VERSION 5.8 ;
BUSBITCHARS "[]" ;
DIVIDERCHAR "/" ;
UNITS
    DATABASE MICRONS 1000 ;
END UNITS

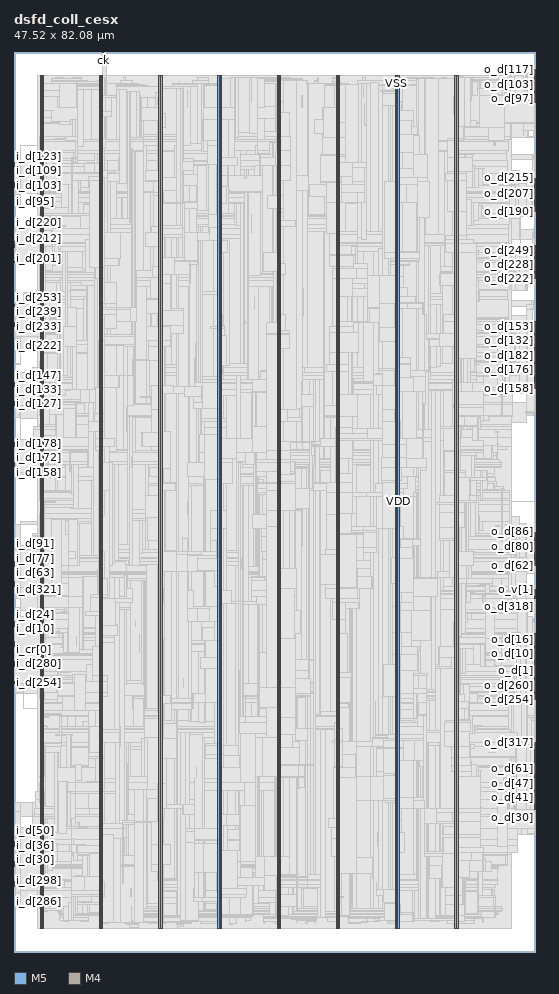
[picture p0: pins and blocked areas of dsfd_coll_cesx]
MACRO dsfd_coll_cesx
  FOREIGN dsfd_coll_cesx 0 0 ;
  CLASS BLOCK ;
  SIZE 47.52 BY 82.08 ;
  PIN ck
    DIRECTION INPUT ;
    USE SIGNAL ;
    PORT
      LAYER M5 ;
        RECT  8.112 81.996 8.136 82.08 ;
    END
  END ck
  PIN e_en
    DIRECTION INPUT ;
    USE SIGNAL ;
    PORT
      LAYER M5 ;
        RECT  8.208 81.996 8.232 82.08 ;
    END
  END e_en
  PIN i_cr[0]
    DIRECTION OUTPUT ;
    USE SIGNAL ;
    PORT
      LAYER M4 ;
        RECT  0 27.6 0.084 27.624 ;
    END
  END i_cr[0]
  PIN i_cr[1]
    DIRECTION OUTPUT ;
    USE SIGNAL ;
    PORT
      LAYER M4 ;
        RECT  0 27.696 0.084 27.72 ;
    END
  END i_cr[1]
  PIN i_d[0]
    DIRECTION INPUT ;
    USE SIGNAL ;
    PORT
      LAYER M4 ;
        RECT  0 27.792 0.084 27.816 ;
    END
  END i_d[0]
  PIN i_d[100]
    DIRECTION INPUT ;
    USE SIGNAL ;
    PORT
      LAYER M4 ;
        RECT  0 69.648 0.084 69.672 ;
    END
  END i_d[100]
  PIN i_d[101]
    DIRECTION INPUT ;
    USE SIGNAL ;
    PORT
      LAYER M4 ;
        RECT  0 69.744 0.084 69.768 ;
    END
  END i_d[101]
  PIN i_d[102]
    DIRECTION INPUT ;
    USE SIGNAL ;
    PORT
      LAYER M4 ;
        RECT  0 69.84 0.084 69.864 ;
    END
  END i_d[102]
  PIN i_d[103]
    DIRECTION INPUT ;
    USE SIGNAL ;
    PORT
      LAYER M4 ;
        RECT  0 69.936 0.084 69.96 ;
    END
  END i_d[103]
  PIN i_d[104]
    DIRECTION INPUT ;
    USE SIGNAL ;
    PORT
      LAYER M4 ;
        RECT  0 70.032 0.084 70.056 ;
    END
  END i_d[104]
  PIN i_d[105]
    DIRECTION INPUT ;
    USE SIGNAL ;
    PORT
      LAYER M4 ;
        RECT  0 70.128 0.084 70.152 ;
    END
  END i_d[105]
  PIN i_d[106]
    DIRECTION INPUT ;
    USE SIGNAL ;
    PORT
      LAYER M4 ;
        RECT  0 70.224 0.084 70.248 ;
    END
  END i_d[106]
  PIN i_d[107]
    DIRECTION INPUT ;
    USE SIGNAL ;
    PORT
      LAYER M4 ;
        RECT  0 70.32 0.084 70.344 ;
    END
  END i_d[107]
  PIN i_d[108]
    DIRECTION INPUT ;
    USE SIGNAL ;
    PORT
      LAYER M4 ;
        RECT  0 70.416 0.084 70.44 ;
    END
  END i_d[108]
  PIN i_d[109]
    DIRECTION INPUT ;
    USE SIGNAL ;
    PORT
      LAYER M4 ;
        RECT  0 70.512 0.084 70.536 ;
    END
  END i_d[109]
  PIN i_d[10]
    DIRECTION INPUT ;
    USE SIGNAL ;
    PORT
      LAYER M4 ;
        RECT  0 28.752 0.084 28.776 ;
    END
  END i_d[10]
  PIN i_d[110]
    DIRECTION INPUT ;
    USE SIGNAL ;
    PORT
      LAYER M4 ;
        RECT  0 70.608 0.084 70.632 ;
    END
  END i_d[110]
  PIN i_d[111]
    DIRECTION INPUT ;
    USE SIGNAL ;
    PORT
      LAYER M4 ;
        RECT  0 70.704 0.084 70.728 ;
    END
  END i_d[111]
  PIN i_d[112]
    DIRECTION INPUT ;
    USE SIGNAL ;
    PORT
      LAYER M4 ;
        RECT  0 70.8 0.084 70.824 ;
    END
  END i_d[112]
  PIN i_d[113]
    DIRECTION INPUT ;
    USE SIGNAL ;
    PORT
      LAYER M4 ;
        RECT  0 70.896 0.084 70.92 ;
    END
  END i_d[113]
  PIN i_d[114]
    DIRECTION INPUT ;
    USE SIGNAL ;
    PORT
      LAYER M4 ;
        RECT  0 70.992 0.084 71.016 ;
    END
  END i_d[114]
  PIN i_d[115]
    DIRECTION INPUT ;
    USE SIGNAL ;
    PORT
      LAYER M4 ;
        RECT  0 71.088 0.084 71.112 ;
    END
  END i_d[115]
  PIN i_d[116]
    DIRECTION INPUT ;
    USE SIGNAL ;
    PORT
      LAYER M4 ;
        RECT  0 71.184 0.084 71.208 ;
    END
  END i_d[116]
  PIN i_d[117]
    DIRECTION INPUT ;
    USE SIGNAL ;
    PORT
      LAYER M4 ;
        RECT  0 71.28 0.084 71.304 ;
    END
  END i_d[117]
  PIN i_d[118]
    DIRECTION INPUT ;
    USE SIGNAL ;
    PORT
      LAYER M4 ;
        RECT  0 71.376 0.084 71.4 ;
    END
  END i_d[118]
  PIN i_d[119]
    DIRECTION INPUT ;
    USE SIGNAL ;
    PORT
      LAYER M4 ;
        RECT  0 71.472 0.084 71.496 ;
    END
  END i_d[119]
  PIN i_d[11]
    DIRECTION INPUT ;
    USE SIGNAL ;
    PORT
      LAYER M4 ;
        RECT  0 28.848 0.084 28.872 ;
    END
  END i_d[11]
  PIN i_d[120]
    DIRECTION INPUT ;
    USE SIGNAL ;
    PORT
      LAYER M4 ;
        RECT  0 71.568 0.084 71.592 ;
    END
  END i_d[120]
  PIN i_d[121]
    DIRECTION INPUT ;
    USE SIGNAL ;
    PORT
      LAYER M4 ;
        RECT  0 71.664 0.084 71.688 ;
    END
  END i_d[121]
  PIN i_d[122]
    DIRECTION INPUT ;
    USE SIGNAL ;
    PORT
      LAYER M4 ;
        RECT  0 71.76 0.084 71.784 ;
    END
  END i_d[122]
  PIN i_d[123]
    DIRECTION INPUT ;
    USE SIGNAL ;
    PORT
      LAYER M4 ;
        RECT  0 71.856 0.084 71.88 ;
    END
  END i_d[123]
  PIN i_d[124]
    DIRECTION INPUT ;
    USE SIGNAL ;
    PORT
      LAYER M4 ;
        RECT  0 71.952 0.084 71.976 ;
    END
  END i_d[124]
  PIN i_d[125]
    DIRECTION INPUT ;
    USE SIGNAL ;
    PORT
      LAYER M4 ;
        RECT  0 72.048 0.084 72.072 ;
    END
  END i_d[125]
  PIN i_d[126]
    DIRECTION INPUT ;
    USE SIGNAL ;
    PORT
      LAYER M4 ;
        RECT  0 49.872 0.084 49.896 ;
    END
  END i_d[126]
  PIN i_d[127]
    DIRECTION INPUT ;
    USE SIGNAL ;
    PORT
      LAYER M4 ;
        RECT  0 49.968 0.084 49.992 ;
    END
  END i_d[127]
  PIN i_d[128]
    DIRECTION INPUT ;
    USE SIGNAL ;
    PORT
      LAYER M4 ;
        RECT  0 50.064 0.084 50.088 ;
    END
  END i_d[128]
  PIN i_d[129]
    DIRECTION INPUT ;
    USE SIGNAL ;
    PORT
      LAYER M4 ;
        RECT  0 50.16 0.084 50.184 ;
    END
  END i_d[129]
  PIN i_d[12]
    DIRECTION INPUT ;
    USE SIGNAL ;
    PORT
      LAYER M4 ;
        RECT  0 28.944 0.084 28.968 ;
    END
  END i_d[12]
  PIN i_d[130]
    DIRECTION INPUT ;
    USE SIGNAL ;
    PORT
      LAYER M4 ;
        RECT  0 50.256 0.084 50.28 ;
    END
  END i_d[130]
  PIN i_d[131]
    DIRECTION INPUT ;
    USE SIGNAL ;
    PORT
      LAYER M4 ;
        RECT  0 50.352 0.084 50.376 ;
    END
  END i_d[131]
  PIN i_d[132]
    DIRECTION INPUT ;
    USE SIGNAL ;
    PORT
      LAYER M4 ;
        RECT  0 50.448 0.084 50.472 ;
    END
  END i_d[132]
  PIN i_d[133]
    DIRECTION INPUT ;
    USE SIGNAL ;
    PORT
      LAYER M4 ;
        RECT  0 50.544 0.084 50.568 ;
    END
  END i_d[133]
  PIN i_d[134]
    DIRECTION INPUT ;
    USE SIGNAL ;
    PORT
      LAYER M4 ;
        RECT  0 50.64 0.084 50.664 ;
    END
  END i_d[134]
  PIN i_d[135]
    DIRECTION INPUT ;
    USE SIGNAL ;
    PORT
      LAYER M4 ;
        RECT  0 50.736 0.084 50.76 ;
    END
  END i_d[135]
  PIN i_d[136]
    DIRECTION INPUT ;
    USE SIGNAL ;
    PORT
      LAYER M4 ;
        RECT  0 50.832 0.084 50.856 ;
    END
  END i_d[136]
  PIN i_d[137]
    DIRECTION INPUT ;
    USE SIGNAL ;
    PORT
      LAYER M4 ;
        RECT  0 50.928 0.084 50.952 ;
    END
  END i_d[137]
  PIN i_d[138]
    DIRECTION INPUT ;
    USE SIGNAL ;
    PORT
      LAYER M4 ;
        RECT  0 51.024 0.084 51.048 ;
    END
  END i_d[138]
  PIN i_d[139]
    DIRECTION INPUT ;
    USE SIGNAL ;
    PORT
      LAYER M4 ;
        RECT  0 51.12 0.084 51.144 ;
    END
  END i_d[139]
  PIN i_d[13]
    DIRECTION INPUT ;
    USE SIGNAL ;
    PORT
      LAYER M4 ;
        RECT  0 29.04 0.084 29.064 ;
    END
  END i_d[13]
  PIN i_d[140]
    DIRECTION INPUT ;
    USE SIGNAL ;
    PORT
      LAYER M4 ;
        RECT  0 51.216 0.084 51.24 ;
    END
  END i_d[140]
  PIN i_d[141]
    DIRECTION INPUT ;
    USE SIGNAL ;
    PORT
      LAYER M4 ;
        RECT  0 51.312 0.084 51.336 ;
    END
  END i_d[141]
  PIN i_d[142]
    DIRECTION INPUT ;
    USE SIGNAL ;
    PORT
      LAYER M4 ;
        RECT  0 51.408 0.084 51.432 ;
    END
  END i_d[142]
  PIN i_d[143]
    DIRECTION INPUT ;
    USE SIGNAL ;
    PORT
      LAYER M4 ;
        RECT  0 51.504 0.084 51.528 ;
    END
  END i_d[143]
  PIN i_d[144]
    DIRECTION INPUT ;
    USE SIGNAL ;
    PORT
      LAYER M4 ;
        RECT  0 51.6 0.084 51.624 ;
    END
  END i_d[144]
  PIN i_d[145]
    DIRECTION INPUT ;
    USE SIGNAL ;
    PORT
      LAYER M4 ;
        RECT  0 51.696 0.084 51.72 ;
    END
  END i_d[145]
  PIN i_d[146]
    DIRECTION INPUT ;
    USE SIGNAL ;
    PORT
      LAYER M4 ;
        RECT  0 51.792 0.084 51.816 ;
    END
  END i_d[146]
  PIN i_d[147]
    DIRECTION INPUT ;
    USE SIGNAL ;
    PORT
      LAYER M4 ;
        RECT  0 51.888 0.084 51.912 ;
    END
  END i_d[147]
  PIN i_d[148]
    DIRECTION INPUT ;
    USE SIGNAL ;
    PORT
      LAYER M4 ;
        RECT  0 51.984 0.084 52.008 ;
    END
  END i_d[148]
  PIN i_d[149]
    DIRECTION INPUT ;
    USE SIGNAL ;
    PORT
      LAYER M4 ;
        RECT  0 52.08 0.084 52.104 ;
    END
  END i_d[149]
  PIN i_d[14]
    DIRECTION INPUT ;
    USE SIGNAL ;
    PORT
      LAYER M4 ;
        RECT  0 29.136 0.084 29.16 ;
    END
  END i_d[14]
  PIN i_d[150]
    DIRECTION INPUT ;
    USE SIGNAL ;
    PORT
      LAYER M4 ;
        RECT  0 52.176 0.084 52.2 ;
    END
  END i_d[150]
  PIN i_d[151]
    DIRECTION INPUT ;
    USE SIGNAL ;
    PORT
      LAYER M4 ;
        RECT  0 52.272 0.084 52.296 ;
    END
  END i_d[151]
  PIN i_d[152]
    DIRECTION INPUT ;
    USE SIGNAL ;
    PORT
      LAYER M4 ;
        RECT  0 52.368 0.084 52.392 ;
    END
  END i_d[152]
  PIN i_d[153]
    DIRECTION INPUT ;
    USE SIGNAL ;
    PORT
      LAYER M4 ;
        RECT  0 52.464 0.084 52.488 ;
    END
  END i_d[153]
  PIN i_d[154]
    DIRECTION INPUT ;
    USE SIGNAL ;
    PORT
      LAYER M4 ;
        RECT  0 52.56 0.084 52.584 ;
    END
  END i_d[154]
  PIN i_d[155]
    DIRECTION INPUT ;
    USE SIGNAL ;
    PORT
      LAYER M4 ;
        RECT  0 52.656 0.084 52.68 ;
    END
  END i_d[155]
  PIN i_d[156]
    DIRECTION INPUT ;
    USE SIGNAL ;
    PORT
      LAYER M4 ;
        RECT  0 52.752 0.084 52.776 ;
    END
  END i_d[156]
  PIN i_d[157]
    DIRECTION INPUT ;
    USE SIGNAL ;
    PORT
      LAYER M4 ;
        RECT  0 52.848 0.084 52.872 ;
    END
  END i_d[157]
  PIN i_d[158]
    DIRECTION INPUT ;
    USE SIGNAL ;
    PORT
      LAYER M4 ;
        RECT  0 43.728 0.084 43.752 ;
    END
  END i_d[158]
  PIN i_d[159]
    DIRECTION INPUT ;
    USE SIGNAL ;
    PORT
      LAYER M4 ;
        RECT  0 43.824 0.084 43.848 ;
    END
  END i_d[159]
  PIN i_d[15]
    DIRECTION INPUT ;
    USE SIGNAL ;
    PORT
      LAYER M4 ;
        RECT  0 29.232 0.084 29.256 ;
    END
  END i_d[15]
  PIN i_d[160]
    DIRECTION INPUT ;
    USE SIGNAL ;
    PORT
      LAYER M4 ;
        RECT  0 43.92 0.084 43.944 ;
    END
  END i_d[160]
  PIN i_d[161]
    DIRECTION INPUT ;
    USE SIGNAL ;
    PORT
      LAYER M4 ;
        RECT  0 44.016 0.084 44.04 ;
    END
  END i_d[161]
  PIN i_d[162]
    DIRECTION INPUT ;
    USE SIGNAL ;
    PORT
      LAYER M4 ;
        RECT  0 44.112 0.084 44.136 ;
    END
  END i_d[162]
  PIN i_d[163]
    DIRECTION INPUT ;
    USE SIGNAL ;
    PORT
      LAYER M4 ;
        RECT  0 44.208 0.084 44.232 ;
    END
  END i_d[163]
  PIN i_d[164]
    DIRECTION INPUT ;
    USE SIGNAL ;
    PORT
      LAYER M4 ;
        RECT  0 44.304 0.084 44.328 ;
    END
  END i_d[164]
  PIN i_d[165]
    DIRECTION INPUT ;
    USE SIGNAL ;
    PORT
      LAYER M4 ;
        RECT  0 44.4 0.084 44.424 ;
    END
  END i_d[165]
  PIN i_d[166]
    DIRECTION INPUT ;
    USE SIGNAL ;
    PORT
      LAYER M4 ;
        RECT  0 44.496 0.084 44.52 ;
    END
  END i_d[166]
  PIN i_d[167]
    DIRECTION INPUT ;
    USE SIGNAL ;
    PORT
      LAYER M4 ;
        RECT  0 44.592 0.084 44.616 ;
    END
  END i_d[167]
  PIN i_d[168]
    DIRECTION INPUT ;
    USE SIGNAL ;
    PORT
      LAYER M4 ;
        RECT  0 44.688 0.084 44.712 ;
    END
  END i_d[168]
  PIN i_d[169]
    DIRECTION INPUT ;
    USE SIGNAL ;
    PORT
      LAYER M4 ;
        RECT  0 44.784 0.084 44.808 ;
    END
  END i_d[169]
  PIN i_d[16]
    DIRECTION INPUT ;
    USE SIGNAL ;
    PORT
      LAYER M4 ;
        RECT  0 29.328 0.084 29.352 ;
    END
  END i_d[16]
  PIN i_d[170]
    DIRECTION INPUT ;
    USE SIGNAL ;
    PORT
      LAYER M4 ;
        RECT  0 44.88 0.084 44.904 ;
    END
  END i_d[170]
  PIN i_d[171]
    DIRECTION INPUT ;
    USE SIGNAL ;
    PORT
      LAYER M4 ;
        RECT  0 44.976 0.084 45 ;
    END
  END i_d[171]
  PIN i_d[172]
    DIRECTION INPUT ;
    USE SIGNAL ;
    PORT
      LAYER M4 ;
        RECT  0 45.072 0.084 45.096 ;
    END
  END i_d[172]
  PIN i_d[173]
    DIRECTION INPUT ;
    USE SIGNAL ;
    PORT
      LAYER M4 ;
        RECT  0 45.168 0.084 45.192 ;
    END
  END i_d[173]
  PIN i_d[174]
    DIRECTION INPUT ;
    USE SIGNAL ;
    PORT
      LAYER M4 ;
        RECT  0 45.264 0.084 45.288 ;
    END
  END i_d[174]
  PIN i_d[175]
    DIRECTION INPUT ;
    USE SIGNAL ;
    PORT
      LAYER M4 ;
        RECT  0 45.36 0.084 45.384 ;
    END
  END i_d[175]
  PIN i_d[176]
    DIRECTION INPUT ;
    USE SIGNAL ;
    PORT
      LAYER M4 ;
        RECT  0 45.456 0.084 45.48 ;
    END
  END i_d[176]
  PIN i_d[177]
    DIRECTION INPUT ;
    USE SIGNAL ;
    PORT
      LAYER M4 ;
        RECT  0 45.552 0.084 45.576 ;
    END
  END i_d[177]
  PIN i_d[178]
    DIRECTION INPUT ;
    USE SIGNAL ;
    PORT
      LAYER M4 ;
        RECT  0 45.648 0.084 45.672 ;
    END
  END i_d[178]
  PIN i_d[179]
    DIRECTION INPUT ;
    USE SIGNAL ;
    PORT
      LAYER M4 ;
        RECT  0 45.744 0.084 45.768 ;
    END
  END i_d[179]
  PIN i_d[17]
    DIRECTION INPUT ;
    USE SIGNAL ;
    PORT
      LAYER M4 ;
        RECT  0 29.424 0.084 29.448 ;
    END
  END i_d[17]
  PIN i_d[180]
    DIRECTION INPUT ;
    USE SIGNAL ;
    PORT
      LAYER M4 ;
        RECT  0 45.84 0.084 45.864 ;
    END
  END i_d[180]
  PIN i_d[181]
    DIRECTION INPUT ;
    USE SIGNAL ;
    PORT
      LAYER M4 ;
        RECT  0 45.936 0.084 45.96 ;
    END
  END i_d[181]
  PIN i_d[182]
    DIRECTION INPUT ;
    USE SIGNAL ;
    PORT
      LAYER M4 ;
        RECT  0 46.032 0.084 46.056 ;
    END
  END i_d[182]
  PIN i_d[183]
    DIRECTION INPUT ;
    USE SIGNAL ;
    PORT
      LAYER M4 ;
        RECT  0 46.128 0.084 46.152 ;
    END
  END i_d[183]
  PIN i_d[184]
    DIRECTION INPUT ;
    USE SIGNAL ;
    PORT
      LAYER M4 ;
        RECT  0 46.224 0.084 46.248 ;
    END
  END i_d[184]
  PIN i_d[185]
    DIRECTION INPUT ;
    USE SIGNAL ;
    PORT
      LAYER M4 ;
        RECT  0 46.32 0.084 46.344 ;
    END
  END i_d[185]
  PIN i_d[186]
    DIRECTION INPUT ;
    USE SIGNAL ;
    PORT
      LAYER M4 ;
        RECT  0 46.416 0.084 46.44 ;
    END
  END i_d[186]
  PIN i_d[187]
    DIRECTION INPUT ;
    USE SIGNAL ;
    PORT
      LAYER M4 ;
        RECT  0 46.512 0.084 46.536 ;
    END
  END i_d[187]
  PIN i_d[188]
    DIRECTION INPUT ;
    USE SIGNAL ;
    PORT
      LAYER M4 ;
        RECT  0 46.608 0.084 46.632 ;
    END
  END i_d[188]
  PIN i_d[189]
    DIRECTION INPUT ;
    USE SIGNAL ;
    PORT
      LAYER M4 ;
        RECT  0 46.704 0.084 46.728 ;
    END
  END i_d[189]
  PIN i_d[18]
    DIRECTION INPUT ;
    USE SIGNAL ;
    PORT
      LAYER M4 ;
        RECT  0 29.52 0.084 29.544 ;
    END
  END i_d[18]
  PIN i_d[190]
    DIRECTION INPUT ;
    USE SIGNAL ;
    PORT
      LAYER M4 ;
        RECT  0 62.928 0.084 62.952 ;
    END
  END i_d[190]
  PIN i_d[191]
    DIRECTION INPUT ;
    USE SIGNAL ;
    PORT
      LAYER M4 ;
        RECT  0 63.024 0.084 63.048 ;
    END
  END i_d[191]
  PIN i_d[192]
    DIRECTION INPUT ;
    USE SIGNAL ;
    PORT
      LAYER M4 ;
        RECT  0 63.12 0.084 63.144 ;
    END
  END i_d[192]
  PIN i_d[193]
    DIRECTION INPUT ;
    USE SIGNAL ;
    PORT
      LAYER M4 ;
        RECT  0 63.216 0.084 63.24 ;
    END
  END i_d[193]
  PIN i_d[194]
    DIRECTION INPUT ;
    USE SIGNAL ;
    PORT
      LAYER M4 ;
        RECT  0 63.312 0.084 63.336 ;
    END
  END i_d[194]
  PIN i_d[195]
    DIRECTION INPUT ;
    USE SIGNAL ;
    PORT
      LAYER M4 ;
        RECT  0 63.408 0.084 63.432 ;
    END
  END i_d[195]
  PIN i_d[196]
    DIRECTION INPUT ;
    USE SIGNAL ;
    PORT
      LAYER M4 ;
        RECT  0 63.504 0.084 63.528 ;
    END
  END i_d[196]
  PIN i_d[197]
    DIRECTION INPUT ;
    USE SIGNAL ;
    PORT
      LAYER M4 ;
        RECT  0 63.6 0.084 63.624 ;
    END
  END i_d[197]
  PIN i_d[198]
    DIRECTION INPUT ;
    USE SIGNAL ;
    PORT
      LAYER M4 ;
        RECT  0 63.696 0.084 63.72 ;
    END
  END i_d[198]
  PIN i_d[199]
    DIRECTION INPUT ;
    USE SIGNAL ;
    PORT
      LAYER M4 ;
        RECT  0 63.792 0.084 63.816 ;
    END
  END i_d[199]
  PIN i_d[19]
    DIRECTION INPUT ;
    USE SIGNAL ;
    PORT
      LAYER M4 ;
        RECT  0 29.616 0.084 29.64 ;
    END
  END i_d[19]
  PIN i_d[1]
    DIRECTION INPUT ;
    USE SIGNAL ;
    PORT
      LAYER M4 ;
        RECT  0 27.888 0.084 27.912 ;
    END
  END i_d[1]
  PIN i_d[200]
    DIRECTION INPUT ;
    USE SIGNAL ;
    PORT
      LAYER M4 ;
        RECT  0 63.888 0.084 63.912 ;
    END
  END i_d[200]
  PIN i_d[201]
    DIRECTION INPUT ;
    USE SIGNAL ;
    PORT
      LAYER M4 ;
        RECT  0 63.984 0.084 64.008 ;
    END
  END i_d[201]
  PIN i_d[202]
    DIRECTION INPUT ;
    USE SIGNAL ;
    PORT
      LAYER M4 ;
        RECT  0 64.08 0.084 64.104 ;
    END
  END i_d[202]
  PIN i_d[203]
    DIRECTION INPUT ;
    USE SIGNAL ;
    PORT
      LAYER M4 ;
        RECT  0 64.176 0.084 64.2 ;
    END
  END i_d[203]
  PIN i_d[204]
    DIRECTION INPUT ;
    USE SIGNAL ;
    PORT
      LAYER M4 ;
        RECT  0 64.272 0.084 64.296 ;
    END
  END i_d[204]
  PIN i_d[205]
    DIRECTION INPUT ;
    USE SIGNAL ;
    PORT
      LAYER M4 ;
        RECT  0 64.368 0.084 64.392 ;
    END
  END i_d[205]
  PIN i_d[206]
    DIRECTION INPUT ;
    USE SIGNAL ;
    PORT
      LAYER M4 ;
        RECT  0 64.464 0.084 64.488 ;
    END
  END i_d[206]
  PIN i_d[207]
    DIRECTION INPUT ;
    USE SIGNAL ;
    PORT
      LAYER M4 ;
        RECT  0 64.56 0.084 64.584 ;
    END
  END i_d[207]
  PIN i_d[208]
    DIRECTION INPUT ;
    USE SIGNAL ;
    PORT
      LAYER M4 ;
        RECT  0 64.656 0.084 64.68 ;
    END
  END i_d[208]
  PIN i_d[209]
    DIRECTION INPUT ;
    USE SIGNAL ;
    PORT
      LAYER M4 ;
        RECT  0 64.752 0.084 64.776 ;
    END
  END i_d[209]
  PIN i_d[20]
    DIRECTION INPUT ;
    USE SIGNAL ;
    PORT
      LAYER M4 ;
        RECT  0 29.712 0.084 29.736 ;
    END
  END i_d[20]
  PIN i_d[210]
    DIRECTION INPUT ;
    USE SIGNAL ;
    PORT
      LAYER M4 ;
        RECT  0 64.848 0.084 64.872 ;
    END
  END i_d[210]
  PIN i_d[211]
    DIRECTION INPUT ;
    USE SIGNAL ;
    PORT
      LAYER M4 ;
        RECT  0 64.944 0.084 64.968 ;
    END
  END i_d[211]
  PIN i_d[212]
    DIRECTION INPUT ;
    USE SIGNAL ;
    PORT
      LAYER M4 ;
        RECT  0 65.04 0.084 65.064 ;
    END
  END i_d[212]
  PIN i_d[213]
    DIRECTION INPUT ;
    USE SIGNAL ;
    PORT
      LAYER M4 ;
        RECT  0 65.136 0.084 65.16 ;
    END
  END i_d[213]
  PIN i_d[214]
    DIRECTION INPUT ;
    USE SIGNAL ;
    PORT
      LAYER M4 ;
        RECT  0 65.232 0.084 65.256 ;
    END
  END i_d[214]
  PIN i_d[215]
    DIRECTION INPUT ;
    USE SIGNAL ;
    PORT
      LAYER M4 ;
        RECT  0 65.328 0.084 65.352 ;
    END
  END i_d[215]
  PIN i_d[216]
    DIRECTION INPUT ;
    USE SIGNAL ;
    PORT
      LAYER M4 ;
        RECT  0 65.424 0.084 65.448 ;
    END
  END i_d[216]
  PIN i_d[217]
    DIRECTION INPUT ;
    USE SIGNAL ;
    PORT
      LAYER M4 ;
        RECT  0 65.52 0.084 65.544 ;
    END
  END i_d[217]
  PIN i_d[218]
    DIRECTION INPUT ;
    USE SIGNAL ;
    PORT
      LAYER M4 ;
        RECT  0 65.616 0.084 65.64 ;
    END
  END i_d[218]
  PIN i_d[219]
    DIRECTION INPUT ;
    USE SIGNAL ;
    PORT
      LAYER M4 ;
        RECT  0 65.712 0.084 65.736 ;
    END
  END i_d[219]
  PIN i_d[21]
    DIRECTION INPUT ;
    USE SIGNAL ;
    PORT
      LAYER M4 ;
        RECT  0 29.808 0.084 29.832 ;
    END
  END i_d[21]
  PIN i_d[220]
    DIRECTION INPUT ;
    USE SIGNAL ;
    PORT
      LAYER M4 ;
        RECT  0 65.808 0.084 65.832 ;
    END
  END i_d[220]
  PIN i_d[221]
    DIRECTION INPUT ;
    USE SIGNAL ;
    PORT
      LAYER M4 ;
        RECT  0 65.904 0.084 65.928 ;
    END
  END i_d[221]
  PIN i_d[222]
    DIRECTION INPUT ;
    USE SIGNAL ;
    PORT
      LAYER M4 ;
        RECT  0 56.016 0.084 56.04 ;
    END
  END i_d[222]
  PIN i_d[223]
    DIRECTION INPUT ;
    USE SIGNAL ;
    PORT
      LAYER M4 ;
        RECT  0 56.112 0.084 56.136 ;
    END
  END i_d[223]
  PIN i_d[224]
    DIRECTION INPUT ;
    USE SIGNAL ;
    PORT
      LAYER M4 ;
        RECT  0 56.208 0.084 56.232 ;
    END
  END i_d[224]
  PIN i_d[225]
    DIRECTION INPUT ;
    USE SIGNAL ;
    PORT
      LAYER M4 ;
        RECT  0 56.304 0.084 56.328 ;
    END
  END i_d[225]
  PIN i_d[226]
    DIRECTION INPUT ;
    USE SIGNAL ;
    PORT
      LAYER M4 ;
        RECT  0 56.4 0.084 56.424 ;
    END
  END i_d[226]
  PIN i_d[227]
    DIRECTION INPUT ;
    USE SIGNAL ;
    PORT
      LAYER M4 ;
        RECT  0 56.496 0.084 56.52 ;
    END
  END i_d[227]
  PIN i_d[228]
    DIRECTION INPUT ;
    USE SIGNAL ;
    PORT
      LAYER M4 ;
        RECT  0 56.592 0.084 56.616 ;
    END
  END i_d[228]
  PIN i_d[229]
    DIRECTION INPUT ;
    USE SIGNAL ;
    PORT
      LAYER M4 ;
        RECT  0 56.688 0.084 56.712 ;
    END
  END i_d[229]
  PIN i_d[22]
    DIRECTION INPUT ;
    USE SIGNAL ;
    PORT
      LAYER M4 ;
        RECT  0 29.904 0.084 29.928 ;
    END
  END i_d[22]
  PIN i_d[230]
    DIRECTION INPUT ;
    USE SIGNAL ;
    PORT
      LAYER M4 ;
        RECT  0 56.784 0.084 56.808 ;
    END
  END i_d[230]
  PIN i_d[231]
    DIRECTION INPUT ;
    USE SIGNAL ;
    PORT
      LAYER M4 ;
        RECT  0 56.88 0.084 56.904 ;
    END
  END i_d[231]
  PIN i_d[232]
    DIRECTION INPUT ;
    USE SIGNAL ;
    PORT
      LAYER M4 ;
        RECT  0 56.976 0.084 57 ;
    END
  END i_d[232]
  PIN i_d[233]
    DIRECTION INPUT ;
    USE SIGNAL ;
    PORT
      LAYER M4 ;
        RECT  0 57.072 0.084 57.096 ;
    END
  END i_d[233]
  PIN i_d[234]
    DIRECTION INPUT ;
    USE SIGNAL ;
    PORT
      LAYER M4 ;
        RECT  0 57.168 0.084 57.192 ;
    END
  END i_d[234]
  PIN i_d[235]
    DIRECTION INPUT ;
    USE SIGNAL ;
    PORT
      LAYER M4 ;
        RECT  0 57.264 0.084 57.288 ;
    END
  END i_d[235]
  PIN i_d[236]
    DIRECTION INPUT ;
    USE SIGNAL ;
    PORT
      LAYER M4 ;
        RECT  0 57.36 0.084 57.384 ;
    END
  END i_d[236]
  PIN i_d[237]
    DIRECTION INPUT ;
    USE SIGNAL ;
    PORT
      LAYER M4 ;
        RECT  0 57.456 0.084 57.48 ;
    END
  END i_d[237]
  PIN i_d[238]
    DIRECTION INPUT ;
    USE SIGNAL ;
    PORT
      LAYER M4 ;
        RECT  0 57.552 0.084 57.576 ;
    END
  END i_d[238]
  PIN i_d[239]
    DIRECTION INPUT ;
    USE SIGNAL ;
    PORT
      LAYER M4 ;
        RECT  0 57.648 0.084 57.672 ;
    END
  END i_d[239]
  PIN i_d[23]
    DIRECTION INPUT ;
    USE SIGNAL ;
    PORT
      LAYER M4 ;
        RECT  0 30 0.084 30.024 ;
    END
  END i_d[23]
  PIN i_d[240]
    DIRECTION INPUT ;
    USE SIGNAL ;
    PORT
      LAYER M4 ;
        RECT  0 57.744 0.084 57.768 ;
    END
  END i_d[240]
  PIN i_d[241]
    DIRECTION INPUT ;
    USE SIGNAL ;
    PORT
      LAYER M4 ;
        RECT  0 57.84 0.084 57.864 ;
    END
  END i_d[241]
  PIN i_d[242]
    DIRECTION INPUT ;
    USE SIGNAL ;
    PORT
      LAYER M4 ;
        RECT  0 57.936 0.084 57.96 ;
    END
  END i_d[242]
  PIN i_d[243]
    DIRECTION INPUT ;
    USE SIGNAL ;
    PORT
      LAYER M4 ;
        RECT  0 58.032 0.084 58.056 ;
    END
  END i_d[243]
  PIN i_d[244]
    DIRECTION INPUT ;
    USE SIGNAL ;
    PORT
      LAYER M4 ;
        RECT  0 58.128 0.084 58.152 ;
    END
  END i_d[244]
  PIN i_d[245]
    DIRECTION INPUT ;
    USE SIGNAL ;
    PORT
      LAYER M4 ;
        RECT  0 58.224 0.084 58.248 ;
    END
  END i_d[245]
  PIN i_d[246]
    DIRECTION INPUT ;
    USE SIGNAL ;
    PORT
      LAYER M4 ;
        RECT  0 58.32 0.084 58.344 ;
    END
  END i_d[246]
  PIN i_d[247]
    DIRECTION INPUT ;
    USE SIGNAL ;
    PORT
      LAYER M4 ;
        RECT  0 58.416 0.084 58.44 ;
    END
  END i_d[247]
  PIN i_d[248]
    DIRECTION INPUT ;
    USE SIGNAL ;
    PORT
      LAYER M4 ;
        RECT  0 58.512 0.084 58.536 ;
    END
  END i_d[248]
  PIN i_d[249]
    DIRECTION INPUT ;
    USE SIGNAL ;
    PORT
      LAYER M4 ;
        RECT  0 58.608 0.084 58.632 ;
    END
  END i_d[249]
  PIN i_d[24]
    DIRECTION INPUT ;
    USE SIGNAL ;
    PORT
      LAYER M4 ;
        RECT  0 30.096 0.084 30.12 ;
    END
  END i_d[24]
  PIN i_d[250]
    DIRECTION INPUT ;
    USE SIGNAL ;
    PORT
      LAYER M4 ;
        RECT  0 58.704 0.084 58.728 ;
    END
  END i_d[250]
  PIN i_d[251]
    DIRECTION INPUT ;
    USE SIGNAL ;
    PORT
      LAYER M4 ;
        RECT  0 58.8 0.084 58.824 ;
    END
  END i_d[251]
  PIN i_d[252]
    DIRECTION INPUT ;
    USE SIGNAL ;
    PORT
      LAYER M4 ;
        RECT  0 58.896 0.084 58.92 ;
    END
  END i_d[252]
  PIN i_d[253]
    DIRECTION INPUT ;
    USE SIGNAL ;
    PORT
      LAYER M4 ;
        RECT  0 58.992 0.084 59.016 ;
    END
  END i_d[253]
  PIN i_d[254]
    DIRECTION INPUT ;
    USE SIGNAL ;
    PORT
      LAYER M4 ;
        RECT  0 24.528 0.084 24.552 ;
    END
  END i_d[254]
  PIN i_d[255]
    DIRECTION INPUT ;
    USE SIGNAL ;
    PORT
      LAYER M4 ;
        RECT  0 24.624 0.084 24.648 ;
    END
  END i_d[255]
  PIN i_d[256]
    DIRECTION INPUT ;
    USE SIGNAL ;
    PORT
      LAYER M4 ;
        RECT  0 24.72 0.084 24.744 ;
    END
  END i_d[256]
  PIN i_d[257]
    DIRECTION INPUT ;
    USE SIGNAL ;
    PORT
      LAYER M4 ;
        RECT  0 24.816 0.084 24.84 ;
    END
  END i_d[257]
  PIN i_d[258]
    DIRECTION INPUT ;
    USE SIGNAL ;
    PORT
      LAYER M4 ;
        RECT  0 24.912 0.084 24.936 ;
    END
  END i_d[258]
  PIN i_d[259]
    DIRECTION INPUT ;
    USE SIGNAL ;
    PORT
      LAYER M4 ;
        RECT  0 25.008 0.084 25.032 ;
    END
  END i_d[259]
  PIN i_d[25]
    DIRECTION INPUT ;
    USE SIGNAL ;
    PORT
      LAYER M4 ;
        RECT  0 30.192 0.084 30.216 ;
    END
  END i_d[25]
  PIN i_d[260]
    DIRECTION INPUT ;
    USE SIGNAL ;
    PORT
      LAYER M4 ;
        RECT  0 25.104 0.084 25.128 ;
    END
  END i_d[260]
  PIN i_d[261]
    DIRECTION INPUT ;
    USE SIGNAL ;
    PORT
      LAYER M4 ;
        RECT  0 25.2 0.084 25.224 ;
    END
  END i_d[261]
  PIN i_d[262]
    DIRECTION INPUT ;
    USE SIGNAL ;
    PORT
      LAYER M4 ;
        RECT  0 25.296 0.084 25.32 ;
    END
  END i_d[262]
  PIN i_d[263]
    DIRECTION INPUT ;
    USE SIGNAL ;
    PORT
      LAYER M4 ;
        RECT  0 25.392 0.084 25.416 ;
    END
  END i_d[263]
  PIN i_d[264]
    DIRECTION INPUT ;
    USE SIGNAL ;
    PORT
      LAYER M4 ;
        RECT  0 25.488 0.084 25.512 ;
    END
  END i_d[264]
  PIN i_d[265]
    DIRECTION INPUT ;
    USE SIGNAL ;
    PORT
      LAYER M4 ;
        RECT  0 25.584 0.084 25.608 ;
    END
  END i_d[265]
  PIN i_d[266]
    DIRECTION INPUT ;
    USE SIGNAL ;
    PORT
      LAYER M4 ;
        RECT  0 25.68 0.084 25.704 ;
    END
  END i_d[266]
  PIN i_d[267]
    DIRECTION INPUT ;
    USE SIGNAL ;
    PORT
      LAYER M4 ;
        RECT  0 25.776 0.084 25.8 ;
    END
  END i_d[267]
  PIN i_d[268]
    DIRECTION INPUT ;
    USE SIGNAL ;
    PORT
      LAYER M4 ;
        RECT  0 25.872 0.084 25.896 ;
    END
  END i_d[268]
  PIN i_d[269]
    DIRECTION INPUT ;
    USE SIGNAL ;
    PORT
      LAYER M4 ;
        RECT  0 25.968 0.084 25.992 ;
    END
  END i_d[269]
  PIN i_d[26]
    DIRECTION INPUT ;
    USE SIGNAL ;
    PORT
      LAYER M4 ;
        RECT  0 30.288 0.084 30.312 ;
    END
  END i_d[26]
  PIN i_d[270]
    DIRECTION INPUT ;
    USE SIGNAL ;
    PORT
      LAYER M4 ;
        RECT  0 26.064 0.084 26.088 ;
    END
  END i_d[270]
  PIN i_d[271]
    DIRECTION INPUT ;
    USE SIGNAL ;
    PORT
      LAYER M4 ;
        RECT  0 26.16 0.084 26.184 ;
    END
  END i_d[271]
  PIN i_d[272]
    DIRECTION INPUT ;
    USE SIGNAL ;
    PORT
      LAYER M4 ;
        RECT  0 26.256 0.084 26.28 ;
    END
  END i_d[272]
  PIN i_d[273]
    DIRECTION INPUT ;
    USE SIGNAL ;
    PORT
      LAYER M4 ;
        RECT  0 26.352 0.084 26.376 ;
    END
  END i_d[273]
  PIN i_d[274]
    DIRECTION INPUT ;
    USE SIGNAL ;
    PORT
      LAYER M4 ;
        RECT  0 26.448 0.084 26.472 ;
    END
  END i_d[274]
  PIN i_d[275]
    DIRECTION INPUT ;
    USE SIGNAL ;
    PORT
      LAYER M4 ;
        RECT  0 26.544 0.084 26.568 ;
    END
  END i_d[275]
  PIN i_d[276]
    DIRECTION INPUT ;
    USE SIGNAL ;
    PORT
      LAYER M4 ;
        RECT  0 26.64 0.084 26.664 ;
    END
  END i_d[276]
  PIN i_d[277]
    DIRECTION INPUT ;
    USE SIGNAL ;
    PORT
      LAYER M4 ;
        RECT  0 26.736 0.084 26.76 ;
    END
  END i_d[277]
  PIN i_d[278]
    DIRECTION INPUT ;
    USE SIGNAL ;
    PORT
      LAYER M4 ;
        RECT  0 26.832 0.084 26.856 ;
    END
  END i_d[278]
  PIN i_d[279]
    DIRECTION INPUT ;
    USE SIGNAL ;
    PORT
      LAYER M4 ;
        RECT  0 26.928 0.084 26.952 ;
    END
  END i_d[279]
  PIN i_d[27]
    DIRECTION INPUT ;
    USE SIGNAL ;
    PORT
      LAYER M4 ;
        RECT  0 30.384 0.084 30.408 ;
    END
  END i_d[27]
  PIN i_d[280]
    DIRECTION INPUT ;
    USE SIGNAL ;
    PORT
      LAYER M4 ;
        RECT  0 27.024 0.084 27.048 ;
    END
  END i_d[280]
  PIN i_d[281]
    DIRECTION INPUT ;
    USE SIGNAL ;
    PORT
      LAYER M4 ;
        RECT  0 27.12 0.084 27.144 ;
    END
  END i_d[281]
  PIN i_d[282]
    DIRECTION INPUT ;
    USE SIGNAL ;
    PORT
      LAYER M4 ;
        RECT  0 27.216 0.084 27.24 ;
    END
  END i_d[282]
  PIN i_d[283]
    DIRECTION INPUT ;
    USE SIGNAL ;
    PORT
      LAYER M4 ;
        RECT  0 27.312 0.084 27.336 ;
    END
  END i_d[283]
  PIN i_d[284]
    DIRECTION INPUT ;
    USE SIGNAL ;
    PORT
      LAYER M4 ;
        RECT  0 27.408 0.084 27.432 ;
    END
  END i_d[284]
  PIN i_d[285]
    DIRECTION INPUT ;
    USE SIGNAL ;
    PORT
      LAYER M4 ;
        RECT  0 27.504 0.084 27.528 ;
    END
  END i_d[285]
  PIN i_d[286]
    DIRECTION INPUT ;
    USE SIGNAL ;
    PORT
      LAYER M4 ;
        RECT  0 5.328 0.084 5.352 ;
    END
  END i_d[286]
  PIN i_d[287]
    DIRECTION INPUT ;
    USE SIGNAL ;
    PORT
      LAYER M4 ;
        RECT  0 5.424 0.084 5.448 ;
    END
  END i_d[287]
  PIN i_d[288]
    DIRECTION INPUT ;
    USE SIGNAL ;
    PORT
      LAYER M4 ;
        RECT  0 5.52 0.084 5.544 ;
    END
  END i_d[288]
  PIN i_d[289]
    DIRECTION INPUT ;
    USE SIGNAL ;
    PORT
      LAYER M4 ;
        RECT  0 5.616 0.084 5.64 ;
    END
  END i_d[289]
  PIN i_d[28]
    DIRECTION INPUT ;
    USE SIGNAL ;
    PORT
      LAYER M4 ;
        RECT  0 30.48 0.084 30.504 ;
    END
  END i_d[28]
  PIN i_d[290]
    DIRECTION INPUT ;
    USE SIGNAL ;
    PORT
      LAYER M4 ;
        RECT  0 5.712 0.084 5.736 ;
    END
  END i_d[290]
  PIN i_d[291]
    DIRECTION INPUT ;
    USE SIGNAL ;
    PORT
      LAYER M4 ;
        RECT  0 5.808 0.084 5.832 ;
    END
  END i_d[291]
  PIN i_d[292]
    DIRECTION INPUT ;
    USE SIGNAL ;
    PORT
      LAYER M4 ;
        RECT  0 5.904 0.084 5.928 ;
    END
  END i_d[292]
  PIN i_d[293]
    DIRECTION INPUT ;
    USE SIGNAL ;
    PORT
      LAYER M4 ;
        RECT  0 6 0.084 6.024 ;
    END
  END i_d[293]
  PIN i_d[294]
    DIRECTION INPUT ;
    USE SIGNAL ;
    PORT
      LAYER M4 ;
        RECT  0 6.096 0.084 6.12 ;
    END
  END i_d[294]
  PIN i_d[295]
    DIRECTION INPUT ;
    USE SIGNAL ;
    PORT
      LAYER M4 ;
        RECT  0 6.192 0.084 6.216 ;
    END
  END i_d[295]
  PIN i_d[296]
    DIRECTION INPUT ;
    USE SIGNAL ;
    PORT
      LAYER M4 ;
        RECT  0 6.288 0.084 6.312 ;
    END
  END i_d[296]
  PIN i_d[297]
    DIRECTION INPUT ;
    USE SIGNAL ;
    PORT
      LAYER M4 ;
        RECT  0 6.384 0.084 6.408 ;
    END
  END i_d[297]
  PIN i_d[298]
    DIRECTION INPUT ;
    USE SIGNAL ;
    PORT
      LAYER M4 ;
        RECT  0 6.48 0.084 6.504 ;
    END
  END i_d[298]
  PIN i_d[299]
    DIRECTION INPUT ;
    USE SIGNAL ;
    PORT
      LAYER M4 ;
        RECT  0 6.576 0.084 6.6 ;
    END
  END i_d[299]
  PIN i_d[29]
    DIRECTION INPUT ;
    USE SIGNAL ;
    PORT
      LAYER M4 ;
        RECT  0 30.576 0.084 30.6 ;
    END
  END i_d[29]
  PIN i_d[2]
    DIRECTION INPUT ;
    USE SIGNAL ;
    PORT
      LAYER M4 ;
        RECT  0 27.984 0.084 28.008 ;
    END
  END i_d[2]
  PIN i_d[300]
    DIRECTION INPUT ;
    USE SIGNAL ;
    PORT
      LAYER M4 ;
        RECT  0 6.672 0.084 6.696 ;
    END
  END i_d[300]
  PIN i_d[301]
    DIRECTION INPUT ;
    USE SIGNAL ;
    PORT
      LAYER M4 ;
        RECT  0 6.768 0.084 6.792 ;
    END
  END i_d[301]
  PIN i_d[302]
    DIRECTION INPUT ;
    USE SIGNAL ;
    PORT
      LAYER M4 ;
        RECT  0 6.864 0.084 6.888 ;
    END
  END i_d[302]
  PIN i_d[303]
    DIRECTION INPUT ;
    USE SIGNAL ;
    PORT
      LAYER M4 ;
        RECT  0 6.96 0.084 6.984 ;
    END
  END i_d[303]
  PIN i_d[304]
    DIRECTION INPUT ;
    USE SIGNAL ;
    PORT
      LAYER M4 ;
        RECT  0 7.056 0.084 7.08 ;
    END
  END i_d[304]
  PIN i_d[305]
    DIRECTION INPUT ;
    USE SIGNAL ;
    PORT
      LAYER M4 ;
        RECT  0 7.152 0.084 7.176 ;
    END
  END i_d[305]
  PIN i_d[306]
    DIRECTION INPUT ;
    USE SIGNAL ;
    PORT
      LAYER M4 ;
        RECT  0 7.248 0.084 7.272 ;
    END
  END i_d[306]
  PIN i_d[307]
    DIRECTION INPUT ;
    USE SIGNAL ;
    PORT
      LAYER M4 ;
        RECT  0 7.344 0.084 7.368 ;
    END
  END i_d[307]
  PIN i_d[308]
    DIRECTION INPUT ;
    USE SIGNAL ;
    PORT
      LAYER M4 ;
        RECT  0 7.44 0.084 7.464 ;
    END
  END i_d[308]
  PIN i_d[309]
    DIRECTION INPUT ;
    USE SIGNAL ;
    PORT
      LAYER M4 ;
        RECT  0 7.536 0.084 7.56 ;
    END
  END i_d[309]
  PIN i_d[30]
    DIRECTION INPUT ;
    USE SIGNAL ;
    PORT
      LAYER M4 ;
        RECT  0 8.4 0.084 8.424 ;
    END
  END i_d[30]
  PIN i_d[310]
    DIRECTION INPUT ;
    USE SIGNAL ;
    PORT
      LAYER M4 ;
        RECT  0 7.632 0.084 7.656 ;
    END
  END i_d[310]
  PIN i_d[311]
    DIRECTION INPUT ;
    USE SIGNAL ;
    PORT
      LAYER M4 ;
        RECT  0 7.728 0.084 7.752 ;
    END
  END i_d[311]
  PIN i_d[312]
    DIRECTION INPUT ;
    USE SIGNAL ;
    PORT
      LAYER M4 ;
        RECT  0 7.824 0.084 7.848 ;
    END
  END i_d[312]
  PIN i_d[313]
    DIRECTION INPUT ;
    USE SIGNAL ;
    PORT
      LAYER M4 ;
        RECT  0 7.92 0.084 7.944 ;
    END
  END i_d[313]
  PIN i_d[314]
    DIRECTION INPUT ;
    USE SIGNAL ;
    PORT
      LAYER M4 ;
        RECT  0 8.016 0.084 8.04 ;
    END
  END i_d[314]
  PIN i_d[315]
    DIRECTION INPUT ;
    USE SIGNAL ;
    PORT
      LAYER M4 ;
        RECT  0 8.112 0.084 8.136 ;
    END
  END i_d[315]
  PIN i_d[316]
    DIRECTION INPUT ;
    USE SIGNAL ;
    PORT
      LAYER M4 ;
        RECT  0 8.208 0.084 8.232 ;
    END
  END i_d[316]
  PIN i_d[317]
    DIRECTION INPUT ;
    USE SIGNAL ;
    PORT
      LAYER M4 ;
        RECT  0 8.304 0.084 8.328 ;
    END
  END i_d[317]
  PIN i_d[318]
    DIRECTION INPUT ;
    USE SIGNAL ;
    PORT
      LAYER M4 ;
        RECT  0 32.784 0.084 32.808 ;
    END
  END i_d[318]
  PIN i_d[319]
    DIRECTION INPUT ;
    USE SIGNAL ;
    PORT
      LAYER M4 ;
        RECT  0 32.88 0.084 32.904 ;
    END
  END i_d[319]
  PIN i_d[31]
    DIRECTION INPUT ;
    USE SIGNAL ;
    PORT
      LAYER M4 ;
        RECT  0 8.496 0.084 8.52 ;
    END
  END i_d[31]
  PIN i_d[320]
    DIRECTION INPUT ;
    USE SIGNAL ;
    PORT
      LAYER M4 ;
        RECT  0 32.976 0.084 33 ;
    END
  END i_d[320]
  PIN i_d[321]
    DIRECTION INPUT ;
    USE SIGNAL ;
    PORT
      LAYER M4 ;
        RECT  0 33.072 0.084 33.096 ;
    END
  END i_d[321]
  PIN i_d[322]
    DIRECTION INPUT ;
    USE SIGNAL ;
    PORT
      LAYER M4 ;
        RECT  0 33.168 0.084 33.192 ;
    END
  END i_d[322]
  PIN i_d[323]
    DIRECTION INPUT ;
    USE SIGNAL ;
    PORT
      LAYER M4 ;
        RECT  0 33.264 0.084 33.288 ;
    END
  END i_d[323]
  PIN i_d[324]
    DIRECTION INPUT ;
    USE SIGNAL ;
    PORT
      LAYER M4 ;
        RECT  0 33.36 0.084 33.384 ;
    END
  END i_d[324]
  PIN i_d[325]
    DIRECTION INPUT ;
    USE SIGNAL ;
    PORT
      LAYER M4 ;
        RECT  0 33.456 0.084 33.48 ;
    END
  END i_d[325]
  PIN i_d[32]
    DIRECTION INPUT ;
    USE SIGNAL ;
    PORT
      LAYER M4 ;
        RECT  0 8.592 0.084 8.616 ;
    END
  END i_d[32]
  PIN i_d[33]
    DIRECTION INPUT ;
    USE SIGNAL ;
    PORT
      LAYER M4 ;
        RECT  0 8.688 0.084 8.712 ;
    END
  END i_d[33]
  PIN i_d[34]
    DIRECTION INPUT ;
    USE SIGNAL ;
    PORT
      LAYER M4 ;
        RECT  0 8.784 0.084 8.808 ;
    END
  END i_d[34]
  PIN i_d[35]
    DIRECTION INPUT ;
    USE SIGNAL ;
    PORT
      LAYER M4 ;
        RECT  0 8.88 0.084 8.904 ;
    END
  END i_d[35]
  PIN i_d[36]
    DIRECTION INPUT ;
    USE SIGNAL ;
    PORT
      LAYER M4 ;
        RECT  0 8.976 0.084 9 ;
    END
  END i_d[36]
  PIN i_d[37]
    DIRECTION INPUT ;
    USE SIGNAL ;
    PORT
      LAYER M4 ;
        RECT  0 9.072 0.084 9.096 ;
    END
  END i_d[37]
  PIN i_d[38]
    DIRECTION INPUT ;
    USE SIGNAL ;
    PORT
      LAYER M4 ;
        RECT  0 9.168 0.084 9.192 ;
    END
  END i_d[38]
  PIN i_d[39]
    DIRECTION INPUT ;
    USE SIGNAL ;
    PORT
      LAYER M4 ;
        RECT  0 9.264 0.084 9.288 ;
    END
  END i_d[39]
  PIN i_d[3]
    DIRECTION INPUT ;
    USE SIGNAL ;
    PORT
      LAYER M4 ;
        RECT  0 28.08 0.084 28.104 ;
    END
  END i_d[3]
  PIN i_d[40]
    DIRECTION INPUT ;
    USE SIGNAL ;
    PORT
      LAYER M4 ;
        RECT  0 9.36 0.084 9.384 ;
    END
  END i_d[40]
  PIN i_d[41]
    DIRECTION INPUT ;
    USE SIGNAL ;
    PORT
      LAYER M4 ;
        RECT  0 9.456 0.084 9.48 ;
    END
  END i_d[41]
  PIN i_d[42]
    DIRECTION INPUT ;
    USE SIGNAL ;
    PORT
      LAYER M4 ;
        RECT  0 9.552 0.084 9.576 ;
    END
  END i_d[42]
  PIN i_d[43]
    DIRECTION INPUT ;
    USE SIGNAL ;
    PORT
      LAYER M4 ;
        RECT  0 9.648 0.084 9.672 ;
    END
  END i_d[43]
  PIN i_d[44]
    DIRECTION INPUT ;
    USE SIGNAL ;
    PORT
      LAYER M4 ;
        RECT  0 9.744 0.084 9.768 ;
    END
  END i_d[44]
  PIN i_d[45]
    DIRECTION INPUT ;
    USE SIGNAL ;
    PORT
      LAYER M4 ;
        RECT  0 9.84 0.084 9.864 ;
    END
  END i_d[45]
  PIN i_d[46]
    DIRECTION INPUT ;
    USE SIGNAL ;
    PORT
      LAYER M4 ;
        RECT  0 9.936 0.084 9.96 ;
    END
  END i_d[46]
  PIN i_d[47]
    DIRECTION INPUT ;
    USE SIGNAL ;
    PORT
      LAYER M4 ;
        RECT  0 10.032 0.084 10.056 ;
    END
  END i_d[47]
  PIN i_d[48]
    DIRECTION INPUT ;
    USE SIGNAL ;
    PORT
      LAYER M4 ;
        RECT  0 10.128 0.084 10.152 ;
    END
  END i_d[48]
  PIN i_d[49]
    DIRECTION INPUT ;
    USE SIGNAL ;
    PORT
      LAYER M4 ;
        RECT  0 10.224 0.084 10.248 ;
    END
  END i_d[49]
  PIN i_d[4]
    DIRECTION INPUT ;
    USE SIGNAL ;
    PORT
      LAYER M4 ;
        RECT  0 28.176 0.084 28.2 ;
    END
  END i_d[4]
  PIN i_d[50]
    DIRECTION INPUT ;
    USE SIGNAL ;
    PORT
      LAYER M4 ;
        RECT  0 10.32 0.084 10.344 ;
    END
  END i_d[50]
  PIN i_d[51]
    DIRECTION INPUT ;
    USE SIGNAL ;
    PORT
      LAYER M4 ;
        RECT  0 10.416 0.084 10.44 ;
    END
  END i_d[51]
  PIN i_d[52]
    DIRECTION INPUT ;
    USE SIGNAL ;
    PORT
      LAYER M4 ;
        RECT  0 10.512 0.084 10.536 ;
    END
  END i_d[52]
  PIN i_d[53]
    DIRECTION INPUT ;
    USE SIGNAL ;
    PORT
      LAYER M4 ;
        RECT  0 10.608 0.084 10.632 ;
    END
  END i_d[53]
  PIN i_d[54]
    DIRECTION INPUT ;
    USE SIGNAL ;
    PORT
      LAYER M4 ;
        RECT  0 10.704 0.084 10.728 ;
    END
  END i_d[54]
  PIN i_d[55]
    DIRECTION INPUT ;
    USE SIGNAL ;
    PORT
      LAYER M4 ;
        RECT  0 10.8 0.084 10.824 ;
    END
  END i_d[55]
  PIN i_d[56]
    DIRECTION INPUT ;
    USE SIGNAL ;
    PORT
      LAYER M4 ;
        RECT  0 10.896 0.084 10.92 ;
    END
  END i_d[56]
  PIN i_d[57]
    DIRECTION INPUT ;
    USE SIGNAL ;
    PORT
      LAYER M4 ;
        RECT  0 10.992 0.084 11.016 ;
    END
  END i_d[57]
  PIN i_d[58]
    DIRECTION INPUT ;
    USE SIGNAL ;
    PORT
      LAYER M4 ;
        RECT  0 11.088 0.084 11.112 ;
    END
  END i_d[58]
  PIN i_d[59]
    DIRECTION INPUT ;
    USE SIGNAL ;
    PORT
      LAYER M4 ;
        RECT  0 11.184 0.084 11.208 ;
    END
  END i_d[59]
  PIN i_d[5]
    DIRECTION INPUT ;
    USE SIGNAL ;
    PORT
      LAYER M4 ;
        RECT  0 28.272 0.084 28.296 ;
    END
  END i_d[5]
  PIN i_d[60]
    DIRECTION INPUT ;
    USE SIGNAL ;
    PORT
      LAYER M4 ;
        RECT  0 11.28 0.084 11.304 ;
    END
  END i_d[60]
  PIN i_d[61]
    DIRECTION INPUT ;
    USE SIGNAL ;
    PORT
      LAYER M4 ;
        RECT  0 11.376 0.084 11.4 ;
    END
  END i_d[61]
  PIN i_d[62]
    DIRECTION INPUT ;
    USE SIGNAL ;
    PORT
      LAYER M4 ;
        RECT  0 33.744 0.084 33.768 ;
    END
  END i_d[62]
  PIN i_d[63]
    DIRECTION INPUT ;
    USE SIGNAL ;
    PORT
      LAYER M4 ;
        RECT  0 33.84 0.084 33.864 ;
    END
  END i_d[63]
  PIN i_d[64]
    DIRECTION INPUT ;
    USE SIGNAL ;
    PORT
      LAYER M4 ;
        RECT  0 33.936 0.084 33.96 ;
    END
  END i_d[64]
  PIN i_d[65]
    DIRECTION INPUT ;
    USE SIGNAL ;
    PORT
      LAYER M4 ;
        RECT  0 34.032 0.084 34.056 ;
    END
  END i_d[65]
  PIN i_d[66]
    DIRECTION INPUT ;
    USE SIGNAL ;
    PORT
      LAYER M4 ;
        RECT  0 34.128 0.084 34.152 ;
    END
  END i_d[66]
  PIN i_d[67]
    DIRECTION INPUT ;
    USE SIGNAL ;
    PORT
      LAYER M4 ;
        RECT  0 34.224 0.084 34.248 ;
    END
  END i_d[67]
  PIN i_d[68]
    DIRECTION INPUT ;
    USE SIGNAL ;
    PORT
      LAYER M4 ;
        RECT  0 34.32 0.084 34.344 ;
    END
  END i_d[68]
  PIN i_d[69]
    DIRECTION INPUT ;
    USE SIGNAL ;
    PORT
      LAYER M4 ;
        RECT  0 34.416 0.084 34.44 ;
    END
  END i_d[69]
  PIN i_d[6]
    DIRECTION INPUT ;
    USE SIGNAL ;
    PORT
      LAYER M4 ;
        RECT  0 28.368 0.084 28.392 ;
    END
  END i_d[6]
  PIN i_d[70]
    DIRECTION INPUT ;
    USE SIGNAL ;
    PORT
      LAYER M4 ;
        RECT  0 34.512 0.084 34.536 ;
    END
  END i_d[70]
  PIN i_d[71]
    DIRECTION INPUT ;
    USE SIGNAL ;
    PORT
      LAYER M4 ;
        RECT  0 34.608 0.084 34.632 ;
    END
  END i_d[71]
  PIN i_d[72]
    DIRECTION INPUT ;
    USE SIGNAL ;
    PORT
      LAYER M4 ;
        RECT  0 34.704 0.084 34.728 ;
    END
  END i_d[72]
  PIN i_d[73]
    DIRECTION INPUT ;
    USE SIGNAL ;
    PORT
      LAYER M4 ;
        RECT  0 34.8 0.084 34.824 ;
    END
  END i_d[73]
  PIN i_d[74]
    DIRECTION INPUT ;
    USE SIGNAL ;
    PORT
      LAYER M4 ;
        RECT  0 34.896 0.084 34.92 ;
    END
  END i_d[74]
  PIN i_d[75]
    DIRECTION INPUT ;
    USE SIGNAL ;
    PORT
      LAYER M4 ;
        RECT  0 34.992 0.084 35.016 ;
    END
  END i_d[75]
  PIN i_d[76]
    DIRECTION INPUT ;
    USE SIGNAL ;
    PORT
      LAYER M4 ;
        RECT  0 35.088 0.084 35.112 ;
    END
  END i_d[76]
  PIN i_d[77]
    DIRECTION INPUT ;
    USE SIGNAL ;
    PORT
      LAYER M4 ;
        RECT  0 35.184 0.084 35.208 ;
    END
  END i_d[77]
  PIN i_d[78]
    DIRECTION INPUT ;
    USE SIGNAL ;
    PORT
      LAYER M4 ;
        RECT  0 35.28 0.084 35.304 ;
    END
  END i_d[78]
  PIN i_d[79]
    DIRECTION INPUT ;
    USE SIGNAL ;
    PORT
      LAYER M4 ;
        RECT  0 35.376 0.084 35.4 ;
    END
  END i_d[79]
  PIN i_d[7]
    DIRECTION INPUT ;
    USE SIGNAL ;
    PORT
      LAYER M4 ;
        RECT  0 28.464 0.084 28.488 ;
    END
  END i_d[7]
  PIN i_d[80]
    DIRECTION INPUT ;
    USE SIGNAL ;
    PORT
      LAYER M4 ;
        RECT  0 35.472 0.084 35.496 ;
    END
  END i_d[80]
  PIN i_d[81]
    DIRECTION INPUT ;
    USE SIGNAL ;
    PORT
      LAYER M4 ;
        RECT  0 35.568 0.084 35.592 ;
    END
  END i_d[81]
  PIN i_d[82]
    DIRECTION INPUT ;
    USE SIGNAL ;
    PORT
      LAYER M4 ;
        RECT  0 35.664 0.084 35.688 ;
    END
  END i_d[82]
  PIN i_d[83]
    DIRECTION INPUT ;
    USE SIGNAL ;
    PORT
      LAYER M4 ;
        RECT  0 35.76 0.084 35.784 ;
    END
  END i_d[83]
  PIN i_d[84]
    DIRECTION INPUT ;
    USE SIGNAL ;
    PORT
      LAYER M4 ;
        RECT  0 35.856 0.084 35.88 ;
    END
  END i_d[84]
  PIN i_d[85]
    DIRECTION INPUT ;
    USE SIGNAL ;
    PORT
      LAYER M4 ;
        RECT  0 35.952 0.084 35.976 ;
    END
  END i_d[85]
  PIN i_d[86]
    DIRECTION INPUT ;
    USE SIGNAL ;
    PORT
      LAYER M4 ;
        RECT  0 36.048 0.084 36.072 ;
    END
  END i_d[86]
  PIN i_d[87]
    DIRECTION INPUT ;
    USE SIGNAL ;
    PORT
      LAYER M4 ;
        RECT  0 36.144 0.084 36.168 ;
    END
  END i_d[87]
  PIN i_d[88]
    DIRECTION INPUT ;
    USE SIGNAL ;
    PORT
      LAYER M4 ;
        RECT  0 36.24 0.084 36.264 ;
    END
  END i_d[88]
  PIN i_d[89]
    DIRECTION INPUT ;
    USE SIGNAL ;
    PORT
      LAYER M4 ;
        RECT  0 36.336 0.084 36.36 ;
    END
  END i_d[89]
  PIN i_d[8]
    DIRECTION INPUT ;
    USE SIGNAL ;
    PORT
      LAYER M4 ;
        RECT  0 28.56 0.084 28.584 ;
    END
  END i_d[8]
  PIN i_d[90]
    DIRECTION INPUT ;
    USE SIGNAL ;
    PORT
      LAYER M4 ;
        RECT  0 36.432 0.084 36.456 ;
    END
  END i_d[90]
  PIN i_d[91]
    DIRECTION INPUT ;
    USE SIGNAL ;
    PORT
      LAYER M4 ;
        RECT  0 36.528 0.084 36.552 ;
    END
  END i_d[91]
  PIN i_d[92]
    DIRECTION INPUT ;
    USE SIGNAL ;
    PORT
      LAYER M4 ;
        RECT  0 36.624 0.084 36.648 ;
    END
  END i_d[92]
  PIN i_d[93]
    DIRECTION INPUT ;
    USE SIGNAL ;
    PORT
      LAYER M4 ;
        RECT  0 36.72 0.084 36.744 ;
    END
  END i_d[93]
  PIN i_d[94]
    DIRECTION INPUT ;
    USE SIGNAL ;
    PORT
      LAYER M4 ;
        RECT  0 69.072 0.084 69.096 ;
    END
  END i_d[94]
  PIN i_d[95]
    DIRECTION INPUT ;
    USE SIGNAL ;
    PORT
      LAYER M4 ;
        RECT  0 69.168 0.084 69.192 ;
    END
  END i_d[95]
  PIN i_d[96]
    DIRECTION INPUT ;
    USE SIGNAL ;
    PORT
      LAYER M4 ;
        RECT  0 69.264 0.084 69.288 ;
    END
  END i_d[96]
  PIN i_d[97]
    DIRECTION INPUT ;
    USE SIGNAL ;
    PORT
      LAYER M4 ;
        RECT  0 69.36 0.084 69.384 ;
    END
  END i_d[97]
  PIN i_d[98]
    DIRECTION INPUT ;
    USE SIGNAL ;
    PORT
      LAYER M4 ;
        RECT  0 69.456 0.084 69.48 ;
    END
  END i_d[98]
  PIN i_d[99]
    DIRECTION INPUT ;
    USE SIGNAL ;
    PORT
      LAYER M4 ;
        RECT  0 69.552 0.084 69.576 ;
    END
  END i_d[99]
  PIN i_d[9]
    DIRECTION INPUT ;
    USE SIGNAL ;
    PORT
      LAYER M4 ;
        RECT  0 28.656 0.084 28.68 ;
    END
  END i_d[9]
  PIN i_v[0]
    DIRECTION INPUT ;
    USE SIGNAL ;
    PORT
      LAYER M4 ;
        RECT  0 33.552 0.084 33.576 ;
    END
  END i_v[0]
  PIN i_v[1]
    DIRECTION INPUT ;
    USE SIGNAL ;
    PORT
      LAYER M4 ;
        RECT  0 33.648 0.084 33.672 ;
    END
  END i_v[1]
  PIN o_cr[0]
    DIRECTION INPUT ;
    USE SIGNAL ;
    PORT
      LAYER M4 ;
        RECT  47.436 26.064 47.52 26.088 ;
    END
  END o_cr[0]
  PIN o_cr[1]
    DIRECTION INPUT ;
    USE SIGNAL ;
    PORT
      LAYER M4 ;
        RECT  47.436 26.16 47.52 26.184 ;
    END
  END o_cr[1]
  PIN o_d[0]
    DIRECTION OUTPUT ;
    USE SIGNAL ;
    PORT
      LAYER M4 ;
        RECT  47.436 26.256 47.52 26.28 ;
    END
  END o_d[0]
  PIN o_d[100]
    DIRECTION OUTPUT ;
    USE SIGNAL ;
    PORT
      LAYER M4 ;
        RECT  47.436 78.096 47.52 78.12 ;
    END
  END o_d[100]
  PIN o_d[101]
    DIRECTION OUTPUT ;
    USE SIGNAL ;
    PORT
      LAYER M4 ;
        RECT  47.436 78.192 47.52 78.216 ;
    END
  END o_d[101]
  PIN o_d[102]
    DIRECTION OUTPUT ;
    USE SIGNAL ;
    PORT
      LAYER M4 ;
        RECT  47.436 78.288 47.52 78.312 ;
    END
  END o_d[102]
  PIN o_d[103]
    DIRECTION OUTPUT ;
    USE SIGNAL ;
    PORT
      LAYER M4 ;
        RECT  47.436 78.384 47.52 78.408 ;
    END
  END o_d[103]
  PIN o_d[104]
    DIRECTION OUTPUT ;
    USE SIGNAL ;
    PORT
      LAYER M4 ;
        RECT  47.436 78.48 47.52 78.504 ;
    END
  END o_d[104]
  PIN o_d[105]
    DIRECTION OUTPUT ;
    USE SIGNAL ;
    PORT
      LAYER M4 ;
        RECT  47.436 78.576 47.52 78.6 ;
    END
  END o_d[105]
  PIN o_d[106]
    DIRECTION OUTPUT ;
    USE SIGNAL ;
    PORT
      LAYER M4 ;
        RECT  47.436 78.672 47.52 78.696 ;
    END
  END o_d[106]
  PIN o_d[107]
    DIRECTION OUTPUT ;
    USE SIGNAL ;
    PORT
      LAYER M4 ;
        RECT  47.436 78.768 47.52 78.792 ;
    END
  END o_d[107]
  PIN o_d[108]
    DIRECTION OUTPUT ;
    USE SIGNAL ;
    PORT
      LAYER M4 ;
        RECT  47.436 78.864 47.52 78.888 ;
    END
  END o_d[108]
  PIN o_d[109]
    DIRECTION OUTPUT ;
    USE SIGNAL ;
    PORT
      LAYER M4 ;
        RECT  47.436 78.96 47.52 78.984 ;
    END
  END o_d[109]
  PIN o_d[10]
    DIRECTION OUTPUT ;
    USE SIGNAL ;
    PORT
      LAYER M4 ;
        RECT  47.436 27.216 47.52 27.24 ;
    END
  END o_d[10]
  PIN o_d[110]
    DIRECTION OUTPUT ;
    USE SIGNAL ;
    PORT
      LAYER M4 ;
        RECT  47.436 79.056 47.52 79.08 ;
    END
  END o_d[110]
  PIN o_d[111]
    DIRECTION OUTPUT ;
    USE SIGNAL ;
    PORT
      LAYER M4 ;
        RECT  47.436 79.152 47.52 79.176 ;
    END
  END o_d[111]
  PIN o_d[112]
    DIRECTION OUTPUT ;
    USE SIGNAL ;
    PORT
      LAYER M4 ;
        RECT  47.436 79.248 47.52 79.272 ;
    END
  END o_d[112]
  PIN o_d[113]
    DIRECTION OUTPUT ;
    USE SIGNAL ;
    PORT
      LAYER M4 ;
        RECT  47.436 79.344 47.52 79.368 ;
    END
  END o_d[113]
  PIN o_d[114]
    DIRECTION OUTPUT ;
    USE SIGNAL ;
    PORT
      LAYER M4 ;
        RECT  47.436 79.44 47.52 79.464 ;
    END
  END o_d[114]
  PIN o_d[115]
    DIRECTION OUTPUT ;
    USE SIGNAL ;
    PORT
      LAYER M4 ;
        RECT  47.436 79.536 47.52 79.56 ;
    END
  END o_d[115]
  PIN o_d[116]
    DIRECTION OUTPUT ;
    USE SIGNAL ;
    PORT
      LAYER M4 ;
        RECT  47.436 79.632 47.52 79.656 ;
    END
  END o_d[116]
  PIN o_d[117]
    DIRECTION OUTPUT ;
    USE SIGNAL ;
    PORT
      LAYER M4 ;
        RECT  47.436 79.728 47.52 79.752 ;
    END
  END o_d[117]
  PIN o_d[118]
    DIRECTION OUTPUT ;
    USE SIGNAL ;
    PORT
      LAYER M4 ;
        RECT  47.436 79.824 47.52 79.848 ;
    END
  END o_d[118]
  PIN o_d[119]
    DIRECTION OUTPUT ;
    USE SIGNAL ;
    PORT
      LAYER M4 ;
        RECT  47.436 79.92 47.52 79.944 ;
    END
  END o_d[119]
  PIN o_d[11]
    DIRECTION OUTPUT ;
    USE SIGNAL ;
    PORT
      LAYER M4 ;
        RECT  47.436 27.312 47.52 27.336 ;
    END
  END o_d[11]
  PIN o_d[120]
    DIRECTION OUTPUT ;
    USE SIGNAL ;
    PORT
      LAYER M4 ;
        RECT  47.436 80.016 47.52 80.04 ;
    END
  END o_d[120]
  PIN o_d[121]
    DIRECTION OUTPUT ;
    USE SIGNAL ;
    PORT
      LAYER M4 ;
        RECT  47.436 80.112 47.52 80.136 ;
    END
  END o_d[121]
  PIN o_d[122]
    DIRECTION OUTPUT ;
    USE SIGNAL ;
    PORT
      LAYER M4 ;
        RECT  47.436 80.208 47.52 80.232 ;
    END
  END o_d[122]
  PIN o_d[123]
    DIRECTION OUTPUT ;
    USE SIGNAL ;
    PORT
      LAYER M4 ;
        RECT  47.436 80.304 47.52 80.328 ;
    END
  END o_d[123]
  PIN o_d[124]
    DIRECTION OUTPUT ;
    USE SIGNAL ;
    PORT
      LAYER M4 ;
        RECT  47.436 80.4 47.52 80.424 ;
    END
  END o_d[124]
  PIN o_d[125]
    DIRECTION OUTPUT ;
    USE SIGNAL ;
    PORT
      LAYER M4 ;
        RECT  47.436 80.496 47.52 80.52 ;
    END
  END o_d[125]
  PIN o_d[126]
    DIRECTION OUTPUT ;
    USE SIGNAL ;
    PORT
      LAYER M4 ;
        RECT  47.436 54.48 47.52 54.504 ;
    END
  END o_d[126]
  PIN o_d[127]
    DIRECTION OUTPUT ;
    USE SIGNAL ;
    PORT
      LAYER M4 ;
        RECT  47.436 54.576 47.52 54.6 ;
    END
  END o_d[127]
  PIN o_d[128]
    DIRECTION OUTPUT ;
    USE SIGNAL ;
    PORT
      LAYER M4 ;
        RECT  47.436 54.672 47.52 54.696 ;
    END
  END o_d[128]
  PIN o_d[129]
    DIRECTION OUTPUT ;
    USE SIGNAL ;
    PORT
      LAYER M4 ;
        RECT  47.436 54.768 47.52 54.792 ;
    END
  END o_d[129]
  PIN o_d[12]
    DIRECTION OUTPUT ;
    USE SIGNAL ;
    PORT
      LAYER M4 ;
        RECT  47.436 27.408 47.52 27.432 ;
    END
  END o_d[12]
  PIN o_d[130]
    DIRECTION OUTPUT ;
    USE SIGNAL ;
    PORT
      LAYER M4 ;
        RECT  47.436 54.864 47.52 54.888 ;
    END
  END o_d[130]
  PIN o_d[131]
    DIRECTION OUTPUT ;
    USE SIGNAL ;
    PORT
      LAYER M4 ;
        RECT  47.436 54.96 47.52 54.984 ;
    END
  END o_d[131]
  PIN o_d[132]
    DIRECTION OUTPUT ;
    USE SIGNAL ;
    PORT
      LAYER M4 ;
        RECT  47.436 55.056 47.52 55.08 ;
    END
  END o_d[132]
  PIN o_d[133]
    DIRECTION OUTPUT ;
    USE SIGNAL ;
    PORT
      LAYER M4 ;
        RECT  47.436 55.152 47.52 55.176 ;
    END
  END o_d[133]
  PIN o_d[134]
    DIRECTION OUTPUT ;
    USE SIGNAL ;
    PORT
      LAYER M4 ;
        RECT  47.436 55.248 47.52 55.272 ;
    END
  END o_d[134]
  PIN o_d[135]
    DIRECTION OUTPUT ;
    USE SIGNAL ;
    PORT
      LAYER M4 ;
        RECT  47.436 55.344 47.52 55.368 ;
    END
  END o_d[135]
  PIN o_d[136]
    DIRECTION OUTPUT ;
    USE SIGNAL ;
    PORT
      LAYER M4 ;
        RECT  47.436 55.44 47.52 55.464 ;
    END
  END o_d[136]
  PIN o_d[137]
    DIRECTION OUTPUT ;
    USE SIGNAL ;
    PORT
      LAYER M4 ;
        RECT  47.436 55.536 47.52 55.56 ;
    END
  END o_d[137]
  PIN o_d[138]
    DIRECTION OUTPUT ;
    USE SIGNAL ;
    PORT
      LAYER M4 ;
        RECT  47.436 55.632 47.52 55.656 ;
    END
  END o_d[138]
  PIN o_d[139]
    DIRECTION OUTPUT ;
    USE SIGNAL ;
    PORT
      LAYER M4 ;
        RECT  47.436 55.728 47.52 55.752 ;
    END
  END o_d[139]
  PIN o_d[13]
    DIRECTION OUTPUT ;
    USE SIGNAL ;
    PORT
      LAYER M4 ;
        RECT  47.436 27.504 47.52 27.528 ;
    END
  END o_d[13]
  PIN o_d[140]
    DIRECTION OUTPUT ;
    USE SIGNAL ;
    PORT
      LAYER M4 ;
        RECT  47.436 55.824 47.52 55.848 ;
    END
  END o_d[140]
  PIN o_d[141]
    DIRECTION OUTPUT ;
    USE SIGNAL ;
    PORT
      LAYER M4 ;
        RECT  47.436 55.92 47.52 55.944 ;
    END
  END o_d[141]
  PIN o_d[142]
    DIRECTION OUTPUT ;
    USE SIGNAL ;
    PORT
      LAYER M4 ;
        RECT  47.436 56.016 47.52 56.04 ;
    END
  END o_d[142]
  PIN o_d[143]
    DIRECTION OUTPUT ;
    USE SIGNAL ;
    PORT
      LAYER M4 ;
        RECT  47.436 56.112 47.52 56.136 ;
    END
  END o_d[143]
  PIN o_d[144]
    DIRECTION OUTPUT ;
    USE SIGNAL ;
    PORT
      LAYER M4 ;
        RECT  47.436 56.208 47.52 56.232 ;
    END
  END o_d[144]
  PIN o_d[145]
    DIRECTION OUTPUT ;
    USE SIGNAL ;
    PORT
      LAYER M4 ;
        RECT  47.436 56.304 47.52 56.328 ;
    END
  END o_d[145]
  PIN o_d[146]
    DIRECTION OUTPUT ;
    USE SIGNAL ;
    PORT
      LAYER M4 ;
        RECT  47.436 56.4 47.52 56.424 ;
    END
  END o_d[146]
  PIN o_d[147]
    DIRECTION OUTPUT ;
    USE SIGNAL ;
    PORT
      LAYER M4 ;
        RECT  47.436 56.496 47.52 56.52 ;
    END
  END o_d[147]
  PIN o_d[148]
    DIRECTION OUTPUT ;
    USE SIGNAL ;
    PORT
      LAYER M4 ;
        RECT  47.436 56.592 47.52 56.616 ;
    END
  END o_d[148]
  PIN o_d[149]
    DIRECTION OUTPUT ;
    USE SIGNAL ;
    PORT
      LAYER M4 ;
        RECT  47.436 56.688 47.52 56.712 ;
    END
  END o_d[149]
  PIN o_d[14]
    DIRECTION OUTPUT ;
    USE SIGNAL ;
    PORT
      LAYER M4 ;
        RECT  47.436 27.6 47.52 27.624 ;
    END
  END o_d[14]
  PIN o_d[150]
    DIRECTION OUTPUT ;
    USE SIGNAL ;
    PORT
      LAYER M4 ;
        RECT  47.436 56.784 47.52 56.808 ;
    END
  END o_d[150]
  PIN o_d[151]
    DIRECTION OUTPUT ;
    USE SIGNAL ;
    PORT
      LAYER M4 ;
        RECT  47.436 56.88 47.52 56.904 ;
    END
  END o_d[151]
  PIN o_d[152]
    DIRECTION OUTPUT ;
    USE SIGNAL ;
    PORT
      LAYER M4 ;
        RECT  47.436 56.976 47.52 57 ;
    END
  END o_d[152]
  PIN o_d[153]
    DIRECTION OUTPUT ;
    USE SIGNAL ;
    PORT
      LAYER M4 ;
        RECT  47.436 57.072 47.52 57.096 ;
    END
  END o_d[153]
  PIN o_d[154]
    DIRECTION OUTPUT ;
    USE SIGNAL ;
    PORT
      LAYER M4 ;
        RECT  47.436 57.168 47.52 57.192 ;
    END
  END o_d[154]
  PIN o_d[155]
    DIRECTION OUTPUT ;
    USE SIGNAL ;
    PORT
      LAYER M4 ;
        RECT  47.436 57.264 47.52 57.288 ;
    END
  END o_d[155]
  PIN o_d[156]
    DIRECTION OUTPUT ;
    USE SIGNAL ;
    PORT
      LAYER M4 ;
        RECT  47.436 57.36 47.52 57.384 ;
    END
  END o_d[156]
  PIN o_d[157]
    DIRECTION OUTPUT ;
    USE SIGNAL ;
    PORT
      LAYER M4 ;
        RECT  47.436 57.456 47.52 57.48 ;
    END
  END o_d[157]
  PIN o_d[158]
    DIRECTION OUTPUT ;
    USE SIGNAL ;
    PORT
      LAYER M4 ;
        RECT  47.436 51.408 47.52 51.432 ;
    END
  END o_d[158]
  PIN o_d[159]
    DIRECTION OUTPUT ;
    USE SIGNAL ;
    PORT
      LAYER M4 ;
        RECT  47.436 51.504 47.52 51.528 ;
    END
  END o_d[159]
  PIN o_d[15]
    DIRECTION OUTPUT ;
    USE SIGNAL ;
    PORT
      LAYER M4 ;
        RECT  47.436 27.696 47.52 27.72 ;
    END
  END o_d[15]
  PIN o_d[160]
    DIRECTION OUTPUT ;
    USE SIGNAL ;
    PORT
      LAYER M4 ;
        RECT  47.436 51.6 47.52 51.624 ;
    END
  END o_d[160]
  PIN o_d[161]
    DIRECTION OUTPUT ;
    USE SIGNAL ;
    PORT
      LAYER M4 ;
        RECT  47.436 51.696 47.52 51.72 ;
    END
  END o_d[161]
  PIN o_d[162]
    DIRECTION OUTPUT ;
    USE SIGNAL ;
    PORT
      LAYER M4 ;
        RECT  47.436 51.792 47.52 51.816 ;
    END
  END o_d[162]
  PIN o_d[163]
    DIRECTION OUTPUT ;
    USE SIGNAL ;
    PORT
      LAYER M4 ;
        RECT  47.436 51.888 47.52 51.912 ;
    END
  END o_d[163]
  PIN o_d[164]
    DIRECTION OUTPUT ;
    USE SIGNAL ;
    PORT
      LAYER M4 ;
        RECT  47.436 51.984 47.52 52.008 ;
    END
  END o_d[164]
  PIN o_d[165]
    DIRECTION OUTPUT ;
    USE SIGNAL ;
    PORT
      LAYER M4 ;
        RECT  47.436 52.08 47.52 52.104 ;
    END
  END o_d[165]
  PIN o_d[166]
    DIRECTION OUTPUT ;
    USE SIGNAL ;
    PORT
      LAYER M4 ;
        RECT  47.436 52.176 47.52 52.2 ;
    END
  END o_d[166]
  PIN o_d[167]
    DIRECTION OUTPUT ;
    USE SIGNAL ;
    PORT
      LAYER M4 ;
        RECT  47.436 52.272 47.52 52.296 ;
    END
  END o_d[167]
  PIN o_d[168]
    DIRECTION OUTPUT ;
    USE SIGNAL ;
    PORT
      LAYER M4 ;
        RECT  47.436 52.368 47.52 52.392 ;
    END
  END o_d[168]
  PIN o_d[169]
    DIRECTION OUTPUT ;
    USE SIGNAL ;
    PORT
      LAYER M4 ;
        RECT  47.436 52.464 47.52 52.488 ;
    END
  END o_d[169]
  PIN o_d[16]
    DIRECTION OUTPUT ;
    USE SIGNAL ;
    PORT
      LAYER M4 ;
        RECT  47.436 27.792 47.52 27.816 ;
    END
  END o_d[16]
  PIN o_d[170]
    DIRECTION OUTPUT ;
    USE SIGNAL ;
    PORT
      LAYER M4 ;
        RECT  47.436 52.56 47.52 52.584 ;
    END
  END o_d[170]
  PIN o_d[171]
    DIRECTION OUTPUT ;
    USE SIGNAL ;
    PORT
      LAYER M4 ;
        RECT  47.436 52.656 47.52 52.68 ;
    END
  END o_d[171]
  PIN o_d[172]
    DIRECTION OUTPUT ;
    USE SIGNAL ;
    PORT
      LAYER M4 ;
        RECT  47.436 52.752 47.52 52.776 ;
    END
  END o_d[172]
  PIN o_d[173]
    DIRECTION OUTPUT ;
    USE SIGNAL ;
    PORT
      LAYER M4 ;
        RECT  47.436 52.848 47.52 52.872 ;
    END
  END o_d[173]
  PIN o_d[174]
    DIRECTION OUTPUT ;
    USE SIGNAL ;
    PORT
      LAYER M4 ;
        RECT  47.436 52.944 47.52 52.968 ;
    END
  END o_d[174]
  PIN o_d[175]
    DIRECTION OUTPUT ;
    USE SIGNAL ;
    PORT
      LAYER M4 ;
        RECT  47.436 53.04 47.52 53.064 ;
    END
  END o_d[175]
  PIN o_d[176]
    DIRECTION OUTPUT ;
    USE SIGNAL ;
    PORT
      LAYER M4 ;
        RECT  47.436 53.136 47.52 53.16 ;
    END
  END o_d[176]
  PIN o_d[177]
    DIRECTION OUTPUT ;
    USE SIGNAL ;
    PORT
      LAYER M4 ;
        RECT  47.436 53.232 47.52 53.256 ;
    END
  END o_d[177]
  PIN o_d[178]
    DIRECTION OUTPUT ;
    USE SIGNAL ;
    PORT
      LAYER M4 ;
        RECT  47.436 53.328 47.52 53.352 ;
    END
  END o_d[178]
  PIN o_d[179]
    DIRECTION OUTPUT ;
    USE SIGNAL ;
    PORT
      LAYER M4 ;
        RECT  47.436 53.424 47.52 53.448 ;
    END
  END o_d[179]
  PIN o_d[17]
    DIRECTION OUTPUT ;
    USE SIGNAL ;
    PORT
      LAYER M4 ;
        RECT  47.436 27.888 47.52 27.912 ;
    END
  END o_d[17]
  PIN o_d[180]
    DIRECTION OUTPUT ;
    USE SIGNAL ;
    PORT
      LAYER M4 ;
        RECT  47.436 53.52 47.52 53.544 ;
    END
  END o_d[180]
  PIN o_d[181]
    DIRECTION OUTPUT ;
    USE SIGNAL ;
    PORT
      LAYER M4 ;
        RECT  47.436 53.616 47.52 53.64 ;
    END
  END o_d[181]
  PIN o_d[182]
    DIRECTION OUTPUT ;
    USE SIGNAL ;
    PORT
      LAYER M4 ;
        RECT  47.436 53.712 47.52 53.736 ;
    END
  END o_d[182]
  PIN o_d[183]
    DIRECTION OUTPUT ;
    USE SIGNAL ;
    PORT
      LAYER M4 ;
        RECT  47.436 53.808 47.52 53.832 ;
    END
  END o_d[183]
  PIN o_d[184]
    DIRECTION OUTPUT ;
    USE SIGNAL ;
    PORT
      LAYER M4 ;
        RECT  47.436 53.904 47.52 53.928 ;
    END
  END o_d[184]
  PIN o_d[185]
    DIRECTION OUTPUT ;
    USE SIGNAL ;
    PORT
      LAYER M4 ;
        RECT  47.436 54 47.52 54.024 ;
    END
  END o_d[185]
  PIN o_d[186]
    DIRECTION OUTPUT ;
    USE SIGNAL ;
    PORT
      LAYER M4 ;
        RECT  47.436 54.096 47.52 54.12 ;
    END
  END o_d[186]
  PIN o_d[187]
    DIRECTION OUTPUT ;
    USE SIGNAL ;
    PORT
      LAYER M4 ;
        RECT  47.436 54.192 47.52 54.216 ;
    END
  END o_d[187]
  PIN o_d[188]
    DIRECTION OUTPUT ;
    USE SIGNAL ;
    PORT
      LAYER M4 ;
        RECT  47.436 54.288 47.52 54.312 ;
    END
  END o_d[188]
  PIN o_d[189]
    DIRECTION OUTPUT ;
    USE SIGNAL ;
    PORT
      LAYER M4 ;
        RECT  47.436 54.384 47.52 54.408 ;
    END
  END o_d[189]
  PIN o_d[18]
    DIRECTION OUTPUT ;
    USE SIGNAL ;
    PORT
      LAYER M4 ;
        RECT  47.436 27.984 47.52 28.008 ;
    END
  END o_d[18]
  PIN o_d[190]
    DIRECTION OUTPUT ;
    USE SIGNAL ;
    PORT
      LAYER M4 ;
        RECT  47.436 67.536 47.52 67.56 ;
    END
  END o_d[190]
  PIN o_d[191]
    DIRECTION OUTPUT ;
    USE SIGNAL ;
    PORT
      LAYER M4 ;
        RECT  47.436 67.632 47.52 67.656 ;
    END
  END o_d[191]
  PIN o_d[192]
    DIRECTION OUTPUT ;
    USE SIGNAL ;
    PORT
      LAYER M4 ;
        RECT  47.436 67.728 47.52 67.752 ;
    END
  END o_d[192]
  PIN o_d[193]
    DIRECTION OUTPUT ;
    USE SIGNAL ;
    PORT
      LAYER M4 ;
        RECT  47.436 67.824 47.52 67.848 ;
    END
  END o_d[193]
  PIN o_d[194]
    DIRECTION OUTPUT ;
    USE SIGNAL ;
    PORT
      LAYER M4 ;
        RECT  47.436 67.92 47.52 67.944 ;
    END
  END o_d[194]
  PIN o_d[195]
    DIRECTION OUTPUT ;
    USE SIGNAL ;
    PORT
      LAYER M4 ;
        RECT  47.436 68.016 47.52 68.04 ;
    END
  END o_d[195]
  PIN o_d[196]
    DIRECTION OUTPUT ;
    USE SIGNAL ;
    PORT
      LAYER M4 ;
        RECT  47.436 68.112 47.52 68.136 ;
    END
  END o_d[196]
  PIN o_d[197]
    DIRECTION OUTPUT ;
    USE SIGNAL ;
    PORT
      LAYER M4 ;
        RECT  47.436 68.208 47.52 68.232 ;
    END
  END o_d[197]
  PIN o_d[198]
    DIRECTION OUTPUT ;
    USE SIGNAL ;
    PORT
      LAYER M4 ;
        RECT  47.436 68.304 47.52 68.328 ;
    END
  END o_d[198]
  PIN o_d[199]
    DIRECTION OUTPUT ;
    USE SIGNAL ;
    PORT
      LAYER M4 ;
        RECT  47.436 68.4 47.52 68.424 ;
    END
  END o_d[199]
  PIN o_d[19]
    DIRECTION OUTPUT ;
    USE SIGNAL ;
    PORT
      LAYER M4 ;
        RECT  47.436 28.08 47.52 28.104 ;
    END
  END o_d[19]
  PIN o_d[1]
    DIRECTION OUTPUT ;
    USE SIGNAL ;
    PORT
      LAYER M4 ;
        RECT  47.436 26.352 47.52 26.376 ;
    END
  END o_d[1]
  PIN o_d[200]
    DIRECTION OUTPUT ;
    USE SIGNAL ;
    PORT
      LAYER M4 ;
        RECT  47.436 68.496 47.52 68.52 ;
    END
  END o_d[200]
  PIN o_d[201]
    DIRECTION OUTPUT ;
    USE SIGNAL ;
    PORT
      LAYER M4 ;
        RECT  47.436 68.592 47.52 68.616 ;
    END
  END o_d[201]
  PIN o_d[202]
    DIRECTION OUTPUT ;
    USE SIGNAL ;
    PORT
      LAYER M4 ;
        RECT  47.436 68.688 47.52 68.712 ;
    END
  END o_d[202]
  PIN o_d[203]
    DIRECTION OUTPUT ;
    USE SIGNAL ;
    PORT
      LAYER M4 ;
        RECT  47.436 68.784 47.52 68.808 ;
    END
  END o_d[203]
  PIN o_d[204]
    DIRECTION OUTPUT ;
    USE SIGNAL ;
    PORT
      LAYER M4 ;
        RECT  47.436 68.88 47.52 68.904 ;
    END
  END o_d[204]
  PIN o_d[205]
    DIRECTION OUTPUT ;
    USE SIGNAL ;
    PORT
      LAYER M4 ;
        RECT  47.436 68.976 47.52 69 ;
    END
  END o_d[205]
  PIN o_d[206]
    DIRECTION OUTPUT ;
    USE SIGNAL ;
    PORT
      LAYER M4 ;
        RECT  47.436 69.072 47.52 69.096 ;
    END
  END o_d[206]
  PIN o_d[207]
    DIRECTION OUTPUT ;
    USE SIGNAL ;
    PORT
      LAYER M4 ;
        RECT  47.436 69.168 47.52 69.192 ;
    END
  END o_d[207]
  PIN o_d[208]
    DIRECTION OUTPUT ;
    USE SIGNAL ;
    PORT
      LAYER M4 ;
        RECT  47.436 69.264 47.52 69.288 ;
    END
  END o_d[208]
  PIN o_d[209]
    DIRECTION OUTPUT ;
    USE SIGNAL ;
    PORT
      LAYER M4 ;
        RECT  47.436 69.36 47.52 69.384 ;
    END
  END o_d[209]
  PIN o_d[20]
    DIRECTION OUTPUT ;
    USE SIGNAL ;
    PORT
      LAYER M4 ;
        RECT  47.436 28.176 47.52 28.2 ;
    END
  END o_d[20]
  PIN o_d[210]
    DIRECTION OUTPUT ;
    USE SIGNAL ;
    PORT
      LAYER M4 ;
        RECT  47.436 69.456 47.52 69.48 ;
    END
  END o_d[210]
  PIN o_d[211]
    DIRECTION OUTPUT ;
    USE SIGNAL ;
    PORT
      LAYER M4 ;
        RECT  47.436 69.552 47.52 69.576 ;
    END
  END o_d[211]
  PIN o_d[212]
    DIRECTION OUTPUT ;
    USE SIGNAL ;
    PORT
      LAYER M4 ;
        RECT  47.436 69.648 47.52 69.672 ;
    END
  END o_d[212]
  PIN o_d[213]
    DIRECTION OUTPUT ;
    USE SIGNAL ;
    PORT
      LAYER M4 ;
        RECT  47.436 69.744 47.52 69.768 ;
    END
  END o_d[213]
  PIN o_d[214]
    DIRECTION OUTPUT ;
    USE SIGNAL ;
    PORT
      LAYER M4 ;
        RECT  47.436 69.84 47.52 69.864 ;
    END
  END o_d[214]
  PIN o_d[215]
    DIRECTION OUTPUT ;
    USE SIGNAL ;
    PORT
      LAYER M4 ;
        RECT  47.436 69.936 47.52 69.96 ;
    END
  END o_d[215]
  PIN o_d[216]
    DIRECTION OUTPUT ;
    USE SIGNAL ;
    PORT
      LAYER M4 ;
        RECT  47.436 70.032 47.52 70.056 ;
    END
  END o_d[216]
  PIN o_d[217]
    DIRECTION OUTPUT ;
    USE SIGNAL ;
    PORT
      LAYER M4 ;
        RECT  47.436 70.128 47.52 70.152 ;
    END
  END o_d[217]
  PIN o_d[218]
    DIRECTION OUTPUT ;
    USE SIGNAL ;
    PORT
      LAYER M4 ;
        RECT  47.436 70.224 47.52 70.248 ;
    END
  END o_d[218]
  PIN o_d[219]
    DIRECTION OUTPUT ;
    USE SIGNAL ;
    PORT
      LAYER M4 ;
        RECT  47.436 70.32 47.52 70.344 ;
    END
  END o_d[219]
  PIN o_d[21]
    DIRECTION OUTPUT ;
    USE SIGNAL ;
    PORT
      LAYER M4 ;
        RECT  47.436 28.272 47.52 28.296 ;
    END
  END o_d[21]
  PIN o_d[220]
    DIRECTION OUTPUT ;
    USE SIGNAL ;
    PORT
      LAYER M4 ;
        RECT  47.436 70.416 47.52 70.44 ;
    END
  END o_d[220]
  PIN o_d[221]
    DIRECTION OUTPUT ;
    USE SIGNAL ;
    PORT
      LAYER M4 ;
        RECT  47.436 70.512 47.52 70.536 ;
    END
  END o_d[221]
  PIN o_d[222]
    DIRECTION OUTPUT ;
    USE SIGNAL ;
    PORT
      LAYER M4 ;
        RECT  47.436 61.392 47.52 61.416 ;
    END
  END o_d[222]
  PIN o_d[223]
    DIRECTION OUTPUT ;
    USE SIGNAL ;
    PORT
      LAYER M4 ;
        RECT  47.436 61.488 47.52 61.512 ;
    END
  END o_d[223]
  PIN o_d[224]
    DIRECTION OUTPUT ;
    USE SIGNAL ;
    PORT
      LAYER M4 ;
        RECT  47.436 61.584 47.52 61.608 ;
    END
  END o_d[224]
  PIN o_d[225]
    DIRECTION OUTPUT ;
    USE SIGNAL ;
    PORT
      LAYER M4 ;
        RECT  47.436 61.68 47.52 61.704 ;
    END
  END o_d[225]
  PIN o_d[226]
    DIRECTION OUTPUT ;
    USE SIGNAL ;
    PORT
      LAYER M4 ;
        RECT  47.436 61.776 47.52 61.8 ;
    END
  END o_d[226]
  PIN o_d[227]
    DIRECTION OUTPUT ;
    USE SIGNAL ;
    PORT
      LAYER M4 ;
        RECT  47.436 61.872 47.52 61.896 ;
    END
  END o_d[227]
  PIN o_d[228]
    DIRECTION OUTPUT ;
    USE SIGNAL ;
    PORT
      LAYER M4 ;
        RECT  47.436 61.968 47.52 61.992 ;
    END
  END o_d[228]
  PIN o_d[229]
    DIRECTION OUTPUT ;
    USE SIGNAL ;
    PORT
      LAYER M4 ;
        RECT  47.436 62.064 47.52 62.088 ;
    END
  END o_d[229]
  PIN o_d[22]
    DIRECTION OUTPUT ;
    USE SIGNAL ;
    PORT
      LAYER M4 ;
        RECT  47.436 28.368 47.52 28.392 ;
    END
  END o_d[22]
  PIN o_d[230]
    DIRECTION OUTPUT ;
    USE SIGNAL ;
    PORT
      LAYER M4 ;
        RECT  47.436 62.16 47.52 62.184 ;
    END
  END o_d[230]
  PIN o_d[231]
    DIRECTION OUTPUT ;
    USE SIGNAL ;
    PORT
      LAYER M4 ;
        RECT  47.436 62.256 47.52 62.28 ;
    END
  END o_d[231]
  PIN o_d[232]
    DIRECTION OUTPUT ;
    USE SIGNAL ;
    PORT
      LAYER M4 ;
        RECT  47.436 62.352 47.52 62.376 ;
    END
  END o_d[232]
  PIN o_d[233]
    DIRECTION OUTPUT ;
    USE SIGNAL ;
    PORT
      LAYER M4 ;
        RECT  47.436 62.448 47.52 62.472 ;
    END
  END o_d[233]
  PIN o_d[234]
    DIRECTION OUTPUT ;
    USE SIGNAL ;
    PORT
      LAYER M4 ;
        RECT  47.436 62.544 47.52 62.568 ;
    END
  END o_d[234]
  PIN o_d[235]
    DIRECTION OUTPUT ;
    USE SIGNAL ;
    PORT
      LAYER M4 ;
        RECT  47.436 62.64 47.52 62.664 ;
    END
  END o_d[235]
  PIN o_d[236]
    DIRECTION OUTPUT ;
    USE SIGNAL ;
    PORT
      LAYER M4 ;
        RECT  47.436 62.736 47.52 62.76 ;
    END
  END o_d[236]
  PIN o_d[237]
    DIRECTION OUTPUT ;
    USE SIGNAL ;
    PORT
      LAYER M4 ;
        RECT  47.436 62.832 47.52 62.856 ;
    END
  END o_d[237]
  PIN o_d[238]
    DIRECTION OUTPUT ;
    USE SIGNAL ;
    PORT
      LAYER M4 ;
        RECT  47.436 62.928 47.52 62.952 ;
    END
  END o_d[238]
  PIN o_d[239]
    DIRECTION OUTPUT ;
    USE SIGNAL ;
    PORT
      LAYER M4 ;
        RECT  47.436 63.024 47.52 63.048 ;
    END
  END o_d[239]
  PIN o_d[23]
    DIRECTION OUTPUT ;
    USE SIGNAL ;
    PORT
      LAYER M4 ;
        RECT  47.436 28.464 47.52 28.488 ;
    END
  END o_d[23]
  PIN o_d[240]
    DIRECTION OUTPUT ;
    USE SIGNAL ;
    PORT
      LAYER M4 ;
        RECT  47.436 63.12 47.52 63.144 ;
    END
  END o_d[240]
  PIN o_d[241]
    DIRECTION OUTPUT ;
    USE SIGNAL ;
    PORT
      LAYER M4 ;
        RECT  47.436 63.216 47.52 63.24 ;
    END
  END o_d[241]
  PIN o_d[242]
    DIRECTION OUTPUT ;
    USE SIGNAL ;
    PORT
      LAYER M4 ;
        RECT  47.436 63.312 47.52 63.336 ;
    END
  END o_d[242]
  PIN o_d[243]
    DIRECTION OUTPUT ;
    USE SIGNAL ;
    PORT
      LAYER M4 ;
        RECT  47.436 63.408 47.52 63.432 ;
    END
  END o_d[243]
  PIN o_d[244]
    DIRECTION OUTPUT ;
    USE SIGNAL ;
    PORT
      LAYER M4 ;
        RECT  47.436 63.504 47.52 63.528 ;
    END
  END o_d[244]
  PIN o_d[245]
    DIRECTION OUTPUT ;
    USE SIGNAL ;
    PORT
      LAYER M4 ;
        RECT  47.436 63.6 47.52 63.624 ;
    END
  END o_d[245]
  PIN o_d[246]
    DIRECTION OUTPUT ;
    USE SIGNAL ;
    PORT
      LAYER M4 ;
        RECT  47.436 63.696 47.52 63.72 ;
    END
  END o_d[246]
  PIN o_d[247]
    DIRECTION OUTPUT ;
    USE SIGNAL ;
    PORT
      LAYER M4 ;
        RECT  47.436 63.792 47.52 63.816 ;
    END
  END o_d[247]
  PIN o_d[248]
    DIRECTION OUTPUT ;
    USE SIGNAL ;
    PORT
      LAYER M4 ;
        RECT  47.436 63.888 47.52 63.912 ;
    END
  END o_d[248]
  PIN o_d[249]
    DIRECTION OUTPUT ;
    USE SIGNAL ;
    PORT
      LAYER M4 ;
        RECT  47.436 63.984 47.52 64.008 ;
    END
  END o_d[249]
  PIN o_d[24]
    DIRECTION OUTPUT ;
    USE SIGNAL ;
    PORT
      LAYER M4 ;
        RECT  47.436 28.56 47.52 28.584 ;
    END
  END o_d[24]
  PIN o_d[250]
    DIRECTION OUTPUT ;
    USE SIGNAL ;
    PORT
      LAYER M4 ;
        RECT  47.436 64.08 47.52 64.104 ;
    END
  END o_d[250]
  PIN o_d[251]
    DIRECTION OUTPUT ;
    USE SIGNAL ;
    PORT
      LAYER M4 ;
        RECT  47.436 64.176 47.52 64.2 ;
    END
  END o_d[251]
  PIN o_d[252]
    DIRECTION OUTPUT ;
    USE SIGNAL ;
    PORT
      LAYER M4 ;
        RECT  47.436 64.272 47.52 64.296 ;
    END
  END o_d[252]
  PIN o_d[253]
    DIRECTION OUTPUT ;
    USE SIGNAL ;
    PORT
      LAYER M4 ;
        RECT  47.436 64.368 47.52 64.392 ;
    END
  END o_d[253]
  PIN o_d[254]
    DIRECTION OUTPUT ;
    USE SIGNAL ;
    PORT
      LAYER M4 ;
        RECT  47.436 22.992 47.52 23.016 ;
    END
  END o_d[254]
  PIN o_d[255]
    DIRECTION OUTPUT ;
    USE SIGNAL ;
    PORT
      LAYER M4 ;
        RECT  47.436 23.088 47.52 23.112 ;
    END
  END o_d[255]
  PIN o_d[256]
    DIRECTION OUTPUT ;
    USE SIGNAL ;
    PORT
      LAYER M4 ;
        RECT  47.436 23.184 47.52 23.208 ;
    END
  END o_d[256]
  PIN o_d[257]
    DIRECTION OUTPUT ;
    USE SIGNAL ;
    PORT
      LAYER M4 ;
        RECT  47.436 23.28 47.52 23.304 ;
    END
  END o_d[257]
  PIN o_d[258]
    DIRECTION OUTPUT ;
    USE SIGNAL ;
    PORT
      LAYER M4 ;
        RECT  47.436 23.376 47.52 23.4 ;
    END
  END o_d[258]
  PIN o_d[259]
    DIRECTION OUTPUT ;
    USE SIGNAL ;
    PORT
      LAYER M4 ;
        RECT  47.436 23.472 47.52 23.496 ;
    END
  END o_d[259]
  PIN o_d[25]
    DIRECTION OUTPUT ;
    USE SIGNAL ;
    PORT
      LAYER M4 ;
        RECT  47.436 28.656 47.52 28.68 ;
    END
  END o_d[25]
  PIN o_d[260]
    DIRECTION OUTPUT ;
    USE SIGNAL ;
    PORT
      LAYER M4 ;
        RECT  47.436 23.568 47.52 23.592 ;
    END
  END o_d[260]
  PIN o_d[261]
    DIRECTION OUTPUT ;
    USE SIGNAL ;
    PORT
      LAYER M4 ;
        RECT  47.436 23.664 47.52 23.688 ;
    END
  END o_d[261]
  PIN o_d[262]
    DIRECTION OUTPUT ;
    USE SIGNAL ;
    PORT
      LAYER M4 ;
        RECT  47.436 23.76 47.52 23.784 ;
    END
  END o_d[262]
  PIN o_d[263]
    DIRECTION OUTPUT ;
    USE SIGNAL ;
    PORT
      LAYER M4 ;
        RECT  47.436 23.856 47.52 23.88 ;
    END
  END o_d[263]
  PIN o_d[264]
    DIRECTION OUTPUT ;
    USE SIGNAL ;
    PORT
      LAYER M4 ;
        RECT  47.436 23.952 47.52 23.976 ;
    END
  END o_d[264]
  PIN o_d[265]
    DIRECTION OUTPUT ;
    USE SIGNAL ;
    PORT
      LAYER M4 ;
        RECT  47.436 24.048 47.52 24.072 ;
    END
  END o_d[265]
  PIN o_d[266]
    DIRECTION OUTPUT ;
    USE SIGNAL ;
    PORT
      LAYER M4 ;
        RECT  47.436 24.144 47.52 24.168 ;
    END
  END o_d[266]
  PIN o_d[267]
    DIRECTION OUTPUT ;
    USE SIGNAL ;
    PORT
      LAYER M4 ;
        RECT  47.436 24.24 47.52 24.264 ;
    END
  END o_d[267]
  PIN o_d[268]
    DIRECTION OUTPUT ;
    USE SIGNAL ;
    PORT
      LAYER M4 ;
        RECT  47.436 24.336 47.52 24.36 ;
    END
  END o_d[268]
  PIN o_d[269]
    DIRECTION OUTPUT ;
    USE SIGNAL ;
    PORT
      LAYER M4 ;
        RECT  47.436 24.432 47.52 24.456 ;
    END
  END o_d[269]
  PIN o_d[26]
    DIRECTION OUTPUT ;
    USE SIGNAL ;
    PORT
      LAYER M4 ;
        RECT  47.436 28.752 47.52 28.776 ;
    END
  END o_d[26]
  PIN o_d[270]
    DIRECTION OUTPUT ;
    USE SIGNAL ;
    PORT
      LAYER M4 ;
        RECT  47.436 24.528 47.52 24.552 ;
    END
  END o_d[270]
  PIN o_d[271]
    DIRECTION OUTPUT ;
    USE SIGNAL ;
    PORT
      LAYER M4 ;
        RECT  47.436 24.624 47.52 24.648 ;
    END
  END o_d[271]
  PIN o_d[272]
    DIRECTION OUTPUT ;
    USE SIGNAL ;
    PORT
      LAYER M4 ;
        RECT  47.436 24.72 47.52 24.744 ;
    END
  END o_d[272]
  PIN o_d[273]
    DIRECTION OUTPUT ;
    USE SIGNAL ;
    PORT
      LAYER M4 ;
        RECT  47.436 24.816 47.52 24.84 ;
    END
  END o_d[273]
  PIN o_d[274]
    DIRECTION OUTPUT ;
    USE SIGNAL ;
    PORT
      LAYER M4 ;
        RECT  47.436 24.912 47.52 24.936 ;
    END
  END o_d[274]
  PIN o_d[275]
    DIRECTION OUTPUT ;
    USE SIGNAL ;
    PORT
      LAYER M4 ;
        RECT  47.436 25.008 47.52 25.032 ;
    END
  END o_d[275]
  PIN o_d[276]
    DIRECTION OUTPUT ;
    USE SIGNAL ;
    PORT
      LAYER M4 ;
        RECT  47.436 25.104 47.52 25.128 ;
    END
  END o_d[276]
  PIN o_d[277]
    DIRECTION OUTPUT ;
    USE SIGNAL ;
    PORT
      LAYER M4 ;
        RECT  47.436 25.2 47.52 25.224 ;
    END
  END o_d[277]
  PIN o_d[278]
    DIRECTION OUTPUT ;
    USE SIGNAL ;
    PORT
      LAYER M4 ;
        RECT  47.436 25.296 47.52 25.32 ;
    END
  END o_d[278]
  PIN o_d[279]
    DIRECTION OUTPUT ;
    USE SIGNAL ;
    PORT
      LAYER M4 ;
        RECT  47.436 25.392 47.52 25.416 ;
    END
  END o_d[279]
  PIN o_d[27]
    DIRECTION OUTPUT ;
    USE SIGNAL ;
    PORT
      LAYER M4 ;
        RECT  47.436 28.848 47.52 28.872 ;
    END
  END o_d[27]
  PIN o_d[280]
    DIRECTION OUTPUT ;
    USE SIGNAL ;
    PORT
      LAYER M4 ;
        RECT  47.436 25.488 47.52 25.512 ;
    END
  END o_d[280]
  PIN o_d[281]
    DIRECTION OUTPUT ;
    USE SIGNAL ;
    PORT
      LAYER M4 ;
        RECT  47.436 25.584 47.52 25.608 ;
    END
  END o_d[281]
  PIN o_d[282]
    DIRECTION OUTPUT ;
    USE SIGNAL ;
    PORT
      LAYER M4 ;
        RECT  47.436 25.68 47.52 25.704 ;
    END
  END o_d[282]
  PIN o_d[283]
    DIRECTION OUTPUT ;
    USE SIGNAL ;
    PORT
      LAYER M4 ;
        RECT  47.436 25.776 47.52 25.8 ;
    END
  END o_d[283]
  PIN o_d[284]
    DIRECTION OUTPUT ;
    USE SIGNAL ;
    PORT
      LAYER M4 ;
        RECT  47.436 25.872 47.52 25.896 ;
    END
  END o_d[284]
  PIN o_d[285]
    DIRECTION OUTPUT ;
    USE SIGNAL ;
    PORT
      LAYER M4 ;
        RECT  47.436 25.968 47.52 25.992 ;
    END
  END o_d[285]
  PIN o_d[286]
    DIRECTION OUTPUT ;
    USE SIGNAL ;
    PORT
      LAYER M4 ;
        RECT  47.436 16.08 47.52 16.104 ;
    END
  END o_d[286]
  PIN o_d[287]
    DIRECTION OUTPUT ;
    USE SIGNAL ;
    PORT
      LAYER M4 ;
        RECT  47.436 16.176 47.52 16.2 ;
    END
  END o_d[287]
  PIN o_d[288]
    DIRECTION OUTPUT ;
    USE SIGNAL ;
    PORT
      LAYER M4 ;
        RECT  47.436 16.272 47.52 16.296 ;
    END
  END o_d[288]
  PIN o_d[289]
    DIRECTION OUTPUT ;
    USE SIGNAL ;
    PORT
      LAYER M4 ;
        RECT  47.436 16.368 47.52 16.392 ;
    END
  END o_d[289]
  PIN o_d[28]
    DIRECTION OUTPUT ;
    USE SIGNAL ;
    PORT
      LAYER M4 ;
        RECT  47.436 28.944 47.52 28.968 ;
    END
  END o_d[28]
  PIN o_d[290]
    DIRECTION OUTPUT ;
    USE SIGNAL ;
    PORT
      LAYER M4 ;
        RECT  47.436 16.464 47.52 16.488 ;
    END
  END o_d[290]
  PIN o_d[291]
    DIRECTION OUTPUT ;
    USE SIGNAL ;
    PORT
      LAYER M4 ;
        RECT  47.436 16.56 47.52 16.584 ;
    END
  END o_d[291]
  PIN o_d[292]
    DIRECTION OUTPUT ;
    USE SIGNAL ;
    PORT
      LAYER M4 ;
        RECT  47.436 16.656 47.52 16.68 ;
    END
  END o_d[292]
  PIN o_d[293]
    DIRECTION OUTPUT ;
    USE SIGNAL ;
    PORT
      LAYER M4 ;
        RECT  47.436 16.752 47.52 16.776 ;
    END
  END o_d[293]
  PIN o_d[294]
    DIRECTION OUTPUT ;
    USE SIGNAL ;
    PORT
      LAYER M4 ;
        RECT  47.436 16.848 47.52 16.872 ;
    END
  END o_d[294]
  PIN o_d[295]
    DIRECTION OUTPUT ;
    USE SIGNAL ;
    PORT
      LAYER M4 ;
        RECT  47.436 16.944 47.52 16.968 ;
    END
  END o_d[295]
  PIN o_d[296]
    DIRECTION OUTPUT ;
    USE SIGNAL ;
    PORT
      LAYER M4 ;
        RECT  47.436 17.04 47.52 17.064 ;
    END
  END o_d[296]
  PIN o_d[297]
    DIRECTION OUTPUT ;
    USE SIGNAL ;
    PORT
      LAYER M4 ;
        RECT  47.436 17.136 47.52 17.16 ;
    END
  END o_d[297]
  PIN o_d[298]
    DIRECTION OUTPUT ;
    USE SIGNAL ;
    PORT
      LAYER M4 ;
        RECT  47.436 17.232 47.52 17.256 ;
    END
  END o_d[298]
  PIN o_d[299]
    DIRECTION OUTPUT ;
    USE SIGNAL ;
    PORT
      LAYER M4 ;
        RECT  47.436 17.328 47.52 17.352 ;
    END
  END o_d[299]
  PIN o_d[29]
    DIRECTION OUTPUT ;
    USE SIGNAL ;
    PORT
      LAYER M4 ;
        RECT  47.436 29.04 47.52 29.064 ;
    END
  END o_d[29]
  PIN o_d[2]
    DIRECTION OUTPUT ;
    USE SIGNAL ;
    PORT
      LAYER M4 ;
        RECT  47.436 26.448 47.52 26.472 ;
    END
  END o_d[2]
  PIN o_d[300]
    DIRECTION OUTPUT ;
    USE SIGNAL ;
    PORT
      LAYER M4 ;
        RECT  47.436 17.424 47.52 17.448 ;
    END
  END o_d[300]
  PIN o_d[301]
    DIRECTION OUTPUT ;
    USE SIGNAL ;
    PORT
      LAYER M4 ;
        RECT  47.436 17.52 47.52 17.544 ;
    END
  END o_d[301]
  PIN o_d[302]
    DIRECTION OUTPUT ;
    USE SIGNAL ;
    PORT
      LAYER M4 ;
        RECT  47.436 17.616 47.52 17.64 ;
    END
  END o_d[302]
  PIN o_d[303]
    DIRECTION OUTPUT ;
    USE SIGNAL ;
    PORT
      LAYER M4 ;
        RECT  47.436 17.712 47.52 17.736 ;
    END
  END o_d[303]
  PIN o_d[304]
    DIRECTION OUTPUT ;
    USE SIGNAL ;
    PORT
      LAYER M4 ;
        RECT  47.436 17.808 47.52 17.832 ;
    END
  END o_d[304]
  PIN o_d[305]
    DIRECTION OUTPUT ;
    USE SIGNAL ;
    PORT
      LAYER M4 ;
        RECT  47.436 17.904 47.52 17.928 ;
    END
  END o_d[305]
  PIN o_d[306]
    DIRECTION OUTPUT ;
    USE SIGNAL ;
    PORT
      LAYER M4 ;
        RECT  47.436 18 47.52 18.024 ;
    END
  END o_d[306]
  PIN o_d[307]
    DIRECTION OUTPUT ;
    USE SIGNAL ;
    PORT
      LAYER M4 ;
        RECT  47.436 18.096 47.52 18.12 ;
    END
  END o_d[307]
  PIN o_d[308]
    DIRECTION OUTPUT ;
    USE SIGNAL ;
    PORT
      LAYER M4 ;
        RECT  47.436 18.192 47.52 18.216 ;
    END
  END o_d[308]
  PIN o_d[309]
    DIRECTION OUTPUT ;
    USE SIGNAL ;
    PORT
      LAYER M4 ;
        RECT  47.436 18.288 47.52 18.312 ;
    END
  END o_d[309]
  PIN o_d[30]
    DIRECTION OUTPUT ;
    USE SIGNAL ;
    PORT
      LAYER M4 ;
        RECT  47.436 13.008 47.52 13.032 ;
    END
  END o_d[30]
  PIN o_d[310]
    DIRECTION OUTPUT ;
    USE SIGNAL ;
    PORT
      LAYER M4 ;
        RECT  47.436 18.384 47.52 18.408 ;
    END
  END o_d[310]
  PIN o_d[311]
    DIRECTION OUTPUT ;
    USE SIGNAL ;
    PORT
      LAYER M4 ;
        RECT  47.436 18.48 47.52 18.504 ;
    END
  END o_d[311]
  PIN o_d[312]
    DIRECTION OUTPUT ;
    USE SIGNAL ;
    PORT
      LAYER M4 ;
        RECT  47.436 18.576 47.52 18.6 ;
    END
  END o_d[312]
  PIN o_d[313]
    DIRECTION OUTPUT ;
    USE SIGNAL ;
    PORT
      LAYER M4 ;
        RECT  47.436 18.672 47.52 18.696 ;
    END
  END o_d[313]
  PIN o_d[314]
    DIRECTION OUTPUT ;
    USE SIGNAL ;
    PORT
      LAYER M4 ;
        RECT  47.436 18.768 47.52 18.792 ;
    END
  END o_d[314]
  PIN o_d[315]
    DIRECTION OUTPUT ;
    USE SIGNAL ;
    PORT
      LAYER M4 ;
        RECT  47.436 18.864 47.52 18.888 ;
    END
  END o_d[315]
  PIN o_d[316]
    DIRECTION OUTPUT ;
    USE SIGNAL ;
    PORT
      LAYER M4 ;
        RECT  47.436 18.96 47.52 18.984 ;
    END
  END o_d[316]
  PIN o_d[317]
    DIRECTION OUTPUT ;
    USE SIGNAL ;
    PORT
      LAYER M4 ;
        RECT  47.436 19.056 47.52 19.08 ;
    END
  END o_d[317]
  PIN o_d[318]
    DIRECTION OUTPUT ;
    USE SIGNAL ;
    PORT
      LAYER M4 ;
        RECT  47.436 32.208 47.52 32.232 ;
    END
  END o_d[318]
  PIN o_d[319]
    DIRECTION OUTPUT ;
    USE SIGNAL ;
    PORT
      LAYER M4 ;
        RECT  47.436 32.304 47.52 32.328 ;
    END
  END o_d[319]
  PIN o_d[31]
    DIRECTION OUTPUT ;
    USE SIGNAL ;
    PORT
      LAYER M4 ;
        RECT  47.436 13.104 47.52 13.128 ;
    END
  END o_d[31]
  PIN o_d[320]
    DIRECTION OUTPUT ;
    USE SIGNAL ;
    PORT
      LAYER M4 ;
        RECT  47.436 32.4 47.52 32.424 ;
    END
  END o_d[320]
  PIN o_d[321]
    DIRECTION OUTPUT ;
    USE SIGNAL ;
    PORT
      LAYER M4 ;
        RECT  47.436 32.496 47.52 32.52 ;
    END
  END o_d[321]
  PIN o_d[322]
    DIRECTION OUTPUT ;
    USE SIGNAL ;
    PORT
      LAYER M4 ;
        RECT  47.436 32.592 47.52 32.616 ;
    END
  END o_d[322]
  PIN o_d[323]
    DIRECTION OUTPUT ;
    USE SIGNAL ;
    PORT
      LAYER M4 ;
        RECT  47.436 32.688 47.52 32.712 ;
    END
  END o_d[323]
  PIN o_d[324]
    DIRECTION OUTPUT ;
    USE SIGNAL ;
    PORT
      LAYER M4 ;
        RECT  47.436 32.784 47.52 32.808 ;
    END
  END o_d[324]
  PIN o_d[325]
    DIRECTION OUTPUT ;
    USE SIGNAL ;
    PORT
      LAYER M4 ;
        RECT  47.436 32.88 47.52 32.904 ;
    END
  END o_d[325]
  PIN o_d[32]
    DIRECTION OUTPUT ;
    USE SIGNAL ;
    PORT
      LAYER M4 ;
        RECT  47.436 13.2 47.52 13.224 ;
    END
  END o_d[32]
  PIN o_d[33]
    DIRECTION OUTPUT ;
    USE SIGNAL ;
    PORT
      LAYER M4 ;
        RECT  47.436 13.296 47.52 13.32 ;
    END
  END o_d[33]
  PIN o_d[34]
    DIRECTION OUTPUT ;
    USE SIGNAL ;
    PORT
      LAYER M4 ;
        RECT  47.436 13.392 47.52 13.416 ;
    END
  END o_d[34]
  PIN o_d[35]
    DIRECTION OUTPUT ;
    USE SIGNAL ;
    PORT
      LAYER M4 ;
        RECT  47.436 13.488 47.52 13.512 ;
    END
  END o_d[35]
  PIN o_d[36]
    DIRECTION OUTPUT ;
    USE SIGNAL ;
    PORT
      LAYER M4 ;
        RECT  47.436 13.584 47.52 13.608 ;
    END
  END o_d[36]
  PIN o_d[37]
    DIRECTION OUTPUT ;
    USE SIGNAL ;
    PORT
      LAYER M4 ;
        RECT  47.436 13.68 47.52 13.704 ;
    END
  END o_d[37]
  PIN o_d[38]
    DIRECTION OUTPUT ;
    USE SIGNAL ;
    PORT
      LAYER M4 ;
        RECT  47.436 13.776 47.52 13.8 ;
    END
  END o_d[38]
  PIN o_d[39]
    DIRECTION OUTPUT ;
    USE SIGNAL ;
    PORT
      LAYER M4 ;
        RECT  47.436 13.872 47.52 13.896 ;
    END
  END o_d[39]
  PIN o_d[3]
    DIRECTION OUTPUT ;
    USE SIGNAL ;
    PORT
      LAYER M4 ;
        RECT  47.436 26.544 47.52 26.568 ;
    END
  END o_d[3]
  PIN o_d[40]
    DIRECTION OUTPUT ;
    USE SIGNAL ;
    PORT
      LAYER M4 ;
        RECT  47.436 13.968 47.52 13.992 ;
    END
  END o_d[40]
  PIN o_d[41]
    DIRECTION OUTPUT ;
    USE SIGNAL ;
    PORT
      LAYER M4 ;
        RECT  47.436 14.064 47.52 14.088 ;
    END
  END o_d[41]
  PIN o_d[42]
    DIRECTION OUTPUT ;
    USE SIGNAL ;
    PORT
      LAYER M4 ;
        RECT  47.436 14.16 47.52 14.184 ;
    END
  END o_d[42]
  PIN o_d[43]
    DIRECTION OUTPUT ;
    USE SIGNAL ;
    PORT
      LAYER M4 ;
        RECT  47.436 14.256 47.52 14.28 ;
    END
  END o_d[43]
  PIN o_d[44]
    DIRECTION OUTPUT ;
    USE SIGNAL ;
    PORT
      LAYER M4 ;
        RECT  47.436 14.352 47.52 14.376 ;
    END
  END o_d[44]
  PIN o_d[45]
    DIRECTION OUTPUT ;
    USE SIGNAL ;
    PORT
      LAYER M4 ;
        RECT  47.436 14.448 47.52 14.472 ;
    END
  END o_d[45]
  PIN o_d[46]
    DIRECTION OUTPUT ;
    USE SIGNAL ;
    PORT
      LAYER M4 ;
        RECT  47.436 14.544 47.52 14.568 ;
    END
  END o_d[46]
  PIN o_d[47]
    DIRECTION OUTPUT ;
    USE SIGNAL ;
    PORT
      LAYER M4 ;
        RECT  47.436 14.64 47.52 14.664 ;
    END
  END o_d[47]
  PIN o_d[48]
    DIRECTION OUTPUT ;
    USE SIGNAL ;
    PORT
      LAYER M4 ;
        RECT  47.436 14.736 47.52 14.76 ;
    END
  END o_d[48]
  PIN o_d[49]
    DIRECTION OUTPUT ;
    USE SIGNAL ;
    PORT
      LAYER M4 ;
        RECT  47.436 14.832 47.52 14.856 ;
    END
  END o_d[49]
  PIN o_d[4]
    DIRECTION OUTPUT ;
    USE SIGNAL ;
    PORT
      LAYER M4 ;
        RECT  47.436 26.64 47.52 26.664 ;
    END
  END o_d[4]
  PIN o_d[50]
    DIRECTION OUTPUT ;
    USE SIGNAL ;
    PORT
      LAYER M4 ;
        RECT  47.436 14.928 47.52 14.952 ;
    END
  END o_d[50]
  PIN o_d[51]
    DIRECTION OUTPUT ;
    USE SIGNAL ;
    PORT
      LAYER M4 ;
        RECT  47.436 15.024 47.52 15.048 ;
    END
  END o_d[51]
  PIN o_d[52]
    DIRECTION OUTPUT ;
    USE SIGNAL ;
    PORT
      LAYER M4 ;
        RECT  47.436 15.12 47.52 15.144 ;
    END
  END o_d[52]
  PIN o_d[53]
    DIRECTION OUTPUT ;
    USE SIGNAL ;
    PORT
      LAYER M4 ;
        RECT  47.436 15.216 47.52 15.24 ;
    END
  END o_d[53]
  PIN o_d[54]
    DIRECTION OUTPUT ;
    USE SIGNAL ;
    PORT
      LAYER M4 ;
        RECT  47.436 15.312 47.52 15.336 ;
    END
  END o_d[54]
  PIN o_d[55]
    DIRECTION OUTPUT ;
    USE SIGNAL ;
    PORT
      LAYER M4 ;
        RECT  47.436 15.408 47.52 15.432 ;
    END
  END o_d[55]
  PIN o_d[56]
    DIRECTION OUTPUT ;
    USE SIGNAL ;
    PORT
      LAYER M4 ;
        RECT  47.436 15.504 47.52 15.528 ;
    END
  END o_d[56]
  PIN o_d[57]
    DIRECTION OUTPUT ;
    USE SIGNAL ;
    PORT
      LAYER M4 ;
        RECT  47.436 15.6 47.52 15.624 ;
    END
  END o_d[57]
  PIN o_d[58]
    DIRECTION OUTPUT ;
    USE SIGNAL ;
    PORT
      LAYER M4 ;
        RECT  47.436 15.696 47.52 15.72 ;
    END
  END o_d[58]
  PIN o_d[59]
    DIRECTION OUTPUT ;
    USE SIGNAL ;
    PORT
      LAYER M4 ;
        RECT  47.436 15.792 47.52 15.816 ;
    END
  END o_d[59]
  PIN o_d[5]
    DIRECTION OUTPUT ;
    USE SIGNAL ;
    PORT
      LAYER M4 ;
        RECT  47.436 26.736 47.52 26.76 ;
    END
  END o_d[5]
  PIN o_d[60]
    DIRECTION OUTPUT ;
    USE SIGNAL ;
    PORT
      LAYER M4 ;
        RECT  47.436 15.888 47.52 15.912 ;
    END
  END o_d[60]
  PIN o_d[61]
    DIRECTION OUTPUT ;
    USE SIGNAL ;
    PORT
      LAYER M4 ;
        RECT  47.436 15.984 47.52 16.008 ;
    END
  END o_d[61]
  PIN o_d[62]
    DIRECTION OUTPUT ;
    USE SIGNAL ;
    PORT
      LAYER M4 ;
        RECT  47.436 35.28 47.52 35.304 ;
    END
  END o_d[62]
  PIN o_d[63]
    DIRECTION OUTPUT ;
    USE SIGNAL ;
    PORT
      LAYER M4 ;
        RECT  47.436 35.376 47.52 35.4 ;
    END
  END o_d[63]
  PIN o_d[64]
    DIRECTION OUTPUT ;
    USE SIGNAL ;
    PORT
      LAYER M4 ;
        RECT  47.436 35.472 47.52 35.496 ;
    END
  END o_d[64]
  PIN o_d[65]
    DIRECTION OUTPUT ;
    USE SIGNAL ;
    PORT
      LAYER M4 ;
        RECT  47.436 35.568 47.52 35.592 ;
    END
  END o_d[65]
  PIN o_d[66]
    DIRECTION OUTPUT ;
    USE SIGNAL ;
    PORT
      LAYER M4 ;
        RECT  47.436 35.664 47.52 35.688 ;
    END
  END o_d[66]
  PIN o_d[67]
    DIRECTION OUTPUT ;
    USE SIGNAL ;
    PORT
      LAYER M4 ;
        RECT  47.436 35.76 47.52 35.784 ;
    END
  END o_d[67]
  PIN o_d[68]
    DIRECTION OUTPUT ;
    USE SIGNAL ;
    PORT
      LAYER M4 ;
        RECT  47.436 35.856 47.52 35.88 ;
    END
  END o_d[68]
  PIN o_d[69]
    DIRECTION OUTPUT ;
    USE SIGNAL ;
    PORT
      LAYER M4 ;
        RECT  47.436 35.952 47.52 35.976 ;
    END
  END o_d[69]
  PIN o_d[6]
    DIRECTION OUTPUT ;
    USE SIGNAL ;
    PORT
      LAYER M4 ;
        RECT  47.436 26.832 47.52 26.856 ;
    END
  END o_d[6]
  PIN o_d[70]
    DIRECTION OUTPUT ;
    USE SIGNAL ;
    PORT
      LAYER M4 ;
        RECT  47.436 36.048 47.52 36.072 ;
    END
  END o_d[70]
  PIN o_d[71]
    DIRECTION OUTPUT ;
    USE SIGNAL ;
    PORT
      LAYER M4 ;
        RECT  47.436 36.144 47.52 36.168 ;
    END
  END o_d[71]
  PIN o_d[72]
    DIRECTION OUTPUT ;
    USE SIGNAL ;
    PORT
      LAYER M4 ;
        RECT  47.436 36.24 47.52 36.264 ;
    END
  END o_d[72]
  PIN o_d[73]
    DIRECTION OUTPUT ;
    USE SIGNAL ;
    PORT
      LAYER M4 ;
        RECT  47.436 36.336 47.52 36.36 ;
    END
  END o_d[73]
  PIN o_d[74]
    DIRECTION OUTPUT ;
    USE SIGNAL ;
    PORT
      LAYER M4 ;
        RECT  47.436 36.432 47.52 36.456 ;
    END
  END o_d[74]
  PIN o_d[75]
    DIRECTION OUTPUT ;
    USE SIGNAL ;
    PORT
      LAYER M4 ;
        RECT  47.436 36.528 47.52 36.552 ;
    END
  END o_d[75]
  PIN o_d[76]
    DIRECTION OUTPUT ;
    USE SIGNAL ;
    PORT
      LAYER M4 ;
        RECT  47.436 36.624 47.52 36.648 ;
    END
  END o_d[76]
  PIN o_d[77]
    DIRECTION OUTPUT ;
    USE SIGNAL ;
    PORT
      LAYER M4 ;
        RECT  47.436 36.72 47.52 36.744 ;
    END
  END o_d[77]
  PIN o_d[78]
    DIRECTION OUTPUT ;
    USE SIGNAL ;
    PORT
      LAYER M4 ;
        RECT  47.436 36.816 47.52 36.84 ;
    END
  END o_d[78]
  PIN o_d[79]
    DIRECTION OUTPUT ;
    USE SIGNAL ;
    PORT
      LAYER M4 ;
        RECT  47.436 36.912 47.52 36.936 ;
    END
  END o_d[79]
  PIN o_d[7]
    DIRECTION OUTPUT ;
    USE SIGNAL ;
    PORT
      LAYER M4 ;
        RECT  47.436 26.928 47.52 26.952 ;
    END
  END o_d[7]
  PIN o_d[80]
    DIRECTION OUTPUT ;
    USE SIGNAL ;
    PORT
      LAYER M4 ;
        RECT  47.436 37.008 47.52 37.032 ;
    END
  END o_d[80]
  PIN o_d[81]
    DIRECTION OUTPUT ;
    USE SIGNAL ;
    PORT
      LAYER M4 ;
        RECT  47.436 37.104 47.52 37.128 ;
    END
  END o_d[81]
  PIN o_d[82]
    DIRECTION OUTPUT ;
    USE SIGNAL ;
    PORT
      LAYER M4 ;
        RECT  47.436 37.2 47.52 37.224 ;
    END
  END o_d[82]
  PIN o_d[83]
    DIRECTION OUTPUT ;
    USE SIGNAL ;
    PORT
      LAYER M4 ;
        RECT  47.436 37.296 47.52 37.32 ;
    END
  END o_d[83]
  PIN o_d[84]
    DIRECTION OUTPUT ;
    USE SIGNAL ;
    PORT
      LAYER M4 ;
        RECT  47.436 37.392 47.52 37.416 ;
    END
  END o_d[84]
  PIN o_d[85]
    DIRECTION OUTPUT ;
    USE SIGNAL ;
    PORT
      LAYER M4 ;
        RECT  47.436 37.488 47.52 37.512 ;
    END
  END o_d[85]
  PIN o_d[86]
    DIRECTION OUTPUT ;
    USE SIGNAL ;
    PORT
      LAYER M4 ;
        RECT  47.436 37.584 47.52 37.608 ;
    END
  END o_d[86]
  PIN o_d[87]
    DIRECTION OUTPUT ;
    USE SIGNAL ;
    PORT
      LAYER M4 ;
        RECT  47.436 37.68 47.52 37.704 ;
    END
  END o_d[87]
  PIN o_d[88]
    DIRECTION OUTPUT ;
    USE SIGNAL ;
    PORT
      LAYER M4 ;
        RECT  47.436 37.776 47.52 37.8 ;
    END
  END o_d[88]
  PIN o_d[89]
    DIRECTION OUTPUT ;
    USE SIGNAL ;
    PORT
      LAYER M4 ;
        RECT  47.436 37.872 47.52 37.896 ;
    END
  END o_d[89]
  PIN o_d[8]
    DIRECTION OUTPUT ;
    USE SIGNAL ;
    PORT
      LAYER M4 ;
        RECT  47.436 27.024 47.52 27.048 ;
    END
  END o_d[8]
  PIN o_d[90]
    DIRECTION OUTPUT ;
    USE SIGNAL ;
    PORT
      LAYER M4 ;
        RECT  47.436 37.968 47.52 37.992 ;
    END
  END o_d[90]
  PIN o_d[91]
    DIRECTION OUTPUT ;
    USE SIGNAL ;
    PORT
      LAYER M4 ;
        RECT  47.436 38.064 47.52 38.088 ;
    END
  END o_d[91]
  PIN o_d[92]
    DIRECTION OUTPUT ;
    USE SIGNAL ;
    PORT
      LAYER M4 ;
        RECT  47.436 38.16 47.52 38.184 ;
    END
  END o_d[92]
  PIN o_d[93]
    DIRECTION OUTPUT ;
    USE SIGNAL ;
    PORT
      LAYER M4 ;
        RECT  47.436 38.256 47.52 38.28 ;
    END
  END o_d[93]
  PIN o_d[94]
    DIRECTION OUTPUT ;
    USE SIGNAL ;
    PORT
      LAYER M4 ;
        RECT  47.436 77.52 47.52 77.544 ;
    END
  END o_d[94]
  PIN o_d[95]
    DIRECTION OUTPUT ;
    USE SIGNAL ;
    PORT
      LAYER M4 ;
        RECT  47.436 77.616 47.52 77.64 ;
    END
  END o_d[95]
  PIN o_d[96]
    DIRECTION OUTPUT ;
    USE SIGNAL ;
    PORT
      LAYER M4 ;
        RECT  47.436 77.712 47.52 77.736 ;
    END
  END o_d[96]
  PIN o_d[97]
    DIRECTION OUTPUT ;
    USE SIGNAL ;
    PORT
      LAYER M4 ;
        RECT  47.436 77.808 47.52 77.832 ;
    END
  END o_d[97]
  PIN o_d[98]
    DIRECTION OUTPUT ;
    USE SIGNAL ;
    PORT
      LAYER M4 ;
        RECT  47.436 77.904 47.52 77.928 ;
    END
  END o_d[98]
  PIN o_d[99]
    DIRECTION OUTPUT ;
    USE SIGNAL ;
    PORT
      LAYER M4 ;
        RECT  47.436 78 47.52 78.024 ;
    END
  END o_d[99]
  PIN o_d[9]
    DIRECTION OUTPUT ;
    USE SIGNAL ;
    PORT
      LAYER M4 ;
        RECT  47.436 27.12 47.52 27.144 ;
    END
  END o_d[9]
  PIN o_v[0]
    DIRECTION OUTPUT ;
    USE SIGNAL ;
    PORT
      LAYER M4 ;
        RECT  47.436 32.976 47.52 33 ;
    END
  END o_v[0]
  PIN o_v[1]
    DIRECTION OUTPUT ;
    USE SIGNAL ;
    PORT
      LAYER M4 ;
        RECT  47.436 33.072 47.52 33.096 ;
    END
  END o_v[1]
  PIN rs
    DIRECTION INPUT ;
    USE SIGNAL ;
    PORT
      LAYER M5 ;
        RECT  8.304 81.996 8.328 82.08 ;
    END
  END rs
  PIN VDD
    DIRECTION INOUT ;
    USE POWER ;
    PORT
      LAYER M5 ;
        RECT  40.392 2.151 40.512 79.929 ;
        RECT  34.992 2.151 35.112 79.929 ;
        RECT  29.592 2.151 29.712 79.929 ;
        RECT  24.192 2.151 24.312 79.929 ;
        RECT  18.792 2.151 18.912 79.929 ;
        RECT  13.392 2.151 13.512 79.929 ;
        RECT  7.992 2.151 8.112 79.929 ;
        RECT  2.592 2.151 2.712 79.929 ;
    END
  END VDD
  PIN VSS
    DIRECTION INOUT ;
    USE GROUND ;
    PORT
      LAYER M5 ;
        RECT  40.2 2.137 40.32 79.943 ;
        RECT  34.8 2.137 34.92 79.943 ;
        RECT  29.4 2.137 29.52 79.943 ;
        RECT  24 2.137 24.12 79.943 ;
        RECT  18.6 2.137 18.72 79.943 ;
        RECT  13.2 2.137 13.32 79.943 ;
        RECT  7.8 2.137 7.92 79.943 ;
        RECT  2.4 2.137 2.52 79.943 ;
    END
  END VSS
  # OT_OBS_CLOSED layer=M5 d_um=1.536 added=341
  OBS
    LAYER RVTN ;
     RECT  2.16 2.16 45.36 2.295 ;
     RECT  2.16 2.565 45.36 2.835 ;
     RECT  2.16 3.105 45.36 3.375 ;
     RECT  2.16 3.645 45.36 3.915 ;
     RECT  2.16 4.185 45.36 4.455 ;
     RECT  2.16 4.725 45.36 4.995 ;
     RECT  2.16 5.265 45.36 5.535 ;
     RECT  2.16 5.805 45.36 6.075 ;
     RECT  2.16 6.345 45.36 6.615 ;
     RECT  2.16 6.885 45.36 7.155 ;
     RECT  2.16 7.425 45.36 7.695 ;
     RECT  2.16 7.965 45.36 8.235 ;
     RECT  2.16 8.505 45.36 8.775 ;
     RECT  2.16 9.045 45.36 9.315 ;
     RECT  2.16 9.585 45.36 9.855 ;
     RECT  2.16 10.125 45.36 10.395 ;
     RECT  2.16 10.665 45.36 10.935 ;
     RECT  2.16 11.205 45.36 11.475 ;
     RECT  2.16 11.745 45.36 12.015 ;
     RECT  2.16 12.285 45.36 12.555 ;
     RECT  2.16 12.825 45.36 13.095 ;
     RECT  2.16 13.365 45.36 13.635 ;
     RECT  2.16 13.905 45.36 14.175 ;
     RECT  2.16 14.445 45.36 14.715 ;
     RECT  2.16 14.985 45.36 15.255 ;
     RECT  2.16 15.525 45.36 15.795 ;
     RECT  2.16 16.065 45.36 16.335 ;
     RECT  2.16 16.605 45.36 16.875 ;
     RECT  2.16 17.145 45.36 17.415 ;
     RECT  2.16 17.685 45.36 17.955 ;
     RECT  2.16 18.225 45.36 18.495 ;
     RECT  2.16 18.765 45.36 19.035 ;
     RECT  2.16 19.305 45.36 19.575 ;
     RECT  2.16 19.845 45.36 20.115 ;
     RECT  2.16 20.385 45.36 20.655 ;
     RECT  2.16 20.925 45.36 21.195 ;
     RECT  2.16 21.465 45.36 21.735 ;
     RECT  2.16 22.005 45.36 22.275 ;
     RECT  2.16 22.545 45.36 22.815 ;
     RECT  2.16 23.085 45.36 23.355 ;
     RECT  2.16 23.625 45.36 23.895 ;
     RECT  2.16 24.165 45.36 24.435 ;
     RECT  2.16 24.705 45.36 24.975 ;
     RECT  2.16 25.245 45.36 25.515 ;
     RECT  2.16 25.785 45.36 26.055 ;
     RECT  2.16 26.325 45.36 26.595 ;
     RECT  2.16 26.865 45.36 27.135 ;
     RECT  2.16 27.405 45.36 27.675 ;
     RECT  2.16 27.945 45.36 28.215 ;
     RECT  2.16 28.485 45.36 28.755 ;
     RECT  2.16 29.025 45.36 29.295 ;
     RECT  2.16 29.565 45.36 29.835 ;
     RECT  2.16 30.105 45.36 30.375 ;
     RECT  2.16 30.645 45.36 30.915 ;
     RECT  2.16 31.185 45.36 31.455 ;
     RECT  2.16 31.725 45.36 31.995 ;
     RECT  2.16 32.265 45.36 32.535 ;
     RECT  2.16 32.805 45.36 33.075 ;
     RECT  2.16 33.345 45.36 33.615 ;
     RECT  2.16 33.885 45.36 34.155 ;
     RECT  2.16 34.425 45.36 34.695 ;
     RECT  2.16 34.965 45.36 35.235 ;
     RECT  2.16 35.505 45.36 35.775 ;
     RECT  2.16 36.045 45.36 36.315 ;
     RECT  2.16 36.585 45.36 36.855 ;
     RECT  2.16 37.125 45.36 37.395 ;
     RECT  2.16 37.665 45.36 37.935 ;
     RECT  2.16 38.205 45.36 38.475 ;
     RECT  2.16 38.745 45.36 39.015 ;
     RECT  2.16 39.285 45.36 39.555 ;
     RECT  2.16 39.825 45.36 40.095 ;
     RECT  2.16 40.365 45.36 40.635 ;
     RECT  2.16 40.905 45.36 41.175 ;
     RECT  2.16 41.445 45.36 41.715 ;
     RECT  2.16 41.985 45.36 42.255 ;
     RECT  2.16 42.525 45.36 42.795 ;
     RECT  2.16 43.065 45.36 43.335 ;
     RECT  2.16 43.605 45.36 43.875 ;
     RECT  2.16 44.145 45.36 44.415 ;
     RECT  2.16 44.685 45.36 44.955 ;
     RECT  2.16 45.225 45.36 45.495 ;
     RECT  2.16 45.765 45.36 46.035 ;
     RECT  2.16 46.305 45.36 46.575 ;
     RECT  2.16 46.845 45.36 47.115 ;
     RECT  2.16 47.385 45.36 47.655 ;
     RECT  2.16 47.925 45.36 48.195 ;
     RECT  2.16 48.465 45.36 48.735 ;
     RECT  2.16 49.005 45.36 49.275 ;
     RECT  2.16 49.545 45.36 49.815 ;
     RECT  2.16 50.085 45.36 50.355 ;
     RECT  2.16 50.625 45.36 50.895 ;
     RECT  2.16 51.165 45.36 51.435 ;
     RECT  2.16 51.705 45.36 51.975 ;
     RECT  2.16 52.245 45.36 52.515 ;
     RECT  2.16 52.785 45.36 53.055 ;
     RECT  2.16 53.325 45.36 53.595 ;
     RECT  2.16 53.865 45.36 54.135 ;
     RECT  2.16 54.405 45.36 54.675 ;
     RECT  2.16 54.945 45.36 55.215 ;
     RECT  2.16 55.485 45.36 55.755 ;
     RECT  2.16 56.025 45.36 56.295 ;
     RECT  2.16 56.565 45.36 56.835 ;
     RECT  2.16 57.105 45.36 57.375 ;
     RECT  2.16 57.645 45.36 57.915 ;
     RECT  2.16 58.185 45.36 58.455 ;
     RECT  2.16 58.725 45.36 58.995 ;
     RECT  2.16 59.265 45.36 59.535 ;
     RECT  2.16 59.805 45.36 60.075 ;
     RECT  2.16 60.345 45.36 60.615 ;
     RECT  2.16 60.885 45.36 61.155 ;
     RECT  2.16 61.425 45.36 61.695 ;
     RECT  2.16 61.965 45.36 62.235 ;
     RECT  2.16 62.505 45.36 62.775 ;
     RECT  2.16 63.045 45.36 63.315 ;
     RECT  2.16 63.585 45.36 63.855 ;
     RECT  2.16 64.125 45.36 64.395 ;
     RECT  2.16 64.665 45.36 64.935 ;
     RECT  2.16 65.205 45.36 65.475 ;
     RECT  2.16 65.745 45.36 66.015 ;
     RECT  2.16 66.285 45.36 66.555 ;
     RECT  2.16 66.825 45.36 67.095 ;
     RECT  2.16 67.365 45.36 67.635 ;
     RECT  2.16 67.905 45.36 68.175 ;
     RECT  2.16 68.445 45.36 68.715 ;
     RECT  2.16 68.985 45.36 69.255 ;
     RECT  2.16 69.525 45.36 69.795 ;
     RECT  2.16 70.065 45.36 70.335 ;
     RECT  2.16 70.605 45.36 70.875 ;
     RECT  2.16 71.145 45.36 71.415 ;
     RECT  2.16 71.685 45.36 71.955 ;
     RECT  2.16 72.225 45.36 72.495 ;
     RECT  2.16 72.765 45.36 73.035 ;
     RECT  2.16 73.305 45.36 73.575 ;
     RECT  2.16 73.845 45.36 74.115 ;
     RECT  2.16 74.385 45.36 74.655 ;
     RECT  2.16 74.925 45.36 75.195 ;
     RECT  2.16 75.465 45.36 75.735 ;
     RECT  2.16 76.005 45.36 76.275 ;
     RECT  2.16 76.545 45.36 76.815 ;
     RECT  2.16 77.085 45.36 77.355 ;
     RECT  2.16 77.625 45.36 77.895 ;
     RECT  2.16 78.165 45.36 78.435 ;
     RECT  2.16 78.705 45.36 78.975 ;
     RECT  2.16 79.245 45.36 79.515 ;
     RECT  2.16 79.785 45.36 79.92 ;
    LAYER RVTP ;
     RECT  2.16 2.295 45.36 2.565 ;
     RECT  2.16 2.835 45.36 3.105 ;
     RECT  2.16 3.375 45.36 3.645 ;
     RECT  2.16 3.915 45.36 4.185 ;
     RECT  2.16 4.455 45.36 4.725 ;
     RECT  2.16 4.995 45.36 5.265 ;
     RECT  2.16 5.535 45.36 5.805 ;
     RECT  2.16 6.075 45.36 6.345 ;
     RECT  2.16 6.615 45.36 6.885 ;
     RECT  2.16 7.155 45.36 7.425 ;
     RECT  2.16 7.695 45.36 7.965 ;
     RECT  2.16 8.235 45.36 8.505 ;
     RECT  2.16 8.775 45.36 9.045 ;
     RECT  2.16 9.315 45.36 9.585 ;
     RECT  2.16 9.855 45.36 10.125 ;
     RECT  2.16 10.395 45.36 10.665 ;
     RECT  2.16 10.935 45.36 11.205 ;
     RECT  2.16 11.475 45.36 11.745 ;
     RECT  2.16 12.015 45.36 12.285 ;
     RECT  2.16 12.555 45.36 12.825 ;
     RECT  2.16 13.095 45.36 13.365 ;
     RECT  2.16 13.635 45.36 13.905 ;
     RECT  2.16 14.175 45.36 14.445 ;
     RECT  2.16 14.715 45.36 14.985 ;
     RECT  2.16 15.255 45.36 15.525 ;
     RECT  2.16 15.795 45.36 16.065 ;
     RECT  2.16 16.335 45.36 16.605 ;
     RECT  2.16 16.875 45.36 17.145 ;
     RECT  2.16 17.415 45.36 17.685 ;
     RECT  2.16 17.955 45.36 18.225 ;
     RECT  2.16 18.495 45.36 18.765 ;
     RECT  2.16 19.035 45.36 19.305 ;
     RECT  2.16 19.575 45.36 19.845 ;
     RECT  2.16 20.115 45.36 20.385 ;
     RECT  2.16 20.655 45.36 20.925 ;
     RECT  2.16 21.195 45.36 21.465 ;
     RECT  2.16 21.735 45.36 22.005 ;
     RECT  2.16 22.275 45.36 22.545 ;
     RECT  2.16 22.815 45.36 23.085 ;
     RECT  2.16 23.355 45.36 23.625 ;
     RECT  2.16 23.895 45.36 24.165 ;
     RECT  2.16 24.435 45.36 24.705 ;
     RECT  2.16 24.975 45.36 25.245 ;
     RECT  2.16 25.515 45.36 25.785 ;
     RECT  2.16 26.055 45.36 26.325 ;
     RECT  2.16 26.595 45.36 26.865 ;
     RECT  2.16 27.135 45.36 27.405 ;
     RECT  2.16 27.675 45.36 27.945 ;
     RECT  2.16 28.215 45.36 28.485 ;
     RECT  2.16 28.755 45.36 29.025 ;
     RECT  2.16 29.295 45.36 29.565 ;
     RECT  2.16 29.835 45.36 30.105 ;
     RECT  2.16 30.375 45.36 30.645 ;
     RECT  2.16 30.915 45.36 31.185 ;
     RECT  2.16 31.455 45.36 31.725 ;
     RECT  2.16 31.995 45.36 32.265 ;
     RECT  2.16 32.535 45.36 32.805 ;
     RECT  2.16 33.075 45.36 33.345 ;
     RECT  2.16 33.615 45.36 33.885 ;
     RECT  2.16 34.155 45.36 34.425 ;
     RECT  2.16 34.695 45.36 34.965 ;
     RECT  2.16 35.235 45.36 35.505 ;
     RECT  2.16 35.775 45.36 36.045 ;
     RECT  2.16 36.315 45.36 36.585 ;
     RECT  2.16 36.855 45.36 37.125 ;
     RECT  2.16 37.395 45.36 37.665 ;
     RECT  2.16 37.935 45.36 38.205 ;
     RECT  2.16 38.475 45.36 38.745 ;
     RECT  2.16 39.015 45.36 39.285 ;
     RECT  2.16 39.555 45.36 39.825 ;
     RECT  2.16 40.095 45.36 40.365 ;
     RECT  2.16 40.635 45.36 40.905 ;
     RECT  2.16 41.175 45.36 41.445 ;
     RECT  2.16 41.715 45.36 41.985 ;
     RECT  2.16 42.255 45.36 42.525 ;
     RECT  2.16 42.795 45.36 43.065 ;
     RECT  2.16 43.335 45.36 43.605 ;
     RECT  2.16 43.875 45.36 44.145 ;
     RECT  2.16 44.415 45.36 44.685 ;
     RECT  2.16 44.955 45.36 45.225 ;
     RECT  2.16 45.495 45.36 45.765 ;
     RECT  2.16 46.035 45.36 46.305 ;
     RECT  2.16 46.575 45.36 46.845 ;
     RECT  2.16 47.115 45.36 47.385 ;
     RECT  2.16 47.655 45.36 47.925 ;
     RECT  2.16 48.195 45.36 48.465 ;
     RECT  2.16 48.735 45.36 49.005 ;
     RECT  2.16 49.275 45.36 49.545 ;
     RECT  2.16 49.815 45.36 50.085 ;
     RECT  2.16 50.355 45.36 50.625 ;
     RECT  2.16 50.895 45.36 51.165 ;
     RECT  2.16 51.435 45.36 51.705 ;
     RECT  2.16 51.975 45.36 52.245 ;
     RECT  2.16 52.515 45.36 52.785 ;
     RECT  2.16 53.055 45.36 53.325 ;
     RECT  2.16 53.595 45.36 53.865 ;
     RECT  2.16 54.135 45.36 54.405 ;
     RECT  2.16 54.675 45.36 54.945 ;
     RECT  2.16 55.215 45.36 55.485 ;
     RECT  2.16 55.755 45.36 56.025 ;
     RECT  2.16 56.295 45.36 56.565 ;
     RECT  2.16 56.835 45.36 57.105 ;
     RECT  2.16 57.375 45.36 57.645 ;
     RECT  2.16 57.915 45.36 58.185 ;
     RECT  2.16 58.455 45.36 58.725 ;
     RECT  2.16 58.995 45.36 59.265 ;
     RECT  2.16 59.535 45.36 59.805 ;
     RECT  2.16 60.075 45.36 60.345 ;
     RECT  2.16 60.615 45.36 60.885 ;
     RECT  2.16 61.155 45.36 61.425 ;
     RECT  2.16 61.695 45.36 61.965 ;
     RECT  2.16 62.235 45.36 62.505 ;
     RECT  2.16 62.775 45.36 63.045 ;
     RECT  2.16 63.315 45.36 63.585 ;
     RECT  2.16 63.855 45.36 64.125 ;
     RECT  2.16 64.395 45.36 64.665 ;
     RECT  2.16 64.935 45.36 65.205 ;
     RECT  2.16 65.475 45.36 65.745 ;
     RECT  2.16 66.015 45.36 66.285 ;
     RECT  2.16 66.555 45.36 66.825 ;
     RECT  2.16 67.095 45.36 67.365 ;
     RECT  2.16 67.635 45.36 67.905 ;
     RECT  2.16 68.175 45.36 68.445 ;
     RECT  2.16 68.715 45.36 68.985 ;
     RECT  2.16 69.255 45.36 69.525 ;
     RECT  2.16 69.795 45.36 70.065 ;
     RECT  2.16 70.335 45.36 70.605 ;
     RECT  2.16 70.875 45.36 71.145 ;
     RECT  2.16 71.415 45.36 71.685 ;
     RECT  2.16 71.955 45.36 72.225 ;
     RECT  2.16 72.495 45.36 72.765 ;
     RECT  2.16 73.035 45.36 73.305 ;
     RECT  2.16 73.575 45.36 73.845 ;
     RECT  2.16 74.115 45.36 74.385 ;
     RECT  2.16 74.655 45.36 74.925 ;
     RECT  2.16 75.195 45.36 75.465 ;
     RECT  2.16 75.735 45.36 76.005 ;
     RECT  2.16 76.275 45.36 76.545 ;
     RECT  2.16 76.815 45.36 77.085 ;
     RECT  2.16 77.355 45.36 77.625 ;
     RECT  2.16 77.895 45.36 78.165 ;
     RECT  2.16 78.435 45.36 78.705 ;
     RECT  2.16 78.975 45.36 79.245 ;
     RECT  2.16 79.515 45.36 79.785 ;
    LAYER M1 ;
     RECT  2.16 2.151 45.36 79.929 ;
    LAYER M2 ;
     RECT  0.067 34.74 0.103 34.758 ;
     RECT  0.067 35.901 0.103 35.919 ;
     RECT  0.103 4.23 0.139 4.248 ;
     RECT  0.103 6.822 0.139 7.416 ;
     RECT  0.103 10.251 0.139 10.269 ;
     RECT  0.103 12.834 0.139 12.852 ;
     RECT  0.103 23.67 0.139 23.688 ;
     RECT  0.103 25.56 0.139 25.578 ;
     RECT  0.103 31.122 0.139 31.14 ;
     RECT  0.103 32.472 0.139 34.758 ;
     RECT  0.103 50.13 0.139 50.148 ;
     RECT  0.103 55.26 0.139 55.278 ;
     RECT  0.103 56.34 0.139 56.358 ;
     RECT  0.103 63.09 0.139 63.108 ;
     RECT  0.139 32.202 0.167 34.758 ;
     RECT  0.139 4.23 0.175 4.41 ;
     RECT  0.103 5.58 0.175 5.598 ;
     RECT  0.139 25.488 0.175 25.578 ;
     RECT  0.103 48.78 0.175 48.798 ;
     RECT  0.139 49.86 0.175 50.688 ;
     RECT  0.139 55.26 0.175 56.898 ;
     RECT  0.103 8.208 0.203 8.226 ;
     RECT  0.175 4.23 0.211 5.868 ;
     RECT  0.139 6.786 0.211 7.416 ;
     RECT  0.175 24.75 0.211 25.578 ;
     RECT  0.175 38.988 0.211 39.006 ;
     RECT  0.139 23.562 0.247 23.688 ;
     RECT  0.211 24.48 0.247 25.578 ;
     RECT  0.103 71.46 0.347 71.478 ;
     RECT  0.247 23.562 0.535 25.578 ;
     RECT  0.103 27.882 0.535 28.476 ;
     RECT  0.211 43.578 0.535 43.596 ;
     RECT  0.103 44.352 0.535 44.37 ;
     RECT  0.175 48.78 0.535 50.688 ;
     RECT  0.175 51.642 0.535 51.66 ;
     RECT  0.139 62.982 0.535 63.108 ;
     RECT  0.103 69.462 0.535 69.48 ;
     RECT  0.139 12.834 0.571 13.59 ;
     RECT  0.139 31.122 0.571 31.374 ;
     RECT  0.167 32.202 0.571 34.65 ;
     RECT  0.103 35.901 0.571 36.504 ;
     RECT  0.535 48.78 0.571 51.66 ;
     RECT  0.175 55.188 0.571 56.898 ;
     RECT  0.139 10.251 0.599 10.314 ;
     RECT  0.571 35.901 0.599 37.08 ;
     RECT  0.103 46.746 0.599 46.764 ;
     RECT  0.103 53.604 0.599 53.622 ;
     RECT  0.211 38.952 0.607 39.006 ;
     RECT  0.599 36.486 0.635 37.08 ;
     RECT  0.571 12.366 1.687 13.59 ;
     RECT  1.687 12.33 1.723 13.59 ;
     RECT  0.823 60.084 1.723 60.102 ;
     RECT  1.723 46.89 1.759 46.908 ;
     RECT  1.759 46.89 1.795 47.61 ;
     RECT  1.723 59.742 2.011 60.102 ;
     RECT  1.723 11.952 2.119 13.59 ;
     RECT  0.571 31.122 2.155 34.65 ;
     RECT  0.211 4.23 2.16 7.92 ;
     RECT  2.083 9.09 2.16 9.108 ;
     RECT  0.599 10.296 2.16 10.314 ;
     RECT  2.119 11.754 2.16 13.59 ;
     RECT  1.975 14.652 2.16 14.67 ;
     RECT  0.823 22.212 2.16 22.23 ;
     RECT  0.535 23.562 2.16 26.046 ;
     RECT  0.535 27.216 2.16 28.476 ;
     RECT  0.211 30.15 2.16 30.168 ;
     RECT  2.155 31.122 2.16 34.722 ;
     RECT  0.635 37.062 2.16 37.08 ;
     RECT  1.723 38.142 2.16 38.16 ;
     RECT  0.607 38.952 2.16 39.24 ;
     RECT  0.535 43.578 2.16 44.37 ;
     RECT  1.795 46.89 2.16 47.88 ;
     RECT  0.571 48.672 2.16 51.66 ;
     RECT  1.723 53.262 2.16 53.28 ;
     RECT  0.571 54.882 2.16 56.898 ;
     RECT  0.103 58.662 2.16 58.68 ;
     RECT  2.011 59.742 2.16 60.3 ;
     RECT  0.535 62.982 2.16 63.144 ;
     RECT  0.103 64.368 2.16 64.386 ;
     RECT  0.535 67.95 2.16 67.968 ;
     RECT  0.535 69.3 2.16 69.48 ;
     RECT  0.571 73.512 2.16 73.53 ;
     RECT  2.16 2.151 45.36 79.929 ;
     RECT  45.36 8.856 45.383 9.108 ;
     RECT  45.36 48.276 45.383 58.014 ;
     RECT  45.36 10.746 45.599 31.176 ;
     RECT  45.36 32.274 45.743 34.686 ;
     RECT  45.36 60.354 45.779 64.224 ;
     RECT  45.383 9.09 45.887 9.108 ;
     RECT  45.743 32.274 45.887 32.49 ;
     RECT  45.36 65.016 46.067 71.244 ;
     RECT  45.36 35.478 46.139 39.744 ;
     RECT  46.067 65.016 46.211 70.524 ;
     RECT  45.599 10.746 46.247 22.806 ;
     RECT  46.247 10.746 46.283 12.474 ;
     RECT  45.779 60.354 46.679 64.044 ;
     RECT  45.743 33.246 46.715 34.686 ;
     RECT  46.139 35.478 46.715 39.114 ;
     RECT  46.679 60.354 46.715 63.954 ;
     RECT  46.247 13.446 46.751 22.806 ;
     RECT  45.599 23.634 46.751 23.886 ;
     RECT  45.599 24.786 46.751 31.176 ;
     RECT  46.715 33.246 46.751 33.264 ;
     RECT  46.715 34.164 46.751 34.686 ;
     RECT  46.715 35.478 46.751 38.394 ;
     RECT  45.383 48.276 46.751 50.148 ;
     RECT  45.383 50.976 46.751 58.014 ;
     RECT  46.715 60.354 46.751 61.722 ;
     RECT  46.715 62.586 46.751 63.954 ;
     RECT  46.211 67.068 46.751 70.524 ;
     RECT  46.751 16.506 46.787 17.019 ;
     RECT  46.751 19.08 46.787 22.806 ;
     RECT  46.751 23.67 46.787 23.886 ;
     RECT  46.751 24.786 46.787 25.272 ;
     RECT  46.751 27.918 46.787 31.176 ;
     RECT  45.887 32.472 46.787 32.49 ;
     RECT  46.751 35.478 46.787 36.108 ;
     RECT  46.751 50.976 46.787 55.584 ;
     RECT  46.751 60.354 46.787 60.876 ;
     RECT  46.751 61.704 46.787 61.722 ;
     RECT  46.751 67.068 46.787 68.004 ;
     RECT  45.36 74.322 46.787 79.776 ;
     RECT  46.787 24.786 46.823 24.804 ;
     RECT  46.787 50.976 46.823 52.812 ;
     RECT  46.787 60.624 46.823 60.876 ;
     RECT  46.787 67.068 46.823 67.824 ;
     RECT  46.787 74.322 46.823 76.104 ;
     RECT  46.787 53.946 46.859 55.584 ;
     RECT  46.823 60.858 46.859 60.876 ;
     RECT  46.823 67.068 46.859 67.086 ;
     RECT  46.787 77.166 46.859 79.614 ;
     RECT  46.283 10.746 46.895 12.384 ;
     RECT  46.823 74.322 46.895 75.654 ;
     RECT  46.823 51.246 46.931 52.434 ;
     RECT  46.895 75.474 46.931 75.654 ;
     RECT  46.895 11.952 46.967 12.384 ;
     RECT  46.751 13.446 47.003 14.544 ;
     RECT  46.931 51.786 47.003 52.434 ;
     RECT  46.751 56.574 47.155 58.014 ;
     RECT  45.36 58.896 47.155 59.454 ;
     RECT  46.751 69.876 47.227 70.524 ;
     RECT  46.787 19.08 47.291 22.194 ;
     RECT  47.155 56.574 47.291 59.454 ;
     RECT  45.36 72.306 47.291 72.756 ;
     RECT  46.859 77.166 47.291 78.624 ;
     RECT  46.751 17.766 47.327 18.324 ;
     RECT  47.291 19.08 47.327 22.032 ;
     RECT  46.787 27.918 47.327 30.564 ;
     RECT  47.291 56.646 47.327 59.454 ;
     RECT  47.291 78.444 47.327 78.624 ;
     RECT  46.751 34.506 47.335 34.686 ;
     RECT  47.327 19.08 47.363 19.494 ;
     RECT  47.327 20.736 47.363 22.032 ;
     RECT  47.327 28.764 47.363 30.402 ;
     RECT  46.751 48.978 47.363 50.148 ;
     RECT  46.211 65.016 47.363 65.934 ;
     RECT  47.227 69.876 47.363 70.668 ;
     RECT  47.291 72.396 47.363 72.756 ;
     RECT  46.967 11.952 47.399 11.97 ;
     RECT  47.327 17.766 47.399 17.946 ;
     RECT  47.363 19.08 47.399 19.134 ;
     RECT  47.363 20.736 47.399 21.492 ;
     RECT  47.327 27.918 47.399 27.936 ;
     RECT  47.363 29.376 47.399 30.024 ;
     RECT  46.751 37.476 47.399 38.034 ;
     RECT  47.363 48.978 47.399 49.266 ;
     RECT  47.327 56.646 47.399 57.474 ;
     RECT  47.327 58.581 47.399 58.599 ;
     RECT  47.327 59.436 47.399 59.454 ;
     RECT  47.363 65.916 47.399 65.934 ;
     RECT  46.895 74.322 47.399 74.412 ;
     RECT  47.327 78.444 47.399 78.462 ;
     RECT  46.787 16.686 47.435 17.019 ;
     RECT  47.399 19.116 47.435 19.134 ;
     RECT  47.399 20.736 47.435 21.114 ;
     RECT  46.787 23.67 47.435 23.688 ;
     RECT  47.399 29.736 47.435 30.024 ;
     RECT  47.335 34.506 47.435 34.794 ;
     RECT  46.787 36.09 47.435 36.108 ;
     RECT  47.399 37.476 47.435 37.809 ;
     RECT  47.363 50.13 47.435 50.148 ;
     RECT  47.003 51.786 47.435 52.389 ;
     RECT  46.859 55.566 47.435 55.584 ;
     RECT  47.399 57.456 47.435 57.474 ;
     RECT  46.751 62.586 47.435 62.694 ;
     RECT  46.751 63.936 47.435 63.954 ;
     RECT  47.363 65.016 47.435 65.034 ;
     RECT  47.363 69.876 47.435 70.362 ;
     RECT  47.363 72.504 47.435 72.756 ;
     RECT  47.291 77.166 47.435 77.616 ;
     RECT  47.399 49.248 47.471 49.266 ;
     RECT  47.435 51.786 47.471 51.804 ;
     RECT  47.399 74.322 47.471 74.34 ;
     RECT  47.435 77.598 47.471 77.616 ;
     RECT  46.895 10.746 47.507 10.764 ;
     RECT  47.003 13.95 47.507 14.544 ;
     RECT  47.435 17.001 47.507 17.019 ;
     RECT  47.399 17.928 47.507 17.946 ;
     RECT  47.435 21.096 47.507 21.114 ;
     RECT  46.751 26.568 47.507 26.586 ;
     RECT  47.435 29.736 47.507 29.754 ;
     RECT  47.435 37.791 47.507 37.809 ;
     RECT  45.36 41.076 47.507 41.094 ;
     RECT  47.435 69.876 47.507 69.894 ;
     RECT  47.435 72.738 47.507 72.756 ;
     RECT  46.931 75.636 47.507 75.654 ;
     RECT  46.859 79.596 47.507 79.614 ;
    LAYER M3 ;
     RECT  10.692 2.191 10.818 2.263 ;
     RECT  14.904 2.191 14.922 2.335 ;
     RECT  2.415 2.143 2.505 2.413 ;
     RECT  7.815 2.143 7.905 2.413 ;
     RECT  13.215 2.143 13.305 2.413 ;
     RECT  18.615 2.143 18.705 2.413 ;
     RECT  24.015 2.143 24.105 2.413 ;
     RECT  29.415 2.143 29.505 2.413 ;
     RECT  34.815 2.143 34.905 2.413 ;
     RECT  40.215 2.143 40.305 2.413 ;
     RECT  40.215 2.413 40.497 2.461 ;
     RECT  10.548 2.263 11.358 2.533 ;
     RECT  14.904 2.335 15.498 2.533 ;
     RECT  19.62 2.497 19.89 2.569 ;
     RECT  10.26 2.533 11.358 2.605 ;
     RECT  14.832 2.533 15.498 2.605 ;
     RECT  18.615 2.413 18.897 2.605 ;
     RECT  34.815 2.413 35.097 2.605 ;
     RECT  40.068 2.461 40.497 2.605 ;
     RECT  7.815 2.413 8.097 2.641 ;
     RECT  12.24 2.605 12.258 2.641 ;
     RECT  13.215 2.413 13.497 2.641 ;
     RECT  17.172 2.605 17.19 2.641 ;
     RECT  17.928 2.605 18.897 2.641 ;
     RECT  24.015 2.413 24.297 2.641 ;
     RECT  30.528 2.605 30.546 2.641 ;
     RECT  39.564 2.605 41.094 2.641 ;
     RECT  10.116 2.605 11.358 2.731 ;
     RECT  12.24 2.641 13.806 2.731 ;
     RECT  14.832 2.605 16.182 2.731 ;
     RECT  22.86 2.605 22.878 2.731 ;
     RECT  30.528 2.641 31.626 2.731 ;
     RECT  7.815 2.641 8.622 2.767 ;
     RECT  34.092 2.605 35.097 2.767 ;
     RECT  4.536 2.767 4.554 2.803 ;
     RECT  6.156 2.767 6.786 2.803 ;
     RECT  9.576 2.731 16.182 2.803 ;
     RECT  16.992 2.641 18.897 2.803 ;
     RECT  22.716 2.731 22.878 2.803 ;
     RECT  23.76 2.641 24.297 2.803 ;
     RECT  26.568 2.641 26.73 2.803 ;
     RECT  27.504 2.641 27.522 2.803 ;
     RECT  28.548 2.767 28.566 2.803 ;
     RECT  29.415 2.413 29.697 2.803 ;
     RECT  33.012 2.779 33.03 2.803 ;
     RECT  34.092 2.767 35.55 2.803 ;
     RECT  36.54 2.767 36.558 2.803 ;
     RECT  37.944 2.767 38.61 2.803 ;
     RECT  6.084 2.803 6.786 2.839 ;
     RECT  7.815 2.767 8.658 2.839 ;
     RECT  4.536 2.803 4.95 2.875 ;
     RECT  6.012 2.839 6.786 2.875 ;
     RECT  21.132 2.731 21.15 2.875 ;
     RECT  25.776 2.731 25.794 2.875 ;
     RECT  26.568 2.803 27.522 2.875 ;
     RECT  37.944 2.803 38.826 2.875 ;
     RECT  39.564 2.641 42.03 2.875 ;
     RECT  25.776 2.875 27.522 2.911 ;
     RECT  34.092 2.803 36.558 2.911 ;
     RECT  37.944 2.875 42.03 2.911 ;
     RECT  25.776 2.911 27.558 3.001 ;
     RECT  22.716 2.803 24.297 3.037 ;
     RECT  25.308 3.001 27.558 3.037 ;
     RECT  30.528 2.731 32.238 3.073 ;
     RECT  33.012 2.803 33.318 3.073 ;
     RECT  34.092 2.911 42.03 3.073 ;
     RECT  42.768 2.731 42.786 3.073 ;
     RECT  28.548 2.803 29.697 3.109 ;
     RECT  19.62 2.569 20.286 3.145 ;
     RECT  21.132 2.875 21.546 3.145 ;
     RECT  34.092 3.073 42.786 3.145 ;
     RECT  4.176 2.875 6.786 3.181 ;
     RECT  9.576 2.803 18.897 3.181 ;
     RECT  19.62 3.145 21.546 3.181 ;
     RECT  22.716 3.037 27.558 3.181 ;
     RECT  28.368 3.109 29.697 3.181 ;
     RECT  30.528 3.073 33.318 3.181 ;
     RECT  34.092 3.145 43.578 3.181 ;
     RECT  9.576 3.181 21.654 3.271 ;
     RECT  22.716 3.181 29.697 3.271 ;
     RECT  30.42 3.181 43.794 3.271 ;
     RECT  4.14 3.181 6.786 3.307 ;
     RECT  7.815 2.839 8.694 3.307 ;
     RECT  4.14 3.307 8.694 3.343 ;
     RECT  9.576 3.271 21.87 3.343 ;
     RECT  4.14 3.343 21.87 3.415 ;
     RECT  22.716 3.271 43.794 3.415 ;
     RECT  4.14 3.415 43.794 3.451 ;
     RECT  4.14 3.451 44.154 3.541 ;
     RECT  2.415 2.413 2.697 3.685 ;
     RECT  4.104 3.541 44.154 3.685 ;
     RECT  2.415 3.685 2.754 3.721 ;
     RECT  2.415 3.721 3.042 3.811 ;
     RECT  3.924 3.685 44.442 3.811 ;
     RECT  2.415 3.811 44.55 3.947 ;
     RECT  2.415 3.947 44.442 3.955 ;
     RECT  2.304 3.955 44.442 4.109 ;
     RECT  2.304 4.109 43.902 4.145 ;
     RECT  0.108 4.225 0.126 4.387 ;
     RECT  0.108 4.387 0.162 4.495 ;
     RECT  2.304 4.145 43.758 4.999 ;
     RECT  0.108 4.495 0.558 5.453 ;
     RECT  2.304 4.999 43.794 5.645 ;
     RECT  2.34 5.645 43.794 5.881 ;
     RECT  2.34 5.881 43.902 6.151 ;
     RECT  2.34 6.151 44.118 6.547 ;
     RECT  2.304 6.547 44.118 6.605 ;
     RECT  0.108 5.453 0.522 6.691 ;
     RECT  0.108 6.691 0.558 7.181 ;
     RECT  2.376 6.605 44.118 7.591 ;
     RECT  2.376 7.591 44.226 7.723 ;
     RECT  2.34 7.723 44.226 7.819 ;
     RECT  2.304 7.819 44.226 7.915 ;
     RECT  2.088 7.915 44.226 7.933 ;
     RECT  44.964 7.861 44.982 7.933 ;
     RECT  2.088 7.933 44.982 7.997 ;
     RECT  0.108 7.181 0.342 8.24 ;
     RECT  0.144 8.24 0.342 8.525 ;
     RECT  2.088 7.997 44.838 8.815 ;
     RECT  2.088 8.815 45.018 8.851 ;
     RECT  0.144 8.525 0.234 9.005 ;
     RECT  0.144 9.005 0.162 9.067 ;
     RECT  2.088 8.851 45.378 9.085 ;
     RECT  2.088 9.085 45.882 9.739 ;
     RECT  0.108 9.067 0.162 9.931 ;
     RECT  0.108 9.931 0.198 10.123 ;
     RECT  1.98 9.739 45.882 10.219 ;
     RECT  1.728 10.219 45.882 10.291 ;
     RECT  47.484 10.741 47.502 10.831 ;
     RECT  1.692 10.291 45.882 11.281 ;
     RECT  46.8 10.831 47.502 11.281 ;
     RECT  1.692 11.281 47.502 12.353 ;
     RECT  1.764 12.353 47.502 12.515 ;
     RECT  0.108 10.123 0.63 12.785 ;
     RECT  0.108 12.785 0.162 12.857 ;
     RECT  1.836 12.515 47.502 13.055 ;
     RECT  0.144 12.857 0.162 13.595 ;
     RECT  1.98 13.055 47.502 13.865 ;
     RECT  1.98 13.865 14.886 14.611 ;
     RECT  15.66 13.865 47.502 14.611 ;
     RECT  1.98 14.611 47.502 14.675 ;
     RECT  2.304 14.675 47.502 15.449 ;
     RECT  2.376 15.449 47.502 16.799 ;
     RECT  2.415 16.799 47.502 16.907 ;
     RECT  2.415 16.907 45.594 16.979 ;
     RECT  46.728 16.907 47.502 17.024 ;
     RECT  46.728 17.024 47.43 17.653 ;
     RECT  2.415 16.979 45.198 17.707 ;
     RECT  46.152 17.653 47.43 17.707 ;
     RECT  2.415 17.707 47.43 17.837 ;
     RECT  46.728 17.837 47.43 17.923 ;
     RECT  2.415 17.837 45.774 18.763 ;
     RECT  46.728 17.923 47.502 18.959 ;
     RECT  2.415 18.763 45.882 19.111 ;
     RECT  46.764 18.959 47.502 19.301 ;
     RECT  47.16 19.301 47.502 19.409 ;
     RECT  2.376 19.111 45.882 20.039 ;
     RECT  2.376 20.039 45.198 20.309 ;
     RECT  2.415 20.309 45.09 20.381 ;
     RECT  2.415 20.381 3.078 20.579 ;
     RECT  4.104 20.381 45.09 20.579 ;
     RECT  2.415 20.579 2.97 20.615 ;
     RECT  47.196 19.409 47.502 21.119 ;
     RECT  47.196 21.119 47.43 21.361 ;
     RECT  2.415 20.615 2.697 21.397 ;
     RECT  2.415 21.397 3.186 21.469 ;
     RECT  4.104 20.579 4.914 21.469 ;
     RECT  5.652 20.579 45.09 21.469 ;
     RECT  2.415 21.469 3.222 21.541 ;
     RECT  4.104 21.469 45.09 21.541 ;
     RECT  46.872 21.361 47.43 21.541 ;
     RECT  2.415 21.541 45.09 22.045 ;
     RECT  2.415 22.045 45.126 22.621 ;
     RECT  2.415 22.621 45.234 22.783 ;
     RECT  46.8 21.541 47.43 22.783 ;
     RECT  2.376 22.783 45.234 23.161 ;
     RECT  2.34 23.161 45.558 23.287 ;
     RECT  2.304 23.287 45.558 23.323 ;
     RECT  2.304 23.323 45.594 23.351 ;
     RECT  0.828 22.207 0.846 23.557 ;
     RECT  46.764 22.783 47.43 23.629 ;
     RECT  0.144 23.557 0.846 23.665 ;
     RECT  46.728 23.629 47.43 23.693 ;
     RECT  26.28 23.351 45.594 23.701 ;
     RECT  26.28 23.701 45.63 23.789 ;
     RECT  46.728 23.693 47.358 23.791 ;
     RECT  46.692 23.791 47.358 23.981 ;
     RECT  46.692 23.981 47.286 24.173 ;
     RECT  26.28 23.789 45.594 24.205 ;
     RECT  2.304 23.351 25.326 24.511 ;
     RECT  26.136 24.205 45.594 24.511 ;
     RECT  0.108 23.665 0.846 24.749 ;
     RECT  2.304 24.511 45.594 24.811 ;
     RECT  2.304 24.811 45.666 25.003 ;
     RECT  2.304 25.003 45.81 25.195 ;
     RECT  2.304 25.195 45.846 25.619 ;
     RECT  0.108 24.749 0.306 25.805 ;
     RECT  46.692 24.173 46.818 25.867 ;
     RECT  0.144 25.805 0.306 26.023 ;
     RECT  0.144 26.023 0.558 26.477 ;
     RECT  46.692 25.867 47.394 26.539 ;
     RECT  46.692 26.539 47.43 26.563 ;
     RECT  2.304 25.619 45.81 26.635 ;
     RECT  46.692 26.563 47.502 26.923 ;
     RECT  2.304 26.635 45.882 27.019 ;
     RECT  46.62 26.923 47.502 27.019 ;
     RECT  2.304 27.019 47.502 27.115 ;
     RECT  2.196 27.115 47.502 27.203 ;
     RECT  0.54 26.477 0.558 27.877 ;
     RECT  2.304 27.203 47.502 28.021 ;
     RECT  2.268 28.021 47.502 28.109 ;
     RECT  2.304 28.109 47.502 28.715 ;
     RECT  5.04 28.715 47.502 28.949 ;
     RECT  5.04 28.949 46.206 29.057 ;
     RECT  5.04 29.057 46.17 29.129 ;
     RECT  2.304 28.715 4.122 29.131 ;
     RECT  2.268 29.131 4.122 29.255 ;
     RECT  2.304 29.255 4.122 29.461 ;
     RECT  5.04 29.129 45.882 29.461 ;
     RECT  47.268 28.949 47.502 29.759 ;
     RECT  47.268 29.759 47.43 30.029 ;
     RECT  2.304 29.461 45.882 30.283 ;
     RECT  47.268 30.029 47.358 30.407 ;
     RECT  47.268 30.407 47.322 30.569 ;
     RECT  2.268 30.283 45.882 30.839 ;
     RECT  2.268 30.839 45.126 30.875 ;
     RECT  2.304 30.875 45.126 30.947 ;
     RECT  0.108 27.877 0.558 31.145 ;
     RECT  2.34 30.947 45.126 31.277 ;
     RECT  0.144 31.145 0.558 31.351 ;
     RECT  0.144 31.351 0.594 31.379 ;
     RECT  2.34 31.277 27.09 31.379 ;
     RECT  2.34 31.379 26.982 31.415 ;
     RECT  0.576 31.379 0.594 31.955 ;
     RECT  27.864 31.277 45.126 32.203 ;
     RECT  45.864 30.839 45.882 32.203 ;
     RECT  0.144 32.197 0.558 32.467 ;
     RECT  46.764 31.153 46.782 32.525 ;
     RECT  27.864 32.203 45.882 32.575 ;
     RECT  2.415 31.415 26.982 32.701 ;
     RECT  27.72 32.575 45.882 32.701 ;
     RECT  2.376 32.701 45.882 32.875 ;
     RECT  46.728 32.779 46.746 32.875 ;
     RECT  2.376 32.875 46.746 33.005 ;
     RECT  46.152 33.005 46.746 33.269 ;
     RECT  2.376 33.005 45.09 33.305 ;
     RECT  46.152 33.269 46.71 33.449 ;
     RECT  2.376 33.305 43.614 33.451 ;
     RECT  2.304 33.451 43.614 33.575 ;
     RECT  46.692 33.449 46.71 33.809 ;
     RECT  0.108 32.467 0.558 34.061 ;
     RECT  2.376 33.575 43.614 34.087 ;
     RECT  44.46 33.305 45.09 34.087 ;
     RECT  0.108 34.061 0.522 34.157 ;
     RECT  2.376 34.087 45.09 34.411 ;
     RECT  2.304 34.411 45.09 34.465 ;
     RECT  2.304 34.465 45.162 34.492 ;
     RECT  46.728 34.159 46.746 34.501 ;
     RECT  2.268 34.492 45.162 34.603 ;
     RECT  2.16 34.603 45.162 34.727 ;
     RECT  0.108 34.157 0.162 34.735 ;
     RECT  0.072 34.735 0.162 34.763 ;
     RECT  2.304 34.727 45.162 35.659 ;
     RECT  2.268 35.659 45.162 35.851 ;
     RECT  0.072 34.763 0.126 35.896 ;
     RECT  0.072 35.896 0.594 35.924 ;
     RECT  2.232 35.851 45.162 35.947 ;
     RECT  2.232 35.947 45.378 36.005 ;
     RECT  46.728 34.501 47.43 36.121 ;
     RECT  32.328 36.005 45.378 36.235 ;
     RECT  46.188 36.121 47.43 36.235 ;
     RECT  32.328 36.235 47.43 36.419 ;
     RECT  2.232 36.005 31.554 36.427 ;
     RECT  0.108 35.924 0.594 36.481 ;
     RECT  0.108 36.481 0.63 36.509 ;
     RECT  1.728 36.427 31.554 36.751 ;
     RECT  32.328 36.419 45.018 36.751 ;
     RECT  45.756 36.419 47.43 36.959 ;
     RECT  1.728 36.751 45.018 37.579 ;
     RECT  46.116 36.959 47.43 37.786 ;
     RECT  1.728 37.579 45.126 37.867 ;
     RECT  46.116 37.786 47.502 37.867 ;
     RECT  1.728 37.867 47.502 37.967 ;
     RECT  46.116 37.967 47.502 38.039 ;
     RECT  1.728 37.967 45.162 38.165 ;
     RECT  46.116 38.039 46.746 38.399 ;
     RECT  0.18 36.509 0.63 39.011 ;
     RECT  46.116 38.399 46.71 39.119 ;
     RECT  0.612 39.011 0.63 39.245 ;
     RECT  2.304 38.165 45.162 39.281 ;
     RECT  2.304 39.281 25.65 39.515 ;
     RECT  46.116 39.119 46.134 39.749 ;
     RECT  2.304 39.515 25.398 40.019 ;
     RECT  26.676 39.281 45.162 40.171 ;
     RECT  2.415 40.019 25.398 40.531 ;
     RECT  2.415 40.531 25.542 40.801 ;
     RECT  26.676 40.171 45.234 40.801 ;
     RECT  47.484 38.039 47.502 41.099 ;
     RECT  2.415 40.801 45.234 41.215 ;
     RECT  2.34 41.215 45.234 41.369 ;
     RECT  36.432 41.369 45.234 41.909 ;
     RECT  2.34 41.369 35.514 41.945 ;
     RECT  2.34 41.945 16.686 42.025 ;
     RECT  36.648 41.909 45.234 42.089 ;
     RECT  36.648 42.089 44.766 42.179 ;
     RECT  17.46 41.945 35.514 42.259 ;
     RECT  36.648 42.179 44.622 42.449 ;
     RECT  17.46 42.259 35.874 42.755 ;
     RECT  2.304 42.025 16.686 42.763 ;
     RECT  17.46 42.755 24.714 42.763 ;
     RECT  36.648 42.449 43.974 42.899 ;
     RECT  36.648 42.899 43.902 43.259 ;
     RECT  2.304 42.763 24.714 43.331 ;
     RECT  25.488 42.755 35.874 43.339 ;
     RECT  36.648 43.259 43.866 43.339 ;
     RECT  13.176 43.331 24.714 43.529 ;
     RECT  16.74 43.529 24.714 43.681 ;
     RECT  25.488 43.339 43.866 43.681 ;
     RECT  0.216 43.573 0.234 43.807 ;
     RECT  0.216 43.807 0.558 44.059 ;
     RECT  13.176 43.529 15.966 44.149 ;
     RECT  16.74 43.681 43.866 44.185 ;
     RECT  2.304 43.331 12.402 44.221 ;
     RECT  13.14 44.149 15.966 44.221 ;
     RECT  16.74 44.185 44.478 44.299 ;
     RECT  0.144 44.059 0.558 44.347 ;
     RECT  2.304 44.221 15.966 44.419 ;
     RECT  16.704 44.299 44.478 44.419 ;
     RECT  2.304 44.419 44.478 44.447 ;
     RECT  21.96 44.447 44.478 44.609 ;
     RECT  2.304 44.447 21.114 44.779 ;
     RECT  21.96 44.609 44.262 44.879 ;
     RECT  0.108 44.347 0.558 45.005 ;
     RECT  0.324 45.005 0.558 45.101 ;
     RECT  21.96 44.879 43.974 45.265 ;
     RECT  0.324 45.101 0.342 45.485 ;
     RECT  2.268 44.779 21.114 45.535 ;
     RECT  21.888 45.265 43.974 45.535 ;
     RECT  2.268 45.535 43.974 45.739 ;
     RECT  1.728 45.739 43.974 45.841 ;
     RECT  1.728 45.841 44.946 46.111 ;
     RECT  0.108 46.027 0.126 46.741 ;
     RECT  0.108 46.741 0.594 46.769 ;
     RECT  1.728 46.111 45.342 46.913 ;
     RECT  1.764 46.913 45.342 47.615 ;
     RECT  1.8 47.615 45.342 47.885 ;
     RECT  2.34 47.885 45.342 48.119 ;
     RECT  0.576 46.769 0.594 48.695 ;
     RECT  2.415 48.119 45.342 48.811 ;
     RECT  2.415 48.811 45.45 48.901 ;
     RECT  46.728 48.271 46.746 48.973 ;
     RECT  46.728 48.973 47.394 49.081 ;
     RECT  46.692 49.081 47.394 49.243 ;
     RECT  46.692 49.243 47.466 49.271 ;
     RECT  0.108 48.775 0.126 49.477 ;
     RECT  0.108 49.477 0.198 49.747 ;
     RECT  0.108 49.747 0.234 49.819 ;
     RECT  2.376 48.901 45.45 49.963 ;
     RECT  2.304 49.963 45.45 50.141 ;
     RECT  2.304 50.141 6.03 50.251 ;
     RECT  0.108 49.819 0.558 50.381 ;
     RECT  2.268 50.251 6.03 50.387 ;
     RECT  0.108 50.381 0.234 51.053 ;
     RECT  0.144 51.053 0.234 51.169 ;
     RECT  2.304 50.387 6.03 51.259 ;
     RECT  6.84 50.141 45.45 51.259 ;
     RECT  0.144 51.169 0.558 51.437 ;
     RECT  46.728 49.271 47.466 51.437 ;
     RECT  46.764 51.437 47.466 51.809 ;
     RECT  2.304 51.259 45.45 51.883 ;
     RECT  2.268 51.883 45.45 51.979 ;
     RECT  0.144 51.437 0.198 52.075 ;
     RECT  1.728 51.979 45.45 52.205 ;
     RECT  0.108 52.075 0.198 52.397 ;
     RECT  1.728 52.205 45.414 52.547 ;
     RECT  1.728 52.547 45.234 52.589 ;
     RECT  1.728 52.589 45.162 52.853 ;
     RECT  46.764 51.809 47.43 52.861 ;
     RECT  1.728 52.853 25.722 53.285 ;
     RECT  46.728 52.861 47.43 53.323 ;
     RECT  0.108 52.397 0.126 53.599 ;
     RECT  0.108 53.599 0.594 53.627 ;
     RECT  26.46 52.853 45.162 53.803 ;
     RECT  46.152 53.323 47.43 53.803 ;
     RECT  2.304 53.285 25.722 53.825 ;
     RECT  2.376 53.825 25.722 53.833 ;
     RECT  26.46 53.803 47.43 53.833 ;
     RECT  2.376 53.833 47.43 53.933 ;
     RECT  2.376 53.933 46.854 54.329 ;
     RECT  2.415 54.329 46.854 54.707 ;
     RECT  0.576 53.627 0.594 54.905 ;
     RECT  0.18 55.183 0.198 55.255 ;
     RECT  2.415 54.707 45.63 55.435 ;
     RECT  46.692 54.707 46.854 55.531 ;
     RECT  0.108 55.255 0.198 55.723 ;
     RECT  0.108 55.723 0.234 55.957 ;
     RECT  2.415 55.435 45.774 56.101 ;
     RECT  2.304 56.101 45.774 56.129 ;
     RECT  2.304 56.129 45.594 56.429 ;
     RECT  2.304 56.429 45.054 56.489 ;
     RECT  2.304 56.489 44.982 56.717 ;
     RECT  2.304 56.717 25.902 56.813 ;
     RECT  0.108 55.957 0.306 56.875 ;
     RECT  0.108 56.875 0.342 56.909 ;
     RECT  0.144 56.909 0.342 57.005 ;
     RECT  46.692 55.531 47.43 57.067 ;
     RECT  0.144 57.005 0.306 57.197 ;
     RECT  26.64 56.717 44.982 57.271 ;
     RECT  46.152 57.067 47.43 57.443 ;
     RECT  46.764 57.443 47.43 57.479 ;
     RECT  2.34 56.813 25.902 57.541 ;
     RECT  26.64 57.271 45.09 57.541 ;
     RECT  0.144 57.197 0.162 57.581 ;
     RECT  2.34 57.541 45.09 57.643 ;
     RECT  2.304 57.643 45.09 57.739 ;
     RECT  1.728 57.739 45.09 57.911 ;
     RECT  46.764 57.479 47.322 58.576 ;
     RECT  0.828 57.931 0.846 58.657 ;
     RECT  0.108 58.657 0.846 58.733 ;
     RECT  0.144 58.733 0.846 58.973 ;
     RECT  46.764 58.576 47.394 59.027 ;
     RECT  47.232 59.027 47.394 59.369 ;
     RECT  47.376 59.369 47.394 59.459 ;
     RECT  1.728 57.911 45.054 59.495 ;
     RECT  1.728 59.495 44.982 59.765 ;
     RECT  0.828 58.973 0.846 60.107 ;
     RECT  2.016 59.765 44.982 60.305 ;
     RECT  2.304 60.305 44.982 60.385 ;
     RECT  46.764 60.349 46.782 60.619 ;
     RECT  46.728 60.619 46.818 60.853 ;
     RECT  2.304 60.385 45.234 61.259 ;
     RECT  2.34 61.259 45.234 61.501 ;
     RECT  2.34 61.501 45.63 61.771 ;
     RECT  46.728 60.853 46.854 61.771 ;
     RECT  2.34 61.771 46.854 61.963 ;
     RECT  2.34 61.963 47.43 62.093 ;
     RECT  46.152 62.093 47.43 62.537 ;
     RECT  2.34 62.093 45.198 62.923 ;
     RECT  2.304 62.923 45.774 63.077 ;
     RECT  0.144 62.977 0.162 63.085 ;
     RECT  0.108 63.085 0.162 63.121 ;
     RECT  2.304 63.077 44.982 63.211 ;
     RECT  45.72 63.077 45.774 63.307 ;
     RECT  2.232 63.211 44.982 63.347 ;
     RECT  0.108 63.121 0.558 63.533 ;
     RECT  2.268 63.347 44.982 63.821 ;
     RECT  0.144 63.533 0.558 63.917 ;
     RECT  46.656 62.537 47.43 64.049 ;
     RECT  45.72 63.307 45.81 64.229 ;
     RECT  0.144 63.917 0.162 64.363 ;
     RECT  2.304 63.821 44.982 64.363 ;
     RECT  0.108 64.363 0.162 64.589 ;
     RECT  2.304 64.363 45.162 64.589 ;
     RECT  2.304 64.589 45.126 64.705 ;
     RECT  0.144 64.589 0.162 65.035 ;
     RECT  47.304 64.049 47.43 65.039 ;
     RECT  0.144 65.035 0.342 65.165 ;
     RECT  2.268 64.705 45.126 65.399 ;
     RECT  0.144 65.165 0.234 65.501 ;
     RECT  47.304 65.039 47.394 65.579 ;
     RECT  0.144 65.501 0.198 65.611 ;
     RECT  46.152 64.363 46.17 65.669 ;
     RECT  2.268 65.399 45.054 65.939 ;
     RECT  47.376 65.579 47.394 65.939 ;
     RECT  0.108 65.611 0.198 66.029 ;
     RECT  0.108 66.029 0.126 66.077 ;
     RECT  6.84 65.939 45.054 66.361 ;
     RECT  6.84 66.361 45.234 66.865 ;
     RECT  46.188 66.631 46.206 66.865 ;
     RECT  2.268 65.939 6.102 67.055 ;
     RECT  6.84 66.865 46.206 67.063 ;
     RECT  2.304 67.055 6.102 67.171 ;
     RECT  6.84 67.063 46.854 67.171 ;
     RECT  2.304 67.171 46.854 67.325 ;
     RECT  2.415 67.325 46.854 68.237 ;
     RECT  2.415 68.237 46.782 68.369 ;
     RECT  45.756 68.369 46.782 68.429 ;
     RECT  46.728 68.429 46.782 68.717 ;
     RECT  2.415 68.369 45.018 68.791 ;
     RECT  2.34 68.791 45.018 69.163 ;
     RECT  46.728 68.717 46.746 69.163 ;
     RECT  2.304 69.163 45.018 69.295 ;
     RECT  45.756 68.429 45.81 69.295 ;
     RECT  0.54 67.945 0.558 69.355 ;
     RECT  2.304 69.295 45.81 69.389 ;
     RECT  46.692 69.163 46.746 69.451 ;
     RECT  0.324 69.355 0.558 69.457 ;
     RECT  46.044 69.451 46.746 69.835 ;
     RECT  0.108 69.457 0.558 69.869 ;
     RECT  46.044 69.835 47.43 69.871 ;
     RECT  0.144 69.869 0.558 70.157 ;
     RECT  0.144 70.157 0.342 70.349 ;
     RECT  46.044 69.871 47.502 70.529 ;
     RECT  47.232 70.529 47.502 70.673 ;
     RECT  1.152 70.699 1.278 70.829 ;
     RECT  1.152 70.829 1.17 70.973 ;
     RECT  2.304 69.389 45.018 70.979 ;
     RECT  2.304 70.979 9.234 71.105 ;
     RECT  46.044 70.529 46.062 71.249 ;
     RECT  0.576 71.179 0.594 71.275 ;
     RECT  0.324 71.275 0.594 71.371 ;
     RECT  0.108 71.371 0.594 71.483 ;
     RECT  10.188 70.979 45.018 71.609 ;
     RECT  2.304 71.105 6.39 71.653 ;
     RECT  0.18 71.483 0.594 71.741 ;
     RECT  2.232 71.653 6.39 71.947 ;
     RECT  7.38 71.105 9.198 71.947 ;
     RECT  10.188 71.609 44.982 72.149 ;
     RECT  2.232 71.947 9.198 72.193 ;
     RECT  10.188 72.149 44.946 72.193 ;
     RECT  47.268 70.673 47.502 72.329 ;
     RECT  47.34 72.329 47.502 72.419 ;
     RECT  47.412 72.419 47.502 72.527 ;
     RECT  47.484 72.527 47.502 72.761 ;
     RECT  2.232 72.193 44.946 72.797 ;
     RECT  2.304 72.797 44.946 73.111 ;
     RECT  0.576 71.741 0.594 73.535 ;
     RECT  2.304 73.111 45.054 73.921 ;
     RECT  2.304 73.921 45.126 74.083 ;
     RECT  2.304 74.083 45.27 74.345 ;
     RECT  47.448 74.317 47.466 74.389 ;
     RECT  46.44 74.461 46.458 74.929 ;
     RECT  47.376 74.389 47.466 74.929 ;
     RECT  2.415 74.345 45.27 75.541 ;
     RECT  46.44 74.929 47.466 75.541 ;
     RECT  2.415 75.541 47.466 75.631 ;
     RECT  2.415 75.631 47.502 78.899 ;
     RECT  2.415 78.899 13.554 78.935 ;
     RECT  14.4 78.899 47.502 78.935 ;
     RECT  13.104 78.935 13.554 78.971 ;
     RECT  2.415 78.935 12.294 79.043 ;
     RECT  3.456 79.043 11.898 79.079 ;
     RECT  14.472 78.935 47.502 79.085 ;
     RECT  3.456 79.079 11.394 79.169 ;
     RECT  14.472 79.085 30.546 79.169 ;
     RECT  15.12 79.169 15.498 79.205 ;
     RECT  3.456 79.169 8.37 79.229 ;
     RECT  9.324 79.169 10.818 79.229 ;
     RECT  18.615 79.169 28.314 79.229 ;
     RECT  3.456 79.229 8.226 79.241 ;
     RECT  13.215 78.971 13.554 79.241 ;
     RECT  29.088 79.169 29.826 79.241 ;
     RECT  3.456 79.241 8.19 79.349 ;
     RECT  15.12 79.205 15.138 79.349 ;
     RECT  18.615 79.229 26.37 79.349 ;
     RECT  27.36 79.229 27.81 79.349 ;
     RECT  29.088 79.241 29.79 79.349 ;
     RECT  3.456 79.349 6.714 79.439 ;
     RECT  7.596 79.349 8.19 79.439 ;
     RECT  9.756 79.229 10.818 79.439 ;
     RECT  18.615 79.349 26.334 79.439 ;
     RECT  27.36 79.349 27.738 79.439 ;
     RECT  31.356 79.085 47.502 79.439 ;
     RECT  34.488 79.439 47.502 79.469 ;
     RECT  9.756 79.439 10.206 79.475 ;
     RECT  16.236 79.169 17.73 79.475 ;
     RECT  31.428 79.439 32.094 79.475 ;
     RECT  33.228 79.439 33.246 79.475 ;
     RECT  34.488 79.469 45.63 79.475 ;
     RECT  3.456 79.439 6.354 79.511 ;
     RECT  19.728 79.439 26.298 79.511 ;
     RECT  21.636 79.511 26.298 79.547 ;
     RECT  27.648 79.439 27.738 79.583 ;
     RECT  40.176 79.475 45.63 79.583 ;
     RECT  3.456 79.511 6.174 79.619 ;
     RECT  18.615 79.439 18.954 79.619 ;
     RECT  21.672 79.547 26.298 79.619 ;
     RECT  34.776 79.475 39.402 79.619 ;
     RECT  46.44 79.469 47.502 79.619 ;
     RECT  46.44 79.619 47.43 79.661 ;
     RECT  2.415 79.043 2.697 79.667 ;
     RECT  13.215 79.241 13.497 79.667 ;
     RECT  18.615 79.619 18.897 79.667 ;
     RECT  29.088 79.349 29.697 79.667 ;
     RECT  5.328 79.619 6.174 79.709 ;
     RECT  10.008 79.475 10.206 79.709 ;
     RECT  16.704 79.475 17.73 79.709 ;
     RECT  19.728 79.511 20.898 79.709 ;
     RECT  21.672 79.619 25.182 79.709 ;
     RECT  31.824 79.475 32.094 79.709 ;
     RECT  34.776 79.619 38.25 79.709 ;
     RECT  39.024 79.619 39.402 79.709 ;
     RECT  40.176 79.583 44.226 79.709 ;
     RECT  21.672 79.709 24.105 79.715 ;
     RECT  38.016 79.709 38.034 79.715 ;
     RECT  3.816 79.619 4.554 79.745 ;
     RECT  5.976 79.709 5.994 79.745 ;
     RECT  10.008 79.709 10.026 79.745 ;
     RECT  21.744 79.715 24.105 79.745 ;
     RECT  25.02 79.709 25.038 79.745 ;
     RECT  31.824 79.709 31.842 79.745 ;
     RECT  34.815 79.709 35.442 79.745 ;
     RECT  39.24 79.709 39.258 79.745 ;
     RECT  40.215 79.709 41.814 79.745 ;
     RECT  42.732 79.709 44.226 79.745 ;
     RECT  21.744 79.745 22.842 79.757 ;
     RECT  40.215 79.745 41.022 79.757 ;
     RECT  19.728 79.709 19.746 79.768 ;
     RECT  4.356 79.745 4.374 79.781 ;
     RECT  22.824 79.757 22.842 79.781 ;
     RECT  27.72 79.583 27.738 79.781 ;
     RECT  29.088 79.667 29.505 79.781 ;
     RECT  34.815 79.745 35.334 79.781 ;
     RECT  41.796 79.745 41.814 79.781 ;
     RECT  42.732 79.745 42.75 79.781 ;
     RECT  45 79.583 45.63 79.781 ;
     RECT  45.216 79.781 45.63 79.853 ;
     RECT  7.776 79.439 8.19 79.889 ;
     RECT  40.215 79.757 40.986 79.889 ;
     RECT  2.415 79.667 2.505 79.937 ;
     RECT  7.815 79.889 8.19 79.937 ;
     RECT  13.215 79.667 13.305 79.937 ;
     RECT  18.615 79.667 18.705 79.937 ;
     RECT  24.015 79.745 24.105 79.937 ;
     RECT  29.415 79.781 29.505 79.937 ;
     RECT  34.815 79.781 34.905 79.937 ;
     RECT  40.215 79.889 40.305 79.937 ;
     RECT  45.612 79.853 45.63 79.949 ;
     RECT  8.172 79.937 8.19 80.045 ;
     RECT  46.44 79.661 47.322 80.045 ;
     RECT  46.764 80.045 47.322 80.237 ;
     RECT  47.232 80.237 47.322 80.429 ;
     RECT  47.232 80.429 47.25 80.525 ;
    LAYER M4 ;
     RECT  0.06 62.928 0.097 65.928 ;
     RECT  0.06 5.328 0.137 11.4 ;
     RECT  0.06 56.016 0.137 59.016 ;
     RECT  0.137 5.424 0.569 11.4 ;
     RECT  0.06 32.784 0.569 36.744 ;
     RECT  0.06 69.072 0.569 72.072 ;
     RECT  2.293 38.784 2.365 38.808 ;
     RECT  0.06 49.872 2.365 52.872 ;
     RECT  0.097 62.928 2.365 66.072 ;
     RECT  0.569 5.616 2.408 11.4 ;
     RECT  2.285 13.632 2.408 13.656 ;
     RECT  2.293 14.688 2.408 14.904 ;
     RECT  2.365 15.984 2.408 16.008 ;
     RECT  0.06 24.528 2.408 30.6 ;
     RECT  0.569 33.264 2.408 36.744 ;
     RECT  2.365 38.784 2.408 39.24 ;
     RECT  0.06 43.728 2.408 46.728 ;
     RECT  2.365 48.96 2.408 52.872 ;
     RECT  0.137 56.112 2.408 59.016 ;
     RECT  2.365 60.912 2.408 60.936 ;
     RECT  2.365 62.16 2.408 66.072 ;
     RECT  0.569 69.168 2.408 72.072 ;
     RECT  2.408 2.148 2.512 79.932 ;
     RECT  2.512 2.418 2.704 79.662 ;
     RECT  2.704 5.76 2.765 12.216 ;
     RECT  2.704 22.992 2.765 25.32 ;
     RECT  2.704 28.272 2.765 30.072 ;
     RECT  2.765 22.992 2.801 25.032 ;
     RECT  2.704 13.296 2.819 18.984 ;
     RECT  2.704 32.448 2.819 41.064 ;
     RECT  2.765 6.816 2.837 12.216 ;
     RECT  2.704 26.352 2.837 27.144 ;
     RECT  2.765 28.464 2.873 30.072 ;
     RECT  2.819 13.296 2.88 18.792 ;
     RECT  2.837 6.864 2.909 12.216 ;
     RECT  2.873 29.04 2.909 30.072 ;
     RECT  2.704 55.872 2.909 59.016 ;
     RECT  2.704 60.24 2.917 66.744 ;
     RECT  2.704 42.288 2.945 45.288 ;
     RECT  2.704 69.408 2.945 72.36 ;
     RECT  2.909 6.864 3.053 8.856 ;
     RECT  2.909 9.888 3.089 12.216 ;
     RECT  2.945 44.4 3.089 45.288 ;
     RECT  2.704 52.176 3.089 54.6 ;
     RECT  2.837 26.352 3.125 26.568 ;
     RECT  2.909 29.04 3.125 29.352 ;
     RECT  3.089 44.4 3.125 44.664 ;
     RECT  2.945 69.408 3.125 70.344 ;
     RECT  3.125 29.04 3.197 29.112 ;
     RECT  2.909 57.408 3.197 58.632 ;
     RECT  2.704 48.096 3.233 50.184 ;
     RECT  2.819 32.448 3.413 39.528 ;
     RECT  2.704 75.696 3.436 76.776 ;
     RECT  2.917 62.16 3.485 66.744 ;
     RECT  3.485 62.64 3.491 66.744 ;
     RECT  3.053 7.44 3.521 8.856 ;
     RECT  2.945 71.376 3.521 72.36 ;
     RECT  3.491 66.72 3.629 66.744 ;
     RECT  3.125 44.448 3.665 44.664 ;
     RECT  3.089 10.896 3.697 12.216 ;
     RECT  2.88 13.296 3.697 18.168 ;
     RECT  2.945 42.288 3.733 43.272 ;
     RECT  3.491 62.64 3.737 65.16 ;
     RECT  3.436 76.752 3.737 76.776 ;
     RECT  3.733 42.144 3.761 43.272 ;
     RECT  2.704 47.088 3.769 47.112 ;
     RECT  3.233 48.096 3.769 49.032 ;
     RECT  2.704 67.776 3.769 68.376 ;
     RECT  2.704 74.064 3.805 74.088 ;
     RECT  2.819 41.04 3.809 41.064 ;
     RECT  3.769 67.776 3.809 68.424 ;
     RECT  3.769 47.088 3.913 49.032 ;
     RECT  2.917 60.24 3.913 61.032 ;
     RECT  2.801 22.992 3.923 24.648 ;
     RECT  3.521 8.304 3.925 8.856 ;
     RECT  3.089 9.888 3.925 9.912 ;
     RECT  3.923 24.528 3.949 24.648 ;
     RECT  3.769 25.68 3.949 25.704 ;
     RECT  3.233 50.16 3.949 50.184 ;
     RECT  2.704 78 3.949 78.024 ;
     RECT  2.765 5.76 3.953 5.784 ;
     RECT  3.697 10.896 3.953 18.168 ;
     RECT  3.925 8.304 3.971 9.912 ;
     RECT  3.923 22.992 3.985 23.304 ;
     RECT  3.761 42.096 3.985 43.272 ;
     RECT  3.089 52.416 3.985 54.6 ;
     RECT  2.909 55.872 3.985 56.328 ;
     RECT  3.971 9.168 3.989 9.912 ;
     RECT  3.737 62.64 4.025 64.488 ;
     RECT  3.953 10.896 4.057 15.528 ;
     RECT  3.521 72.336 4.057 72.36 ;
     RECT  3.949 24.528 4.061 25.704 ;
     RECT  3.949 50.16 4.061 50.76 ;
     RECT  3.953 16.848 4.093 18.168 ;
     RECT  3.949 76.992 4.117 78.024 ;
     RECT  2.704 79.2 4.117 79.224 ;
     RECT  3.769 19.776 4.129 19.8 ;
     RECT  3.436 75.696 4.129 75.768 ;
     RECT  3.985 52.416 4.165 56.328 ;
     RECT  3.197 58.08 4.201 58.632 ;
     RECT  3.913 60.24 4.237 61.08 ;
     RECT  4.093 16.848 4.273 18.216 ;
     RECT  4.165 52.368 4.273 56.328 ;
     RECT  4.201 58.08 4.273 59.208 ;
     RECT  4.237 60.24 4.273 61.176 ;
     RECT  4.061 24.528 4.277 25.56 ;
     RECT  4.025 62.64 4.277 64.152 ;
     RECT  4.093 3.552 4.309 3.576 ;
     RECT  3.809 67.872 4.309 68.424 ;
     RECT  3.125 69.408 4.309 70.008 ;
     RECT  3.413 32.448 4.313 39.432 ;
     RECT  4.129 19.776 4.355 20.568 ;
     RECT  2.704 21.696 4.355 21.72 ;
     RECT  4.273 27.792 4.381 27.816 ;
     RECT  3.197 29.088 4.381 29.112 ;
     RECT  3.985 22.8 4.417 23.304 ;
     RECT  4.061 50.736 4.417 50.76 ;
     RECT  4.273 60.24 4.453 61.464 ;
     RECT  4.277 62.64 4.453 63.864 ;
     RECT  3.913 46.896 4.489 49.032 ;
     RECT  4.309 3.552 4.525 4.152 ;
     RECT  4.381 27.792 4.525 29.112 ;
     RECT  3.665 44.448 4.525 44.472 ;
     RECT  4.309 31.056 4.597 31.08 ;
     RECT  4.201 5.904 4.633 6.168 ;
     RECT  3.985 42.048 4.669 43.272 ;
     RECT  4.525 44.4 4.669 44.472 ;
     RECT  4.273 52.368 4.669 59.208 ;
     RECT  4.453 60.24 4.669 63.864 ;
     RECT  3.805 74.064 4.693 74.184 ;
     RECT  4.669 42.048 4.709 44.472 ;
     RECT  4.417 50.736 4.709 51.288 ;
     RECT  4.453 66.192 4.709 66.216 ;
     RECT  4.597 31.056 4.777 31.464 ;
     RECT  4.273 16.848 4.813 18.792 ;
     RECT  4.355 19.776 4.813 19.8 ;
     RECT  4.057 10.8 4.817 15.528 ;
     RECT  4.817 11.424 4.853 15.528 ;
     RECT  4.669 52.368 4.853 63.864 ;
     RECT  4.853 11.424 4.889 15.24 ;
     RECT  4.525 27.312 4.921 29.112 ;
     RECT  4.853 62.064 4.924 63.864 ;
     RECT  4.921 27.312 4.929 29.592 ;
     RECT  4.777 30.96 4.929 31.464 ;
     RECT  4.309 67.872 4.957 70.008 ;
     RECT  4.525 2.88 4.993 4.152 ;
     RECT  3.989 9.168 5.065 9.816 ;
     RECT  4.633 40.512 5.137 40.536 ;
     RECT  4.889 11.424 5.141 14.568 ;
     RECT  4.813 16.848 5.141 19.8 ;
     RECT  4.853 52.368 5.164 61.08 ;
     RECT  4.129 75.456 5.173 75.768 ;
     RECT  4.277 25.536 5.177 25.56 ;
     RECT  4.709 51.168 5.177 51.288 ;
     RECT  5.164 60.24 5.177 61.08 ;
     RECT  4.993 2.88 5.209 4.488 ;
     RECT  4.633 5.904 5.209 6.456 ;
     RECT  5.065 9.072 5.221 9.816 ;
     RECT  4.957 67.392 5.228 70.008 ;
     RECT  4.709 42.048 5.281 44.424 ;
     RECT  5.141 16.992 5.285 19.8 ;
     RECT  5.228 67.392 5.315 70.776 ;
     RECT  4.277 24.528 5.317 24.552 ;
     RECT  5.221 8.784 5.324 9.816 ;
     RECT  5.177 51.264 5.353 51.288 ;
     RECT  5.164 52.368 5.353 58.728 ;
     RECT  4.693 74.064 5.353 74.328 ;
     RECT  5.173 75.456 5.353 75.96 ;
     RECT  5.285 19.776 5.357 19.8 ;
     RECT  5.137 40.464 5.389 40.536 ;
     RECT  5.281 41.712 5.389 44.424 ;
     RECT  5.324 8.784 5.411 10.344 ;
     RECT  4.057 72.336 5.425 72.936 ;
     RECT  5.411 8.784 5.461 9.816 ;
     RECT  5.209 2.88 5.465 6.456 ;
     RECT  4.417 21.984 5.533 23.304 ;
     RECT  5.317 24.528 5.533 25.32 ;
     RECT  5.465 3.408 5.569 6.456 ;
     RECT  5.141 11.424 5.637 14.472 ;
     RECT  5.425 72 5.641 72.936 ;
     RECT  5.353 74.064 5.641 75.96 ;
     RECT  4.489 46.896 5.649 49.56 ;
     RECT  5.353 51.264 5.699 58.728 ;
     RECT  4.117 76.992 5.701 79.224 ;
     RECT  5.649 46.896 5.74 49.992 ;
     RECT  5.641 72 5.749 75.96 ;
     RECT  5.701 76.992 5.749 79.464 ;
     RECT  5.569 3.408 5.789 6.984 ;
     RECT  5.461 8.304 5.789 9.816 ;
     RECT  4.313 35.28 5.789 39.432 ;
     RECT  5.749 72 5.789 79.464 ;
     RECT  5.789 72 5.795 78.648 ;
     RECT  5.637 11.424 5.857 11.832 ;
     RECT  5.315 67.392 5.861 70.344 ;
     RECT  5.389 40.464 5.897 44.424 ;
     RECT  5.789 35.28 5.933 39.096 ;
     RECT  4.929 27.312 5.969 31.464 ;
     RECT  5.857 11.376 6.005 11.832 ;
     RECT  5.861 69.408 6.077 70.344 ;
     RECT  5.177 60.768 6.149 61.08 ;
     RECT  5.789 3.552 6.217 6.984 ;
     RECT  5.789 8.304 6.217 8.808 ;
     RECT  5.969 27.6 6.217 31.464 ;
     RECT  4.313 32.448 6.217 34.152 ;
     RECT  6.133 15.648 6.22 15.672 ;
     RECT  4.924 62.4 6.253 63.864 ;
     RECT  6.217 27.6 6.289 34.152 ;
     RECT  5.699 55.728 6.325 58.728 ;
     RECT  6.289 27.6 6.329 34.248 ;
     RECT  5.795 73.488 6.329 78.648 ;
     RECT  6.217 20.976 6.361 21 ;
     RECT  5.861 67.392 6.365 68.376 ;
     RECT  5.74 49.152 6.397 49.992 ;
     RECT  6.253 62.256 6.505 63.864 ;
     RECT  5.789 9.792 6.545 9.816 ;
     RECT  5.533 21.984 6.563 25.32 ;
     RECT  6.563 23.28 6.577 25.32 ;
     RECT  6.325 55.728 6.577 59.592 ;
     RECT  6.149 60.768 6.577 60.792 ;
     RECT  5.897 44.16 6.685 44.424 ;
     RECT  5.077 45.648 6.685 45.672 ;
     RECT  5.699 51.264 6.685 54.6 ;
     RECT  6.577 55.728 6.685 60.792 ;
     RECT  6.217 3.552 6.689 8.808 ;
     RECT  6.005 11.376 6.725 11.448 ;
     RECT  6.361 20.544 6.757 21 ;
     RECT  5.74 46.896 6.757 48.12 ;
     RECT  6.397 49.152 6.757 50.136 ;
     RECT  6.077 69.744 6.757 70.344 ;
     RECT  5.285 16.992 6.793 18.696 ;
     RECT  6.757 19.776 6.793 21 ;
     RECT  5.637 12.864 6.829 14.472 ;
     RECT  6.793 16.848 6.829 21 ;
     RECT  6.563 21.984 6.829 22.056 ;
     RECT  6.685 44.16 6.829 45.672 ;
     RECT  6.757 46.896 6.829 50.136 ;
     RECT  6.365 67.392 6.853 68.184 ;
     RECT  6.689 3.6 6.865 8.808 ;
     RECT  6.853 66.48 6.865 68.184 ;
     RECT  5.933 36.192 7.081 39.096 ;
     RECT  5.897 40.464 7.081 43.032 ;
     RECT  6.329 74.112 7.081 78.648 ;
     RECT  7.081 36.192 7.261 43.032 ;
     RECT  6.829 44.16 7.261 50.136 ;
     RECT  6.685 71.952 7.333 71.976 ;
     RECT  6.685 51.264 7.381 60.792 ;
     RECT  6.505 62.016 7.381 65.016 ;
     RECT  6.649 15.552 7.477 15.576 ;
     RECT  6.829 16.848 7.477 22.056 ;
     RECT  7.333 71.952 7.585 72.84 ;
     RECT  7.381 51.264 7.621 65.016 ;
     RECT  6.329 29.568 7.657 34.248 ;
     RECT  7.657 29.568 7.693 34.92 ;
     RECT  7.261 36.192 7.693 50.136 ;
     RECT  6.757 69.744 7.765 70.68 ;
     RECT  6.865 3.6 7.808 9 ;
     RECT  6.725 11.424 7.808 11.448 ;
     RECT  6.829 12.528 7.808 14.472 ;
     RECT  7.477 15.552 7.808 22.056 ;
     RECT  6.577 23.28 7.808 26.232 ;
     RECT  6.329 27.6 7.808 28.44 ;
     RECT  7.693 29.568 7.808 50.136 ;
     RECT  7.621 51.264 7.808 65.16 ;
     RECT  6.865 66.384 7.808 68.184 ;
     RECT  7.765 69.216 7.808 70.68 ;
     RECT  7.585 71.904 7.808 72.84 ;
     RECT  7.081 74.112 7.808 78.696 ;
     RECT  7.808 2.148 7.912 79.932 ;
     RECT  7.912 2.418 8.101 79.932 ;
     RECT  8.101 2.418 8.104 80.04 ;
     RECT  8.104 56.304 8.201 80.04 ;
     RECT  8.104 11.76 8.243 19.128 ;
     RECT  8.243 15.6 8.284 19.128 ;
     RECT  8.005 81.696 8.291 81.96 ;
     RECT  8.201 73.248 8.387 79.8 ;
     RECT  8.387 74.112 8.435 79.8 ;
     RECT  8.291 81.936 8.435 81.96 ;
     RECT  8.201 56.304 8.561 72.216 ;
     RECT  8.104 29.568 8.705 44.616 ;
     RECT  8.561 56.304 8.813 70.296 ;
     RECT  8.705 35.232 8.957 44.616 ;
     RECT  8.957 35.232 8.993 44.424 ;
     RECT  8.104 2.736 9.065 10.728 ;
     RECT  8.104 20.304 9.133 28.248 ;
     RECT  8.705 29.568 9.133 34.152 ;
     RECT  8.993 35.424 9.137 44.424 ;
     RECT  8.243 11.76 9.277 14.472 ;
     RECT  8.284 15.792 9.277 19.128 ;
     RECT  8.104 45.6 9.317 55.272 ;
     RECT  8.435 74.112 9.353 79.224 ;
     RECT  8.813 66.912 9.389 70.296 ;
     RECT  9.137 35.712 9.497 44.424 ;
     RECT  8.561 71.28 9.529 72.216 ;
     RECT  9.529 71.28 9.601 72.456 ;
     RECT  9.353 74.112 9.601 78.696 ;
     RECT  9.277 11.76 9.637 19.128 ;
     RECT  9.133 20.304 9.637 34.152 ;
     RECT  9.389 70.08 9.637 70.296 ;
     RECT  9.601 71.28 9.637 78.696 ;
     RECT  9.637 11.76 9.641 34.152 ;
     RECT  9.065 2.736 9.713 10.344 ;
     RECT  9.317 45.84 10.001 55.272 ;
     RECT  9.713 8.784 10.033 10.344 ;
     RECT  9.641 32.448 10.033 34.152 ;
     RECT  9.641 11.76 10.037 31.272 ;
     RECT  10.037 11.76 10.109 23.4 ;
     RECT  9.497 35.712 10.177 35.736 ;
     RECT  10.037 24.384 10.217 31.272 ;
     RECT  9.637 70.08 10.217 78.696 ;
     RECT  10.033 8.784 10.249 10.44 ;
     RECT  10.109 11.76 10.249 19.128 ;
     RECT  10.033 32.448 10.307 34.344 ;
     RECT  9.497 37.2 10.357 44.424 ;
     RECT  10.001 45.84 10.357 55.224 ;
     RECT  9.389 66.912 10.357 68.808 ;
     RECT  10.217 70.08 10.357 78.504 ;
     RECT  10.357 37.2 10.361 55.224 ;
     RECT  10.249 8.784 10.403 19.128 ;
     RECT  10.177 35.328 10.465 35.736 ;
     RECT  10.357 66.912 10.501 78.504 ;
     RECT  10.465 35.232 10.573 35.736 ;
     RECT  10.361 37.2 10.573 48.84 ;
     RECT  10.217 24.768 10.609 31.272 ;
     RECT  10.307 32.448 10.609 33.912 ;
     RECT  10.403 15.984 10.613 19.128 ;
     RECT  10.501 66.576 10.613 78.504 ;
     RECT  8.813 56.304 10.717 65.592 ;
     RECT  10.613 66.576 10.717 73.272 ;
     RECT  10.573 35.232 10.787 48.84 ;
     RECT  10.787 35.232 10.793 44.424 ;
     RECT  10.717 56.304 10.793 73.272 ;
     RECT  10.787 45.552 10.829 48.84 ;
     RECT  10.109 20.544 10.873 23.4 ;
     RECT  10.361 49.824 10.901 55.224 ;
     RECT  9.713 2.736 11.005 7.8 ;
     RECT  10.403 8.784 11.005 14.808 ;
     RECT  10.901 50.064 11.005 55.224 ;
     RECT  10.793 56.304 11.005 72.984 ;
     RECT  11.005 50.064 11.045 72.984 ;
     RECT  10.829 45.552 11.081 48.792 ;
     RECT  10.613 74.304 11.189 78.504 ;
     RECT  10.793 35.232 11.405 39.336 ;
     RECT  11.189 74.304 11.441 78.456 ;
     RECT  11.441 74.304 11.549 78.12 ;
     RECT  11.549 74.304 11.585 77.976 ;
     RECT  10.613 15.984 11.653 18.504 ;
     RECT  10.609 24.768 11.653 33.912 ;
     RECT  11.405 36.336 11.729 39.336 ;
     RECT  11.005 2.736 11.765 14.808 ;
     RECT  11.045 61.68 11.797 72.984 ;
     RECT  11.585 74.304 11.797 75.816 ;
     RECT  11.797 61.68 11.801 75.816 ;
     RECT  11.653 24.48 11.833 33.912 ;
     RECT  10.873 20.544 11.837 23.16 ;
     RECT  11.653 15.984 11.893 19.464 ;
     RECT  11.837 21.216 11.939 23.16 ;
     RECT  11.939 22.032 11.941 23.16 ;
     RECT  11.833 24.336 11.941 33.912 ;
     RECT  11.941 22.032 11.981 33.912 ;
     RECT  11.729 36.672 11.989 39.336 ;
     RECT  10.793 40.32 11.989 44.424 ;
     RECT  11.765 3.936 12.053 14.808 ;
     RECT  11.045 50.064 12.053 60.696 ;
     RECT  11.981 22.224 12.085 33.912 ;
     RECT  11.405 35.232 12.085 35.352 ;
     RECT  11.801 70.272 12.125 73.56 ;
     RECT  11.585 76.992 12.161 77.976 ;
     RECT  12.053 4.464 12.193 14.808 ;
     RECT  11.893 15.984 12.193 19.56 ;
     RECT  11.989 36.672 12.233 44.424 ;
     RECT  12.053 50.064 12.409 58.2 ;
     RECT  12.053 59.568 12.445 60.696 ;
     RECT  11.801 61.68 12.445 69.24 ;
     RECT  11.081 45.744 12.517 48.792 ;
     RECT  12.409 49.824 12.517 58.2 ;
     RECT  12.161 77.04 12.913 77.976 ;
     RECT  12.085 22.224 13.093 35.352 ;
     RECT  12.125 73.536 13.093 73.56 ;
     RECT  11.801 74.544 13.093 75.816 ;
     RECT  12.125 70.272 13.129 72.216 ;
     RECT  13.093 73.536 13.129 75.816 ;
     RECT  11.765 2.736 13.208 2.76 ;
     RECT  12.193 4.464 13.208 19.56 ;
     RECT  13.093 21.84 13.208 35.352 ;
     RECT  12.233 36.672 13.208 42.552 ;
     RECT  12.233 44.16 13.208 44.424 ;
     RECT  12.517 45.744 13.208 58.2 ;
     RECT  12.445 59.568 13.208 69.24 ;
     RECT  13.129 70.272 13.208 75.816 ;
     RECT  12.913 77.04 13.208 78.408 ;
     RECT  13.208 2.148 13.312 79.932 ;
     RECT  13.312 2.418 13.504 79.662 ;
     RECT  13.504 2.832 13.619 19.896 ;
     RECT  13.619 3.312 13.673 5.592 ;
     RECT  13.504 21.12 13.745 65.256 ;
     RECT  13.745 36.576 13.817 65.208 ;
     RECT  13.817 53.568 14.321 65.208 ;
     RECT  13.745 21.12 14.357 35.448 ;
     RECT  13.619 6.672 14.605 19.896 ;
     RECT  14.357 21.12 14.605 22.104 ;
     RECT  13.504 70.608 14.605 73.032 ;
     RECT  14.605 6.672 14.785 22.104 ;
     RECT  14.357 23.136 14.785 35.448 ;
     RECT  13.817 36.576 14.785 52.536 ;
     RECT  13.673 3.312 14.821 4.392 ;
     RECT  13.673 5.52 14.821 5.592 ;
     RECT  14.785 23.136 14.821 52.536 ;
     RECT  14.321 53.568 14.821 65.16 ;
     RECT  13.504 66.24 14.857 69.432 ;
     RECT  14.605 70.608 14.857 73.56 ;
     RECT  13.504 74.544 14.857 78.744 ;
     RECT  14.785 6.624 14.867 22.104 ;
     RECT  14.821 3.312 14.929 5.592 ;
     RECT  14.867 6.624 14.929 19.992 ;
     RECT  14.821 23.136 14.969 65.16 ;
     RECT  14.929 3.312 15.145 19.992 ;
     RECT  14.857 66.24 15.149 78.744 ;
     RECT  14.969 61.824 15.349 65.16 ;
     RECT  15.149 66.24 15.349 69.864 ;
     RECT  15.149 70.944 15.401 78.744 ;
     RECT  15.401 73.536 15.469 78.744 ;
     RECT  15.145 2.832 15.683 19.992 ;
     RECT  14.969 23.136 15.875 60.696 ;
     RECT  14.867 21.12 15.901 22.104 ;
     RECT  15.875 23.136 15.941 42.84 ;
     RECT  15.875 44.16 16.009 60.696 ;
     RECT  15.349 61.824 16.009 69.864 ;
     RECT  15.683 11.232 16.049 19.992 ;
     RECT  15.469 73.536 16.085 78.936 ;
     RECT  15.901 21.024 16.117 22.104 ;
     RECT  16.117 21.024 16.225 22.152 ;
     RECT  15.941 23.136 16.225 42.552 ;
     RECT  16.225 21.024 16.229 42.552 ;
     RECT  15.401 70.944 16.355 72.36 ;
     RECT  16.009 44.16 16.625 69.864 ;
     RECT  16.625 44.16 16.661 66.36 ;
     RECT  16.085 73.776 16.693 78.936 ;
     RECT  16.625 67.584 16.729 69.864 ;
     RECT  16.355 70.944 16.729 71.736 ;
     RECT  16.229 21.024 16.801 27.384 ;
     RECT  16.661 44.16 16.837 66.12 ;
     RECT  15.683 2.832 16.841 10.152 ;
     RECT  16.837 43.92 16.981 66.12 ;
     RECT  16.693 73.776 17.089 79.224 ;
     RECT  16.049 11.232 17.165 19.8 ;
     RECT  16.981 43.536 17.171 66.12 ;
     RECT  16.841 3.792 17.237 10.152 ;
     RECT  17.089 73.008 17.309 79.224 ;
     RECT  16.229 28.416 17.317 42.552 ;
     RECT  17.171 43.536 17.317 51.24 ;
     RECT  17.237 3.84 17.345 10.152 ;
     RECT  17.309 77.04 17.345 79.224 ;
     RECT  16.801 20.976 17.413 27.384 ;
     RECT  17.317 28.416 17.413 51.24 ;
     RECT  17.165 11.232 17.417 19.56 ;
     RECT  17.345 3.84 17.453 7.704 ;
     RECT  17.413 20.976 17.453 51.24 ;
     RECT  16.729 67.584 17.521 71.736 ;
     RECT  17.521 67.584 17.701 71.832 ;
     RECT  17.171 52.512 18.205 66.12 ;
     RECT  17.309 73.008 18.349 75.72 ;
     RECT  17.453 3.84 18.493 4.392 ;
     RECT  17.453 5.568 18.493 7.704 ;
     RECT  17.701 67.248 18.493 71.832 ;
     RECT  18.493 67.248 18.565 72.024 ;
     RECT  18.349 73.008 18.565 75.96 ;
     RECT  18.493 3.408 18.608 4.392 ;
     RECT  18.493 5.52 18.608 7.704 ;
     RECT  17.345 8.784 18.608 10.152 ;
     RECT  17.417 11.232 18.608 14.76 ;
     RECT  17.417 15.792 18.608 19.56 ;
     RECT  17.453 21.024 18.608 51.24 ;
     RECT  18.205 52.512 18.608 66.216 ;
     RECT  18.565 67.248 18.608 75.96 ;
     RECT  17.345 77.04 18.608 79.032 ;
     RECT  18.608 2.148 18.712 79.932 ;
     RECT  18.712 2.418 18.904 79.662 ;
     RECT  18.904 52.176 19.065 65.064 ;
     RECT  18.904 3.408 19.091 50.712 ;
     RECT  19.091 15.888 19.361 50.712 ;
     RECT  19.091 3.408 19.469 14.904 ;
     RECT  18.904 67.344 19.541 75.96 ;
     RECT  19.541 69.264 19.564 75.96 ;
     RECT  19.065 53.52 19.613 65.064 ;
     RECT  19.564 69.264 19.649 69.528 ;
     RECT  18.904 77.04 19.717 79.662 ;
     RECT  19.541 67.344 20.077 68.232 ;
     RECT  19.564 70.8 20.149 75.96 ;
     RECT  19.717 77.04 20.149 79.752 ;
     RECT  20.149 70.8 20.153 79.752 ;
     RECT  19.469 11.184 20.221 14.904 ;
     RECT  19.361 15.888 20.221 35.256 ;
     RECT  20.153 74.16 20.225 79.752 ;
     RECT  19.361 36.576 20.257 50.712 ;
     RECT  19.065 52.176 20.257 52.536 ;
     RECT  20.257 36.576 20.291 52.536 ;
     RECT  20.077 66.528 20.329 68.232 ;
     RECT  20.221 11.184 20.473 35.256 ;
     RECT  20.291 36.576 20.473 44.664 ;
     RECT  20.225 74.304 20.477 79.752 ;
     RECT  20.291 45.84 20.621 52.536 ;
     RECT  20.153 70.8 20.621 73.128 ;
     RECT  19.613 53.664 20.689 65.064 ;
     RECT  20.329 66.24 20.689 68.232 ;
     RECT  19.469 3.408 20.693 10.152 ;
     RECT  20.473 11.184 20.693 44.664 ;
     RECT  20.693 8.736 20.797 10.152 ;
     RECT  20.693 11.184 20.797 42.552 ;
     RECT  20.693 44.16 20.801 44.664 ;
     RECT  20.689 53.664 20.941 68.232 ;
     RECT  20.797 8.736 20.945 42.552 ;
     RECT  20.941 53.664 20.977 68.28 ;
     RECT  19.649 69.264 20.977 69.288 ;
     RECT  20.621 70.8 21.049 71.352 ;
     RECT  20.945 8.736 21.089 23.208 ;
     RECT  21.049 70.512 21.233 71.352 ;
     RECT  20.621 72.72 21.233 73.128 ;
     RECT  20.621 52.176 21.265 52.536 ;
     RECT  20.977 53.664 21.265 69.288 ;
     RECT  20.945 24.48 21.341 42.552 ;
     RECT  21.233 70.8 21.341 71.352 ;
     RECT  21.265 52.176 21.377 69.288 ;
     RECT  20.477 74.736 21.517 79.752 ;
     RECT  20.621 45.84 21.692 51 ;
     RECT  21.089 8.736 21.7 22.728 ;
     RECT  21.692 45.84 21.733 51.144 ;
     RECT  20.693 3.408 21.773 7.704 ;
     RECT  21.733 45.6 21.779 51.144 ;
     RECT  21.341 35.184 21.841 42.552 ;
     RECT  20.801 44.16 21.841 44.424 ;
     RECT  21.773 3.408 21.845 7.224 ;
     RECT  21.341 70.848 21.949 71.352 ;
     RECT  21.841 35.184 22.028 44.424 ;
     RECT  21.779 45.6 22.028 51 ;
     RECT  21.233 72.768 22.057 73.128 ;
     RECT  22.028 35.184 22.115 51 ;
     RECT  21.7 8.688 22.201 22.728 ;
     RECT  22.057 72.768 22.201 73.56 ;
     RECT  21.517 74.64 22.201 79.752 ;
     RECT  22.201 72.768 22.205 79.752 ;
     RECT  22.205 72.768 22.211 76.056 ;
     RECT  22.201 8.688 22.237 23.16 ;
     RECT  21.341 24.48 22.237 34.2 ;
     RECT  22.115 35.184 22.241 44.424 ;
     RECT  22.205 77.04 22.241 79.752 ;
     RECT  21.845 4.464 22.277 7.224 ;
     RECT  21.377 52.176 22.277 60.696 ;
     RECT  22.237 8.688 22.309 34.2 ;
     RECT  22.241 35.184 22.309 41.736 ;
     RECT  22.241 42.816 22.313 44.424 ;
     RECT  22.211 72.768 22.313 72.936 ;
     RECT  21.949 70.848 22.364 71.736 ;
     RECT  22.313 72.768 22.364 72.792 ;
     RECT  22.309 8.688 22.421 41.736 ;
     RECT  22.364 70.848 22.451 72.792 ;
     RECT  21.377 61.728 22.457 69.288 ;
     RECT  22.421 8.688 22.561 14.712 ;
     RECT  22.457 61.872 22.669 69.288 ;
     RECT  22.451 70.848 22.669 71.736 ;
     RECT  22.421 15.984 22.691 41.736 ;
     RECT  22.313 42.816 22.781 43.128 ;
     RECT  22.277 5.568 22.789 7.224 ;
     RECT  22.561 8.208 22.789 14.712 ;
     RECT  22.241 77.04 22.853 79.704 ;
     RECT  22.211 74.064 22.889 76.056 ;
     RECT  22.853 77.088 22.889 79.32 ;
     RECT  22.277 4.464 23.173 4.488 ;
     RECT  21.845 3.408 23.281 3.432 ;
     RECT  23.173 4.416 23.281 4.488 ;
     RECT  22.115 45.6 23.281 51 ;
     RECT  22.277 52.512 23.281 60.696 ;
     RECT  22.451 72.72 23.281 72.792 ;
     RECT  22.691 16.032 23.317 41.736 ;
     RECT  22.781 42.816 23.317 42.84 ;
     RECT  22.313 44.16 23.516 44.424 ;
     RECT  23.281 45.6 23.516 60.696 ;
     RECT  23.516 44.16 23.557 60.696 ;
     RECT  22.669 61.872 23.605 71.736 ;
     RECT  23.281 72.72 23.605 73.8 ;
     RECT  23.557 43.824 23.641 60.696 ;
     RECT  23.605 61.872 23.641 73.8 ;
     RECT  22.789 5.568 23.749 14.712 ;
     RECT  23.317 16.032 23.749 42.84 ;
     RECT  23.281 3.408 23.893 4.488 ;
     RECT  23.749 5.568 23.893 42.84 ;
     RECT  22.889 74.832 23.893 76.056 ;
     RECT  22.889 77.088 23.893 79.224 ;
     RECT  23.893 3.36 23.929 42.84 ;
     RECT  23.641 43.824 23.929 73.8 ;
     RECT  23.893 74.832 23.929 79.224 ;
     RECT  23.929 3.36 24.008 79.224 ;
     RECT  24.008 2.148 24.112 79.932 ;
     RECT  24.112 2.418 24.304 79.662 ;
     RECT  24.304 6.864 24.545 44.712 ;
     RECT  24.304 45.696 24.545 79.464 ;
     RECT  24.304 3.36 25.013 5.88 ;
     RECT  24.545 6.864 25.091 42.84 ;
     RECT  25.091 24.624 25.132 42.84 ;
     RECT  25.013 3.408 25.409 5.88 ;
     RECT  25.409 3.648 25.445 5.88 ;
     RECT  25.132 24.768 25.549 42.84 ;
     RECT  24.545 43.824 25.549 44.712 ;
     RECT  25.549 24.768 25.661 44.712 ;
     RECT  25.661 24.768 25.697 44.232 ;
     RECT  25.445 3.696 25.724 5.88 ;
     RECT  25.091 6.864 25.724 23.256 ;
     RECT  24.545 45.84 25.769 79.464 ;
     RECT  25.724 3.696 25.811 23.256 ;
     RECT  25.811 3.696 25.877 5.88 ;
     RECT  25.697 24.768 26.197 44.136 ;
     RECT  25.877 3.936 26.201 5.88 ;
     RECT  25.769 45.84 26.345 69.48 ;
     RECT  26.201 3.936 26.381 5.784 ;
     RECT  25.811 6.864 26.629 23.256 ;
     RECT  26.197 24.624 26.701 44.136 ;
     RECT  25.769 70.8 26.723 79.464 ;
     RECT  26.345 53.28 26.741 69.48 ;
     RECT  26.629 6.864 26.771 23.304 ;
     RECT  26.723 70.8 26.773 79.224 ;
     RECT  26.701 24.624 26.845 44.232 ;
     RECT  26.741 67.248 26.876 69.48 ;
     RECT  26.773 70.704 26.876 79.224 ;
     RECT  26.845 24.624 26.881 44.376 ;
     RECT  26.881 24.624 26.917 44.472 ;
     RECT  26.345 45.84 26.917 52.248 ;
     RECT  26.771 7.056 27.013 23.304 ;
     RECT  26.557 2.832 27.025 2.856 ;
     RECT  27.025 2.832 27.065 3.144 ;
     RECT  27.013 7.056 27.313 23.592 ;
     RECT  26.917 24.624 27.313 52.248 ;
     RECT  27.313 7.056 27.461 52.248 ;
     RECT  26.381 4.128 27.673 5.784 ;
     RECT  27.065 3.12 27.709 3.144 ;
     RECT  27.673 4.128 27.709 5.88 ;
     RECT  27.461 21.648 27.893 52.248 ;
     RECT  27.709 3.12 27.925 5.88 ;
     RECT  27.461 7.056 27.925 20.328 ;
     RECT  27.893 21.648 27.965 43.896 ;
     RECT  27.893 45.024 28.249 52.248 ;
     RECT  26.741 53.28 28.249 65.688 ;
     RECT  26.876 67.248 28.325 79.224 ;
     RECT  28.249 45.024 28.361 65.688 ;
     RECT  27.925 3.12 28.397 20.328 ;
     RECT  27.965 21.936 28.897 43.896 ;
     RECT  28.361 45.024 28.897 48.792 ;
     RECT  28.361 49.824 29.077 65.688 ;
     RECT  28.397 3.696 29.221 20.328 ;
     RECT  28.325 67.248 29.269 79.032 ;
     RECT  29.221 3.696 29.408 20.952 ;
     RECT  28.897 21.936 29.408 48.792 ;
     RECT  29.077 49.824 29.408 66.072 ;
     RECT  29.269 67.152 29.408 79.032 ;
     RECT  29.408 2.148 29.512 79.932 ;
     RECT  29.512 2.418 29.704 79.662 ;
     RECT  29.704 65.664 30.233 79.08 ;
     RECT  29.704 3.36 30.557 44.472 ;
     RECT  30.557 3.84 30.665 44.472 ;
     RECT  30.665 3.936 30.805 44.472 ;
     RECT  29.704 45.6 30.805 64.44 ;
     RECT  30.805 3.936 30.845 64.44 ;
     RECT  30.845 3.936 30.889 52.296 ;
     RECT  30.889 45.84 30.989 52.296 ;
     RECT  30.889 3.936 31.205 44.472 ;
     RECT  30.845 53.28 31.349 64.44 ;
     RECT  30.233 69.216 31.417 79.08 ;
     RECT  30.233 65.664 31.453 68.232 ;
     RECT  31.417 69.216 31.453 79.176 ;
     RECT  31.453 65.664 31.669 79.176 ;
     RECT  30.989 51.984 31.849 52.296 ;
     RECT  31.349 53.28 31.849 63.864 ;
     RECT  31.669 64.944 32.141 79.176 ;
     RECT  31.205 3.936 32.497 44.376 ;
     RECT  30.989 45.84 32.497 50.856 ;
     RECT  32.141 65.664 32.497 79.176 ;
     RECT  31.849 51.984 32.749 63.864 ;
     RECT  32.497 3.936 32.773 50.856 ;
     RECT  32.749 51.984 32.773 63.912 ;
     RECT  31.669 2.784 33.001 2.808 ;
     RECT  33.001 2.784 33.041 2.904 ;
     RECT  32.773 3.936 33.253 63.912 ;
     RECT  32.497 65.664 33.257 79.272 ;
     RECT  33.253 3.936 33.577 64.152 ;
     RECT  33.257 65.664 33.577 79.032 ;
     RECT  33.041 2.88 34.117 2.904 ;
     RECT  33.577 3.936 34.117 79.032 ;
     RECT  34.117 2.88 34.333 79.032 ;
     RECT  34.333 2.88 34.477 79.224 ;
     RECT  34.477 2.88 34.808 79.464 ;
     RECT  34.808 2.148 34.912 79.932 ;
     RECT  34.912 2.418 35.104 79.662 ;
     RECT  35.104 3.312 35.165 5.88 ;
     RECT  35.104 43.008 35.363 44.904 ;
     RECT  35.104 45.984 35.453 79.464 ;
     RECT  35.165 3.312 36.373 5.592 ;
     RECT  35.104 7.104 36.421 22.104 ;
     RECT  35.104 23.088 36.421 41.544 ;
     RECT  35.363 43.344 36.457 44.904 ;
     RECT  36.373 2.832 36.569 5.592 ;
     RECT  35.453 45.984 36.677 79.032 ;
     RECT  36.421 7.104 36.709 41.544 ;
     RECT  36.677 47.616 36.709 79.032 ;
     RECT  36.709 7.104 36.745 41.832 ;
     RECT  36.457 43.344 36.745 44.952 ;
     RECT  36.677 45.984 36.745 46.632 ;
     RECT  36.745 43.344 36.749 46.632 ;
     RECT  36.745 6.672 36.817 41.832 ;
     RECT  36.817 6.672 36.853 41.928 ;
     RECT  36.749 43.344 36.853 46.584 ;
     RECT  36.709 47.616 36.853 79.56 ;
     RECT  36.569 3.024 36.925 5.592 ;
     RECT  36.853 6.672 36.925 46.584 ;
     RECT  36.925 3.024 37.109 46.584 ;
     RECT  36.853 47.616 37.397 79.704 ;
     RECT  37.397 65.424 37.541 79.704 ;
     RECT  37.109 3.024 37.649 22.92 ;
     RECT  37.649 3.024 37.685 19.08 ;
     RECT  37.685 3.024 37.757 19.032 ;
     RECT  37.397 47.616 37.793 64.44 ;
     RECT  37.757 3.024 37.829 18.84 ;
     RECT  37.649 20.16 37.865 22.92 ;
     RECT  37.793 52.224 37.955 64.44 ;
     RECT  37.955 53.28 37.973 64.44 ;
     RECT  37.109 23.904 38.041 46.584 ;
     RECT  37.793 47.616 38.041 51.24 ;
     RECT  37.829 3.024 38.405 18.792 ;
     RECT  37.865 20.208 38.473 22.92 ;
     RECT  38.041 23.904 38.473 51.24 ;
     RECT  37.973 53.28 38.549 59.064 ;
     RECT  37.541 65.472 38.729 79.704 ;
     RECT  38.405 3.312 38.833 18.792 ;
     RECT  37.973 60.048 38.867 64.44 ;
     RECT  38.833 3.312 38.869 19.08 ;
     RECT  38.473 20.208 38.869 51.24 ;
     RECT  38.869 3.312 38.873 51.24 ;
     RECT  38.549 53.376 38.873 59.064 ;
     RECT  38.873 53.664 39.121 59.064 ;
     RECT  38.867 60.048 39.121 61.464 ;
     RECT  38.873 32.976 39.125 51.24 ;
     RECT  38.867 62.544 39.229 64.44 ;
     RECT  38.729 65.472 39.229 72.984 ;
     RECT  39.125 33.36 39.985 51.24 ;
     RECT  37.955 52.224 39.985 52.248 ;
     RECT  39.121 53.664 40.021 61.464 ;
     RECT  39.229 62.544 40.021 72.984 ;
     RECT  39.985 33.36 40.201 52.248 ;
     RECT  38.873 3.312 40.208 31.272 ;
     RECT  40.201 32.736 40.208 52.248 ;
     RECT  40.021 53.664 40.208 72.984 ;
     RECT  38.729 74.016 40.208 79.704 ;
     RECT  40.208 2.148 40.312 79.932 ;
     RECT  40.312 2.418 40.504 79.752 ;
     RECT  40.504 46.8 40.529 60.408 ;
     RECT  40.504 2.832 40.673 41.976 ;
     RECT  40.504 43.104 40.691 45.528 ;
     RECT  40.529 46.8 40.691 60.36 ;
     RECT  40.673 2.832 40.709 27.72 ;
     RECT  40.673 28.8 40.817 41.976 ;
     RECT  40.691 46.896 40.817 60.36 ;
     RECT  40.709 25.44 40.925 27.72 ;
     RECT  40.709 2.832 41.027 24.408 ;
     RECT  40.817 47.616 41.033 60.36 ;
     RECT  40.504 74.064 41.069 79.752 ;
     RECT  41.027 2.832 41.105 9.48 ;
     RECT  40.504 61.44 41.105 72.744 ;
     RECT  40.817 29.04 41.141 41.976 ;
     RECT  41.105 3.552 41.177 9.48 ;
     RECT  40.925 25.44 41.177 27.672 ;
     RECT  41.141 29.04 41.177 30.888 ;
     RECT  41.105 66.24 41.177 72.744 ;
     RECT  41.069 74.064 41.213 74.088 ;
     RECT  41.141 31.872 41.267 41.976 ;
     RECT  41.177 30.048 41.357 30.888 ;
     RECT  41.033 57.984 41.357 60.36 ;
     RECT  41.033 47.616 41.393 56.76 ;
     RECT  41.267 34.032 41.465 41.976 ;
     RECT  41.105 61.44 41.465 64.968 ;
     RECT  41.027 10.56 41.501 24.408 ;
     RECT  41.465 62.736 41.501 64.968 ;
     RECT  41.357 58.656 41.507 60.36 ;
     RECT  41.465 61.44 41.533 61.56 ;
     RECT  41.501 22.752 41.537 24.168 ;
     RECT  41.393 55.152 41.548 56.76 ;
     RECT  41.501 10.56 41.573 21.528 ;
     RECT  41.177 29.04 41.573 29.064 ;
     RECT  41.507 58.944 41.573 60.36 ;
     RECT  41.465 37.872 41.603 41.976 ;
     RECT  41.267 31.872 41.645 32.856 ;
     RECT  41.393 47.616 41.645 54.12 ;
     RECT  41.069 75.216 41.645 79.752 ;
     RECT  41.573 10.56 41.651 13.656 ;
     RECT  41.573 14.688 41.651 18.936 ;
     RECT  41.548 55.152 41.681 56.376 ;
     RECT  40.691 43.104 41.713 45.288 ;
     RECT  41.651 14.832 41.717 17.352 ;
     RECT  41.465 34.032 41.717 36.504 ;
     RECT  41.645 77.616 41.717 79.752 ;
     RECT  41.357 30.336 41.753 30.888 ;
     RECT  41.501 62.784 41.753 64.968 ;
     RECT  41.177 66.24 41.753 68.664 ;
     RECT  41.645 47.616 41.785 51.912 ;
     RECT  41.573 19.92 41.789 21.528 ;
     RECT  41.717 35.28 41.789 36.504 ;
     RECT  41.717 78.096 41.825 79.752 ;
     RECT  41.177 69.744 41.843 72.744 ;
     RECT  41.753 30.864 41.861 30.888 ;
     RECT  41.717 34.032 41.861 34.056 ;
     RECT  41.753 66.24 41.861 68.376 ;
     RECT  41.177 26.208 41.893 27.672 ;
     RECT  41.753 63.648 41.932 64.968 ;
     RECT  41.861 66.528 41.933 68.376 ;
     RECT  41.651 10.992 41.939 13.224 ;
     RECT  41.789 35.28 41.939 35.304 ;
     RECT  41.573 59.28 41.965 60.36 ;
     RECT  41.533 61.344 41.965 61.56 ;
     RECT  41.651 18.576 41.969 18.936 ;
     RECT  41.645 52.944 41.969 54.12 ;
     RECT  41.843 69.744 41.969 71.736 ;
     RECT  41.843 72.72 41.969 72.744 ;
     RECT  41.789 36.48 41.977 36.504 ;
     RECT  41.789 19.92 42.005 20.664 ;
     RECT  41.645 32.832 42.005 32.856 ;
     RECT  41.713 42.768 42.005 45.288 ;
     RECT  41.681 55.152 42.005 55.944 ;
     RECT  41.939 10.992 42.041 11.304 ;
     RECT  41.969 18.576 42.041 18.6 ;
     RECT  42.005 20.16 42.077 20.664 ;
     RECT  41.603 37.872 42.077 41.64 ;
     RECT  41.717 14.832 42.149 17.064 ;
     RECT  41.645 75.216 42.149 75.864 ;
     RECT  42.005 44.976 42.181 45.288 ;
     RECT  41.932 63.648 42.22 64.584 ;
     RECT  41.939 12.384 42.221 13.224 ;
     RECT  41.969 52.944 42.221 53.592 ;
     RECT  41.965 59.28 42.221 61.56 ;
     RECT  41.177 3.552 42.253 5.496 ;
     RECT  41.177 6.672 42.253 9.48 ;
     RECT  42.041 10.992 42.257 11.016 ;
     RECT  42.077 20.304 42.257 20.664 ;
     RECT  41.537 22.752 42.257 23.544 ;
     RECT  41.825 78.096 42.257 79.368 ;
     RECT  42.149 75.216 42.293 75.288 ;
     RECT  42.253 3.552 42.325 9.48 ;
     RECT  42.325 3.408 42.329 9.48 ;
     RECT  42.149 14.832 42.329 17.016 ;
     RECT  42.077 38.208 42.329 41.64 ;
     RECT  42.005 55.152 42.329 55.272 ;
     RECT  42.221 59.28 42.329 61.464 ;
     RECT  41.933 66.672 42.329 68.376 ;
     RECT  42.329 14.832 42.365 16.536 ;
     RECT  42.329 38.208 42.365 39.864 ;
     RECT  41.785 46.656 42.365 51.912 ;
     RECT  42.22 63.648 42.365 63.96 ;
     RECT  42.329 66.816 42.365 68.376 ;
     RECT  41.969 69.744 42.365 71.448 ;
     RECT  42.365 38.208 42.401 39.768 ;
     RECT  42.365 46.656 42.401 49.176 ;
     RECT  42.329 59.28 42.401 61.08 ;
     RECT  42.257 22.752 42.437 22.776 ;
     RECT  42.221 53.568 42.437 53.592 ;
     RECT  42.401 59.28 42.437 60.264 ;
     RECT  42.365 63.936 42.437 63.96 ;
     RECT  42.401 38.4 42.473 39.768 ;
     RECT  42.437 60.24 42.473 60.264 ;
     RECT  42.257 78.72 42.515 79.368 ;
     RECT  41.893 26.208 42.541 28.008 ;
     RECT  42.401 47.664 42.545 49.176 ;
     RECT  42.329 41.136 42.577 41.64 ;
     RECT  42.005 42.768 42.577 43.944 ;
     RECT  42.545 47.664 42.581 48.984 ;
     RECT  42.365 15.024 42.589 16.536 ;
     RECT  42.365 66.864 42.617 68.088 ;
     RECT  42.329 3.408 42.649 3.672 ;
     RECT  42.589 16.512 42.653 16.536 ;
     RECT  42.329 5.136 42.689 9.48 ;
     RECT  42.257 20.64 42.689 20.664 ;
     RECT  42.617 67.776 42.689 68.088 ;
     RECT  42.221 13.2 42.725 13.224 ;
     RECT  42.473 38.4 42.725 39.24 ;
     RECT  42.365 50.736 42.757 51.912 ;
     RECT  42.689 5.136 42.761 5.976 ;
     RECT  42.577 41.136 42.761 43.944 ;
     RECT  42.649 56.544 42.761 56.568 ;
     RECT  42.365 69.936 42.761 71.448 ;
     RECT  42.181 44.976 42.793 45.576 ;
     RECT  42.401 46.656 42.793 46.68 ;
     RECT  42.689 7.344 42.803 9.48 ;
     RECT  42.721 31.872 42.833 32.52 ;
     RECT  42.725 38.4 42.833 38.424 ;
     RECT  42.793 44.976 42.833 46.68 ;
     RECT  42.581 48.384 42.833 48.984 ;
     RECT  42.761 71.376 42.833 71.448 ;
     RECT  42.833 48.432 42.851 48.984 ;
     RECT  42.757 50.736 42.869 52.488 ;
     RECT  42.869 52.32 42.905 52.488 ;
     RECT  42.689 67.776 42.905 67.8 ;
     RECT  42.541 26.064 42.941 28.008 ;
     RECT  42.833 71.424 42.941 71.448 ;
     RECT  42.941 26.064 42.995 27.336 ;
     RECT  42.803 7.344 43.013 8.568 ;
     RECT  42.833 32.496 43.021 32.52 ;
     RECT  42.433 33.504 43.045 33.528 ;
     RECT  42.761 42.144 43.139 43.944 ;
     RECT  43.139 42.144 43.18 43.032 ;
     RECT  43.081 76.272 43.193 76.296 ;
     RECT  42.851 48.432 43.229 48.888 ;
     RECT  42.515 78.72 43.253 79.272 ;
     RECT  42.761 41.136 43.265 41.16 ;
     RECT  43.253 78.672 43.337 79.272 ;
     RECT  43.285 73.968 43.369 73.992 ;
     RECT  42.293 75.216 43.369 75.24 ;
     RECT  43.045 32.688 43.373 33.528 ;
     RECT  43.229 48.432 43.409 48.456 ;
     RECT  43.369 73.968 43.477 75.24 ;
     RECT  42.589 15.024 43.481 15.048 ;
     RECT  42.833 44.976 43.513 46.2 ;
     RECT  43.013 7.344 43.553 8.28 ;
     RECT  43.553 7.344 43.589 7.368 ;
     RECT  42.761 5.136 43.612 5.736 ;
     RECT  43.18 42.144 43.697 42.744 ;
     RECT  43.513 44.928 43.715 46.2 ;
     RECT  43.477 78.144 43.729 78.168 ;
     RECT  43.715 46.176 43.756 46.2 ;
     RECT  43.477 73.968 43.765 75.576 ;
     RECT  43.729 78.096 43.829 78.168 ;
     RECT  43.697 42.192 43.841 42.744 ;
     RECT  42.995 26.064 43.859 26.616 ;
     RECT  42.649 3.168 43.861 3.672 ;
     RECT  43.793 31.344 43.873 31.368 ;
     RECT  43.873 30.816 43.877 31.368 ;
     RECT  43.861 3.168 43.907 4.104 ;
     RECT  43.612 5.136 43.907 5.16 ;
     RECT  43.261 18.192 43.913 18.216 ;
     RECT  43.765 73.536 43.913 75.576 ;
     RECT  43.829 77.712 43.913 78.168 ;
     RECT  42.869 50.736 43.945 50.76 ;
     RECT  43.907 3.648 43.948 4.104 ;
     RECT  43.859 26.064 43.949 26.232 ;
     RECT  43.945 50.688 44.012 50.76 ;
     RECT  42.905 52.32 44.012 52.344 ;
     RECT  43.948 3.648 44.021 3.672 ;
     RECT  43.877 30.816 44.021 30.84 ;
     RECT  42.329 55.152 44.099 55.176 ;
     RECT  43.337 79.248 44.101 79.272 ;
     RECT  43.913 74.064 44.129 75.576 ;
     RECT  43.715 44.928 44.147 44.952 ;
     RECT  43.909 47.424 44.147 47.448 ;
     RECT  44.089 9.648 44.173 9.672 ;
     RECT  44.129 74.064 44.173 75.24 ;
     RECT  44.101 46.32 44.188 46.344 ;
     RECT  43.909 38.832 44.237 38.856 ;
     RECT  44.101 79.248 44.237 79.32 ;
     RECT  44.012 50.688 44.341 52.344 ;
     RECT  43.949 26.064 44.437 26.088 ;
     RECT  44.173 74.064 44.453 74.76 ;
     RECT  44.341 50.688 44.485 52.488 ;
     RECT  43.297 28.512 44.521 28.536 ;
     RECT  44.437 25.872 44.524 26.088 ;
     RECT  44.444 37.44 44.531 37.464 ;
     RECT  44.413 48.96 44.531 48.984 ;
     RECT  44.521 28.512 44.557 29.016 ;
     RECT  43.913 78.096 44.557 78.168 ;
     RECT  43.837 56.448 44.561 56.472 ;
     RECT  43.841 42.192 44.633 42.216 ;
     RECT  44.101 15.408 44.665 15.432 ;
     RECT  43.373 32.688 44.701 32.712 ;
     RECT  44.485 50.688 44.705 52.536 ;
     RECT  44.453 74.064 44.723 74.088 ;
     RECT  44.557 78.096 44.749 78.6 ;
     RECT  44.557 28.176 44.777 29.016 ;
     RECT  44.705 50.736 44.849 52.536 ;
     RECT  44.665 15.408 44.881 15.912 ;
     RECT  44.701 38.976 44.993 39 ;
     RECT  44.485 68.88 45.025 68.904 ;
     RECT  44.953 7.968 45.037 7.992 ;
     RECT  44.881 13.68 45.097 13.704 ;
     RECT  44.917 37.488 45.097 37.512 ;
     RECT  45.097 13.104 45.205 13.704 ;
     RECT  44.881 15.024 45.205 15.912 ;
     RECT  44.849 51.504 45.205 52.536 ;
     RECT  45.025 68.304 45.205 68.904 ;
     RECT  44.749 78.384 45.241 78.6 ;
     RECT  45.205 79.824 45.241 79.848 ;
     RECT  44.777 28.176 45.385 28.584 ;
     RECT  44.524 26.064 45.493 26.088 ;
     RECT  45.205 23.376 45.529 23.4 ;
     RECT  45.205 24.624 45.529 24.648 ;
     RECT  45.205 13.104 45.565 15.912 ;
     RECT  43.297 16.944 45.565 16.968 ;
     RECT  44.701 32.592 45.565 32.712 ;
     RECT  44.989 57.36 45.565 57.384 ;
     RECT  45.565 13.104 45.601 16.968 ;
     RECT  45.349 35.952 45.601 35.976 ;
     RECT  45.565 62.064 45.601 63.048 ;
     RECT  45.241 78.384 45.601 79.848 ;
     RECT  45.529 23.376 45.637 24.648 ;
     RECT  45.493 25.776 45.637 26.088 ;
     RECT  45.601 54.096 45.637 54.888 ;
     RECT  45.565 32.208 45.709 32.712 ;
     RECT  45.601 61.584 45.709 63.048 ;
     RECT  45.205 67.536 45.709 68.904 ;
     RECT  42.761 69.936 45.709 69.96 ;
     RECT  45.601 13.008 45.745 16.968 ;
     RECT  45.601 35.952 45.745 36.264 ;
     RECT  45.097 37.488 45.745 37.608 ;
     RECT  45.637 53.808 45.745 54.888 ;
     RECT  45.565 56.4 45.745 57.384 ;
     RECT  45.385 27.504 45.781 28.584 ;
     RECT  45.637 23.376 45.817 26.184 ;
     RECT  45.781 27.504 45.817 28.68 ;
     RECT  45.745 35.952 45.817 37.608 ;
     RECT  45.745 13.008 45.853 18.312 ;
     RECT  45.709 67.536 46.033 69.96 ;
     RECT  45.817 35.952 46.105 37.896 ;
     RECT  45.205 51.504 46.141 52.584 ;
     RECT  45.745 53.808 46.141 57.384 ;
     RECT  45.709 61.584 46.141 64.104 ;
     RECT  45.817 23.376 46.213 28.68 ;
     RECT  45.601 78.384 46.429 79.944 ;
     RECT  46.213 23.376 46.681 28.776 ;
     RECT  45.709 32.208 46.681 33 ;
     RECT  46.105 35.952 46.681 37.992 ;
     RECT  46.429 78.384 46.681 80.04 ;
     RECT  45.853 13.008 46.717 18.792 ;
     RECT  46.681 35.952 46.717 38.184 ;
     RECT  46.141 51.504 46.717 57.384 ;
     RECT  46.033 67.536 46.717 70.056 ;
     RECT  46.681 23.376 46.753 28.872 ;
     RECT  46.141 61.584 46.753 64.392 ;
     RECT  46.681 78 46.753 80.04 ;
     RECT  46.717 51.408 46.789 57.384 ;
     RECT  46.753 78 46.825 80.232 ;
     RECT  46.717 13.008 47.149 18.888 ;
     RECT  46.717 67.536 47.221 70.248 ;
     RECT  46.825 77.616 47.221 80.232 ;
     RECT  46.753 22.992 47.257 28.872 ;
     RECT  47.221 67.536 47.257 70.44 ;
     RECT  47.113 58.656 47.261 58.68 ;
     RECT  47.257 67.536 47.293 70.536 ;
     RECT  47.221 77.616 47.365 80.52 ;
     RECT  47.293 67.536 47.441 70.632 ;
     RECT  47.149 13.008 47.484 19.08 ;
     RECT  47.257 22.992 47.484 29.064 ;
     RECT  46.681 32.208 47.484 33.096 ;
     RECT  46.717 35.28 47.484 38.28 ;
     RECT  46.789 51.408 47.484 57.48 ;
     RECT  46.753 61.392 47.484 64.392 ;
     RECT  47.441 67.536 47.484 70.536 ;
     RECT  47.365 77.52 47.484 80.52 ;
    LAYER M5 ;
     RECT  2.4 2.137 2.52 2.151 ;
     RECT  7.8 2.137 7.92 2.151 ;
     RECT  13.2 2.137 13.32 2.151 ;
     RECT  18.6 2.137 18.72 2.151 ;
     RECT  24 2.137 24.12 2.151 ;
     RECT  29.4 2.137 29.52 2.151 ;
     RECT  34.8 2.137 34.92 2.151 ;
     RECT  40.2 2.137 40.32 2.151 ;
     RECT  13.2 2.151 13.512 2.821 ;
     RECT  40.2 2.151 40.512 2.821 ;
     RECT  10.704 2.725 10.824 2.867 ;
     RECT  40.2 2.821 41.064 3.301 ;
     RECT  24 2.151 24.312 3.349 ;
     RECT  29.4 2.151 29.712 3.349 ;
     RECT  18.6 2.151 18.912 3.397 ;
     RECT  34.8 2.151 35.112 3.397 ;
     RECT  36.384 2.821 36.408 3.587 ;
     RECT  10.704 2.867 10.728 4.115 ;
     RECT  34.8 3.397 35.208 4.307 ;
     RECT  39.312 3.301 41.064 4.355 ;
     RECT  5.76 3.685 5.784 4.357 ;
     RECT  33.744 2.869 33.768 4.403 ;
     RECT  5.76 4.357 6.408 4.499 ;
     RECT  7.8 2.151 8.112 4.549 ;
     RECT  5.76 4.499 5.784 4.595 ;
     RECT  18.6 3.397 19.656 4.933 ;
     RECT  29.4 3.349 29.832 4.933 ;
     RECT  16.368 4.645 17.16 4.979 ;
     RECT  7.056 4.549 8.112 5.029 ;
     RECT  29.4 4.933 30.072 5.075 ;
     RECT  33.696 4.501 33.72 5.125 ;
     RECT  43.872 3.157 43.896 5.125 ;
     RECT  39.312 4.355 40.92 5.171 ;
     RECT  43.536 5.125 43.896 5.171 ;
     RECT  7.056 5.029 8.232 5.219 ;
     RECT  25.728 4.117 25.752 5.219 ;
     RECT  18.6 4.933 21.144 5.221 ;
     RECT  33.024 5.125 33.72 5.699 ;
     RECT  10.656 5.077 10.68 5.747 ;
     RECT  16.368 4.979 16.392 5.747 ;
     RECT  18.6 5.221 21.192 5.747 ;
     RECT  43.536 5.171 43.56 5.747 ;
     RECT  29.4 5.075 29.832 5.795 ;
     RECT  20.4 5.747 21.192 6.085 ;
     RECT  22.8 5.653 22.824 6.085 ;
     RECT  33.024 5.699 33.048 6.323 ;
     RECT  7.8 5.219 8.232 6.419 ;
     RECT  13.2 2.821 13.608 6.517 ;
     RECT  20.4 6.085 22.824 6.755 ;
     RECT  26.736 5.749 26.76 6.805 ;
     RECT  40.2 5.171 40.92 6.805 ;
     RECT  6.432 5.605 6.456 6.899 ;
     RECT  25.776 6.805 26.76 6.899 ;
     RECT  23.904 3.349 24.312 6.901 ;
     RECT  25.776 6.899 25.8 6.901 ;
     RECT  23.904 6.901 25.8 6.947 ;
     RECT  24 6.947 25.8 7.091 ;
     RECT  16.416 6.181 16.44 7.237 ;
     RECT  13.104 6.517 13.608 7.381 ;
     RECT  37.872 6.661 37.896 7.909 ;
     RECT  39.024 5.893 39.048 7.909 ;
     RECT  12.528 7.381 13.608 7.957 ;
     RECT  20.4 6.755 20.424 8.293 ;
     RECT  40.2 6.805 41.496 8.341 ;
     RECT  0.144 8.245 0.168 8.531 ;
     RECT  32.688 6.709 32.712 8.579 ;
     RECT  29.4 5.795 29.712 8.677 ;
     RECT  37.872 7.909 39.048 8.677 ;
     RECT  22.032 6.755 22.824 8.723 ;
     RECT  24 7.091 25.08 8.723 ;
     RECT  37.44 8.677 39.048 8.965 ;
     RECT  5.232 5.077 5.256 9.061 ;
     RECT  34.8 4.307 35.112 9.061 ;
     RECT  40.2 8.341 41.688 9.061 ;
     RECT  42.768 7.333 42.792 9.061 ;
     RECT  37.44 8.965 39.144 9.155 ;
     RECT  3.936 8.293 3.96 9.203 ;
     RECT  20.4 8.293 20.616 9.299 ;
     RECT  40.2 9.061 42.792 9.491 ;
     RECT  44.976 7.957 45 9.637 ;
     RECT  12.528 7.957 14.28 9.779 ;
     RECT  5.232 9.061 5.688 9.827 ;
     RECT  16.416 7.237 17.256 9.923 ;
     RECT  16.416 9.923 16.44 10.021 ;
     RECT  28.944 8.677 29.712 10.307 ;
     RECT  5.232 9.827 5.4 10.355 ;
     RECT  39.12 9.155 39.144 10.453 ;
     RECT  40.2 9.491 42.552 10.453 ;
     RECT  39.12 10.453 42.552 10.691 ;
     RECT  33.12 9.637 33.144 10.883 ;
     RECT  34.8 9.061 35.64 10.883 ;
     RECT  15.648 10.021 16.44 10.979 ;
     RECT  29.4 10.307 29.712 11.365 ;
     RECT  39.12 10.691 39.144 11.459 ;
     RECT  18.6 5.747 18.912 11.557 ;
     RECT  9.936 6.229 9.96 11.653 ;
     RECT  9.936 11.653 10.872 11.797 ;
     RECT  12.528 9.779 13.512 11.939 ;
     RECT  40.2 10.691 42.552 11.941 ;
     RECT  9.936 11.797 11.016 12.035 ;
     RECT  34.8 10.883 35.352 12.035 ;
     RECT  5.232 10.355 5.256 12.133 ;
     RECT  5.232 12.133 5.592 12.179 ;
     RECT  28.656 11.365 29.712 12.179 ;
     RECT  13.104 11.939 13.512 12.277 ;
     RECT  10.368 12.035 11.016 12.515 ;
     RECT  7.8 6.419 8.112 12.517 ;
     RECT  18.6 11.557 19.368 12.563 ;
     RECT  38.496 11.749 38.52 12.757 ;
     RECT  40.032 11.941 42.552 12.757 ;
     RECT  6.864 12.517 8.112 13.043 ;
     RECT  38.496 12.757 42.552 13.091 ;
     RECT  13.104 12.277 13.704 13.093 ;
     RECT  20.592 9.299 20.616 13.381 ;
     RECT  16.416 10.979 16.44 13.429 ;
     RECT  15.408 12.517 15.432 13.475 ;
     RECT  2.4 2.151 2.712 13.621 ;
     RECT  34.8 12.035 35.112 13.621 ;
     RECT  44.112 9.637 45 13.715 ;
     RECT  33.888 13.621 35.112 13.813 ;
     RECT  36.432 13.045 36.456 13.813 ;
     RECT  37.44 9.155 37.464 13.813 ;
     RECT  36.432 13.813 37.464 13.859 ;
     RECT  16.416 13.429 16.488 13.909 ;
     RECT  10.368 12.515 10.392 13.955 ;
     RECT  33.696 13.813 35.112 14.003 ;
     RECT  36.432 13.859 37.32 14.099 ;
     RECT  7.8 13.043 8.112 14.629 ;
     RECT  2.304 13.621 2.712 14.677 ;
     RECT  18.6 12.563 18.912 14.773 ;
     RECT  20.592 13.381 21.048 14.773 ;
     RECT  12.048 14.005 12.072 14.819 ;
     RECT  2.304 14.677 2.856 14.915 ;
     RECT  25.968 14.917 25.992 14.965 ;
     RECT  13.104 13.093 13.944 15.395 ;
     RECT  16.032 13.909 16.488 15.443 ;
     RECT  44.112 13.715 44.136 15.443 ;
     RECT  18.6 14.773 21.048 15.491 ;
     RECT  5.568 12.179 5.592 15.637 ;
     RECT  16.464 15.443 16.488 15.827 ;
     RECT  25.968 14.965 26.52 15.877 ;
     RECT  31.2 7.189 31.224 15.877 ;
     RECT  22.032 8.723 22.056 15.973 ;
     RECT  2.4 14.915 2.856 16.019 ;
     RECT  25.488 15.877 26.52 16.019 ;
     RECT  32.496 13.861 32.52 16.019 ;
     RECT  40.2 13.091 42.552 16.019 ;
     RECT  34.8 14.003 35.112 16.117 ;
     RECT  34.704 16.117 35.112 16.307 ;
     RECT  33.696 14.003 33.72 16.501 ;
     RECT  40.2 16.019 41.688 16.501 ;
     RECT  18.6 15.491 20.616 16.787 ;
     RECT  16.608 15.877 16.632 16.835 ;
     RECT  29.136 12.179 29.712 16.837 ;
     RECT  29.136 16.837 29.976 16.883 ;
     RECT  37.296 14.099 37.32 16.885 ;
     RECT  25.968 16.019 26.52 16.981 ;
     RECT  39.888 16.501 41.688 17.027 ;
     RECT  25.968 16.981 27.336 17.029 ;
     RECT  5.568 15.637 6.168 17.075 ;
     RECT  25.632 17.029 27.336 17.075 ;
     RECT  24 8.723 24.312 17.077 ;
     RECT  25.632 17.075 25.992 17.077 ;
     RECT  5.568 17.075 5.592 17.123 ;
     RECT  27.312 17.075 27.336 17.123 ;
     RECT  10.368 15.349 10.392 17.171 ;
     RECT  34.8 16.307 35.112 17.461 ;
     RECT  37.008 16.885 37.32 17.461 ;
     RECT  13.2 15.395 13.944 17.605 ;
     RECT  7.8 14.629 8.232 17.653 ;
     RECT  39.888 17.027 41.64 17.699 ;
     RECT  6.816 17.653 8.232 17.795 ;
     RECT  20.592 16.787 20.616 17.893 ;
     RECT  31.152 15.877 31.224 17.987 ;
     RECT  17.472 17.605 17.496 17.989 ;
     RECT  18.6 16.787 19.08 17.989 ;
     RECT  6.816 17.795 8.112 18.179 ;
     RECT  33.024 16.501 33.72 18.565 ;
     RECT  34.8 17.461 35.496 18.565 ;
     RECT  33.024 18.565 35.496 18.611 ;
     RECT  24 17.077 25.992 18.659 ;
     RECT  39.888 17.699 41.496 18.709 ;
     RECT  2.4 16.019 2.712 18.757 ;
     RECT  17.472 17.989 19.08 18.851 ;
     RECT  2.4 18.757 2.808 18.995 ;
     RECT  17.472 18.851 18.912 19.043 ;
     RECT  29.4 16.883 29.976 19.141 ;
     RECT  25.44 18.659 25.992 19.187 ;
     RECT  31.2 17.987 31.224 19.235 ;
     RECT  29.04 19.141 29.976 19.283 ;
     RECT  33.696 18.611 35.496 19.285 ;
     RECT  36.48 17.461 37.32 19.285 ;
     RECT  13.2 17.605 14.856 19.427 ;
     RECT  33.696 19.285 37.32 19.427 ;
     RECT  22.032 15.973 22.68 19.525 ;
     RECT  32.688 18.709 32.712 19.571 ;
     RECT  34.08 19.427 37.32 19.811 ;
     RECT  24 18.659 24.312 19.813 ;
     RECT  25.44 19.187 25.656 19.813 ;
     RECT  20.496 17.893 20.616 19.909 ;
     RECT  22.032 19.525 23.016 19.909 ;
     RECT  20.496 19.909 23.016 19.955 ;
     RECT  39.216 18.709 41.496 20.149 ;
     RECT  26.784 19.333 26.808 20.341 ;
     RECT  26.784 20.341 27.336 20.387 ;
     RECT  29.4 19.283 29.976 20.387 ;
     RECT  6.864 18.179 8.112 20.579 ;
     RECT  9.648 18.757 9.672 20.579 ;
     RECT  34.8 19.811 37.32 20.579 ;
     RECT  14.832 19.427 14.856 20.867 ;
     RECT  20.592 19.955 23.016 20.915 ;
     RECT  34.8 20.579 36.84 20.915 ;
     RECT  39.216 20.149 41.592 20.915 ;
     RECT  39.312 20.915 41.592 21.107 ;
     RECT  34.8 20.915 35.352 21.155 ;
     RECT  40.2 21.107 41.592 21.203 ;
     RECT  11.904 19.525 11.928 21.251 ;
     RECT  36.48 20.915 36.84 21.299 ;
     RECT  24 19.813 25.656 21.395 ;
     RECT  20.592 20.915 21.144 21.443 ;
     RECT  36.816 21.299 36.84 21.541 ;
     RECT  36.816 21.541 37.608 21.683 ;
     RECT  4.32 18.757 4.344 21.731 ;
     RECT  22.992 20.915 23.016 22.165 ;
     RECT  40.2 21.203 41.064 22.165 ;
     RECT  27.312 20.387 27.336 22.259 ;
     RECT  22.416 22.165 23.016 22.309 ;
     RECT  24 21.395 24.312 22.309 ;
     RECT  29.4 20.387 29.712 22.309 ;
     RECT  13.2 19.427 13.608 22.645 ;
     RECT  29.4 22.309 30.504 22.691 ;
     RECT  18.288 19.043 18.912 22.741 ;
     RECT  36.864 21.683 37.608 22.741 ;
     RECT  32.976 19.765 33 22.835 ;
     RECT  40.2 22.165 41.448 22.835 ;
     RECT  7.8 20.579 8.112 23.317 ;
     RECT  34.8 21.155 35.208 23.317 ;
     RECT  10.8 22.165 10.824 23.411 ;
     RECT  13.2 22.645 14.28 23.411 ;
     RECT  40.2 22.835 41.064 23.507 ;
     RECT  16.32 22.165 16.344 23.555 ;
     RECT  36.816 22.741 37.608 23.557 ;
     RECT  6.528 22.741 6.552 23.653 ;
     RECT  7.8 23.317 8.52 23.653 ;
     RECT  13.2 23.411 13.608 23.893 ;
     RECT  36.432 23.557 37.608 23.987 ;
     RECT  22.416 22.309 24.312 24.085 ;
     RECT  25.632 21.395 25.656 24.085 ;
     RECT  22.416 24.085 25.656 24.131 ;
     RECT  3.888 23.653 3.912 24.563 ;
     RECT  6.528 23.653 8.52 24.659 ;
     RECT  15.456 24.085 15.48 24.899 ;
     RECT  27.024 23.557 27.048 24.947 ;
     RECT  29.4 22.691 29.712 25.045 ;
     RECT  30.72 22.789 30.744 25.045 ;
     RECT  36.432 23.987 36.888 25.189 ;
     RECT  7.2 24.659 8.52 25.235 ;
     RECT  36.432 25.189 37.704 25.379 ;
     RECT  29.4 25.045 30.744 25.523 ;
     RECT  20.592 21.443 20.616 25.715 ;
     RECT  36.432 25.379 36.888 25.715 ;
     RECT  40.2 23.507 40.512 25.813 ;
     RECT  17.424 22.741 18.912 25.861 ;
     RECT  38.448 25.621 38.472 26.053 ;
     RECT  33.696 23.317 35.208 26.243 ;
     RECT  38.448 26.053 38.76 26.243 ;
     RECT  13.104 23.893 13.608 26.291 ;
     RECT  44.448 25.861 44.472 26.581 ;
     RECT  26.832 25.717 26.856 26.629 ;
     RECT  26.832 26.629 27.336 26.675 ;
     RECT  17.04 25.861 18.912 26.819 ;
     RECT  39.936 25.813 40.512 26.867 ;
     RECT  34.56 26.243 35.208 27.157 ;
     RECT  22.416 24.131 23.016 27.299 ;
     RECT  43.824 26.581 44.472 27.301 ;
     RECT  36.816 25.715 36.888 27.541 ;
     RECT  36.816 27.541 36.936 27.829 ;
     RECT  7.2 25.235 8.112 27.875 ;
     RECT  38.736 26.243 38.76 27.875 ;
     RECT  36.288 27.829 36.936 27.877 ;
     RECT  17.424 26.819 18.912 28.405 ;
     RECT  36.288 27.877 37.032 28.405 ;
     RECT  17.136 28.405 18.912 28.451 ;
     RECT  13.2 26.291 13.608 28.453 ;
     RECT  13.104 28.453 13.608 28.499 ;
     RECT  24 24.131 25.656 28.547 ;
     RECT  27.312 26.675 27.336 28.547 ;
     RECT  42.96 27.301 44.472 28.547 ;
     RECT  5.712 27.877 5.736 28.739 ;
     RECT  40.2 26.867 40.512 28.741 ;
     RECT  11.424 27.301 11.448 28.931 ;
     RECT  25.584 28.547 25.656 29.029 ;
     RECT  29.4 25.523 30.456 29.075 ;
     RECT  34.56 27.157 35.304 29.171 ;
     RECT  17.136 28.451 17.16 29.555 ;
     RECT  9.456 28.837 9.48 29.797 ;
     RECT  9.264 29.797 9.48 29.843 ;
     RECT  40.08 28.741 40.512 30.035 ;
     RECT  18.288 28.451 18.912 30.181 ;
     RECT  11.088 29.653 11.112 30.227 ;
     RECT  13.104 28.499 13.512 30.323 ;
     RECT  29.4 29.075 30.264 30.325 ;
     RECT  7.392 27.875 8.112 30.709 ;
     RECT  6.528 30.709 8.112 31.043 ;
     RECT  25.584 29.029 26.136 31.187 ;
     RECT  36.288 28.405 37.992 31.187 ;
     RECT  15.84 30.181 16.728 31.331 ;
     RECT  42.96 28.547 43.848 31.379 ;
     RECT  17.808 30.181 18.912 31.475 ;
     RECT  34.56 29.171 35.256 31.475 ;
     RECT  22.992 27.299 23.016 31.669 ;
     RECT  18.6 31.475 18.912 31.813 ;
     RECT  13.2 30.323 13.512 31.861 ;
     RECT  29.088 30.325 30.264 31.861 ;
     RECT  31.44 31.285 31.464 31.861 ;
     RECT  34.8 31.475 35.256 31.861 ;
     RECT  20.88 31.525 20.904 31.955 ;
     RECT  29.088 31.861 31.464 32.195 ;
     RECT  9.264 29.843 9.288 32.243 ;
     RECT  29.088 32.195 31.32 32.245 ;
     RECT  6.96 31.043 8.112 32.293 ;
     RECT  22.128 31.669 23.016 32.435 ;
     RECT  25.584 31.187 25.608 32.437 ;
     RECT  36.432 31.187 37.992 32.437 ;
     RECT  42.96 31.379 42.984 32.531 ;
     RECT  6.96 32.293 8.52 32.579 ;
     RECT  34.8 31.861 35.352 32.771 ;
     RECT  15.84 31.331 16.344 32.963 ;
     RECT  18.6 31.813 19.8 32.963 ;
     RECT  10.8 31.861 10.824 33.107 ;
     RECT  13.2 31.861 13.656 33.107 ;
     RECT  28.368 32.245 31.32 33.107 ;
     RECT  25.584 32.437 25.752 33.155 ;
     RECT  31.008 33.107 31.32 33.251 ;
     RECT  18.6 32.963 18.912 33.301 ;
     RECT  28.368 33.107 29.712 33.541 ;
     RECT  3.936 32.485 3.96 33.587 ;
     RECT  34.8 32.771 35.112 33.589 ;
     RECT  40.2 30.035 40.512 33.589 ;
     RECT  22.992 32.435 23.016 33.877 ;
     RECT  36.432 32.437 38.616 34.019 ;
     RECT  7.8 32.579 8.52 34.067 ;
     RECT  40.2 33.589 41.256 34.067 ;
     RECT  22.8 33.877 23.016 34.115 ;
     RECT  36.432 34.019 37.32 34.115 ;
     RECT  40.2 34.067 40.512 34.165 ;
     RECT  21.648 33.013 21.672 34.211 ;
     RECT  32.64 33.109 32.664 34.213 ;
     RECT  32.496 34.213 32.664 34.259 ;
     RECT  2.4 18.995 2.712 34.453 ;
     RECT  2.304 34.453 2.712 34.643 ;
     RECT  38.592 34.019 38.616 34.691 ;
     RECT  15.84 32.963 15.864 34.693 ;
     RECT  18.288 33.301 18.912 34.835 ;
     RECT  25.728 33.155 25.752 34.931 ;
     RECT  31.2 33.251 31.32 34.981 ;
     RECT  32.496 34.259 32.52 34.981 ;
     RECT  10.272 33.541 10.296 35.363 ;
     RECT  31.2 34.981 32.52 35.747 ;
     RECT  22.992 34.115 23.016 35.826 ;
     RECT  4.944 30.229 4.968 35.845 ;
     RECT  18.6 34.835 18.912 35.845 ;
     RECT  36.432 34.115 36.504 35.845 ;
     RECT  20.784 34.933 20.808 35.939 ;
     RECT  36.384 35.845 36.504 35.939 ;
     RECT  34.464 33.589 35.112 35.987 ;
     RECT  15.84 34.693 16.776 36.181 ;
     RECT  15.84 36.181 17.112 36.227 ;
     RECT  27.984 33.541 29.712 36.227 ;
     RECT  14.832 34.741 14.856 36.277 ;
     RECT  15.84 36.227 15.864 36.277 ;
     RECT  4.944 35.845 5.592 36.515 ;
     RECT  17.088 36.227 17.112 36.515 ;
     RECT  41.904 35.269 41.928 36.515 ;
     RECT  22.704 35.826 23.016 36.517 ;
     RECT  7.8 34.067 8.232 36.563 ;
     RECT  14.832 36.277 15.864 36.563 ;
     RECT  28.368 36.227 29.712 36.707 ;
     RECT  31.2 35.747 31.896 36.851 ;
     RECT  34.8 35.987 35.112 36.901 ;
     RECT  36.384 35.939 36.456 37.093 ;
     RECT  18.48 35.845 18.912 37.525 ;
     RECT  39.744 34.165 40.512 37.573 ;
     RECT  34.8 36.901 35.208 37.621 ;
     RECT  36.384 37.093 37.08 37.621 ;
     RECT  15.36 36.563 15.864 37.667 ;
     RECT  34.8 37.621 37.08 37.667 ;
     RECT  38.832 37.573 40.512 37.669 ;
     RECT  15.36 37.667 15.384 37.859 ;
     RECT  22.608 36.517 23.016 37.859 ;
     RECT  4.944 36.515 4.968 38.053 ;
     RECT  31.2 36.851 31.848 38.101 ;
     RECT  30.864 38.101 31.848 38.149 ;
     RECT  30.768 38.149 31.848 38.293 ;
     RECT  33.024 36.421 33.048 38.293 ;
     RECT  30.768 38.293 33.048 38.435 ;
     RECT  17.952 37.525 18.912 38.581 ;
     RECT  33.024 38.435 33.048 38.581 ;
     RECT  38.784 37.669 40.512 38.677 ;
     RECT  22.992 37.859 23.016 38.773 ;
     RECT  24 28.547 24.312 38.773 ;
     RECT  30.768 38.435 31.848 38.819 ;
     RECT  34.8 37.667 35.496 38.819 ;
     RECT  37.056 37.667 37.08 38.915 ;
     RECT  2.4 34.643 2.712 39.205 ;
     RECT  4.704 38.053 4.968 39.395 ;
     RECT  4.704 39.395 4.728 39.443 ;
     RECT  12.144 37.573 12.168 39.589 ;
     RECT  12 39.589 12.168 39.635 ;
     RECT  7.8 36.563 8.112 39.829 ;
     RECT  21.744 38.581 21.768 39.923 ;
     RECT  28.464 36.707 29.712 39.923 ;
     RECT  30.768 38.819 31.272 40.019 ;
     RECT  38.784 38.677 41.064 40.067 ;
     RECT  17.952 38.581 19.416 40.307 ;
     RECT  22.992 38.773 24.312 40.307 ;
     RECT  26.256 36.997 26.28 40.309 ;
     RECT  25.68 40.309 26.28 40.355 ;
     RECT  2.4 39.205 2.808 40.499 ;
     RECT  7.8 39.829 8.232 40.597 ;
     RECT  38.784 40.067 40.512 40.837 ;
     RECT  38.592 40.837 40.512 41.027 ;
     RECT  15.792 39.877 15.816 41.075 ;
     RECT  42.192 41.029 42.216 41.173 ;
     RECT  34.8 38.819 35.208 41.411 ;
     RECT  33.024 38.581 33.576 41.557 ;
     RECT  12 39.635 12.024 41.651 ;
     RECT  38.832 41.027 40.512 41.651 ;
     RECT  41.568 41.173 42.216 41.651 ;
     RECT  28.512 39.923 29.712 41.893 ;
     RECT  30.864 40.019 30.888 41.893 ;
     RECT  32.112 41.557 33.576 41.939 ;
     RECT  22.992 40.307 23.016 42.085 ;
     RECT  24 40.307 24.312 42.085 ;
     RECT  7.8 40.597 8.28 42.133 ;
     RECT  26.928 40.405 26.952 42.133 ;
     RECT  26.928 42.133 27.288 42.227 ;
     RECT  44.496 37.429 44.52 42.227 ;
     RECT  13.2 33.107 13.512 42.709 ;
     RECT  32.976 41.939 33.576 42.755 ;
     RECT  22.992 42.085 24.312 42.757 ;
     RECT  27.264 42.227 27.288 42.757 ;
     RECT  14.736 42.133 14.76 42.803 ;
     RECT  22.992 42.757 24.408 42.803 ;
     RECT  28.512 41.893 30.888 42.803 ;
     RECT  33.504 42.755 33.576 42.805 ;
     RECT  34.8 41.411 35.112 42.805 ;
     RECT  24 42.803 24.408 42.899 ;
     RECT  33.504 42.805 35.112 42.997 ;
     RECT  3.792 42.085 3.816 43.283 ;
     RECT  41.568 41.651 41.592 43.283 ;
     RECT  22.992 42.803 23.016 43.333 ;
     RECT  10.8 42.709 10.824 43.379 ;
     RECT  25.68 40.355 25.704 43.523 ;
     RECT  37.056 42.421 37.08 43.571 ;
     RECT  29.28 42.803 30.888 43.667 ;
     RECT  39.216 41.651 40.512 43.765 ;
     RECT  22.08 43.333 23.016 43.813 ;
     RECT  24 42.899 24.312 43.813 ;
     RECT  39.216 43.765 41.16 43.907 ;
     RECT  43.104 42.997 43.128 43.955 ;
     RECT  13.2 42.709 13.608 44.053 ;
     RECT  33.504 42.997 35.352 44.149 ;
     RECT  27.264 42.757 27.336 44.341 ;
     RECT  7.8 42.133 8.712 44.627 ;
     RECT  15.84 43.381 15.864 44.627 ;
     RECT  19.92 42.709 19.944 44.627 ;
     RECT  22.08 43.813 24.312 44.677 ;
     RECT  22.08 44.677 25.224 44.915 ;
     RECT  29.28 43.667 30.504 44.965 ;
     RECT  37.584 43.957 37.608 44.965 ;
     RECT  37.296 44.965 37.608 45.011 ;
     RECT  33.504 44.149 35.832 45.059 ;
     RECT  10.752 44.197 10.776 45.155 ;
     RECT  27.264 44.341 27.432 45.253 ;
     RECT  0.144 44.149 0.168 45.491 ;
     RECT  17.328 43.093 17.352 45.541 ;
     RECT  44.112 44.917 44.136 45.541 ;
     RECT  39.216 43.907 40.68 45.635 ;
     RECT  5.088 43.861 5.112 45.683 ;
     RECT  22.992 44.915 25.224 45.731 ;
     RECT  7.8 44.627 8.28 45.781 ;
     RECT  7.44 45.781 8.28 46.117 ;
     RECT  27.168 45.253 27.432 46.117 ;
     RECT  27.168 46.117 27.96 46.163 ;
     RECT  43.68 45.541 44.136 46.211 ;
     RECT  27.264 46.163 27.96 46.259 ;
     RECT  33.6 45.059 35.832 46.307 ;
     RECT  24 45.731 25.224 46.547 ;
     RECT  27.408 46.259 27.96 46.547 ;
     RECT  29.28 44.965 30.84 46.645 ;
     RECT  39.168 45.781 39.192 46.645 ;
     RECT  7.44 46.117 9.144 46.787 ;
     RECT  20.256 45.013 20.28 46.787 ;
     RECT  27.936 46.547 27.96 46.787 ;
     RECT  29.28 46.645 32.52 46.787 ;
     RECT  34.8 46.307 35.832 46.787 ;
     RECT  40.2 45.635 40.68 46.835 ;
     RECT  16.896 45.541 17.352 47.173 ;
     RECT  18.6 40.307 18.912 47.173 ;
     RECT  16.896 47.173 18.912 47.219 ;
     RECT  29.28 46.787 32.232 47.315 ;
     RECT  11.664 46.117 11.688 47.363 ;
     RECT  13.2 44.053 14.28 47.459 ;
     RECT  44.112 46.211 44.136 47.459 ;
     RECT  7.44 46.787 8.28 47.461 ;
     RECT  38.88 46.645 39.192 47.699 ;
     RECT  32.208 47.315 32.232 47.747 ;
     RECT  29.28 47.315 30.84 47.843 ;
     RECT  17.328 47.219 18.912 47.845 ;
     RECT  21.744 45.589 21.768 47.891 ;
     RECT  38.88 47.699 38.904 47.891 ;
     RECT  40.2 46.835 40.512 47.893 ;
     RECT  40.2 47.893 40.776 47.989 ;
     RECT  17.328 47.845 19.368 48.373 ;
     RECT  6.768 47.461 8.28 48.419 ;
     RECT  24 46.547 24.312 48.421 ;
     RECT  34.8 46.787 35.208 48.421 ;
     RECT  34.704 48.421 35.208 48.467 ;
     RECT  42.24 46.645 42.264 48.517 ;
     RECT  17.088 48.373 19.368 48.611 ;
     RECT  42.24 48.517 42.36 48.661 ;
     RECT  26.208 46.501 26.232 48.709 ;
     RECT  29.4 47.843 30.84 48.805 ;
     RECT  40.2 47.989 41.112 48.853 ;
     RECT  42.24 48.661 42.408 48.853 ;
     RECT  40.2 48.853 42.408 48.949 ;
     RECT  7.296 48.419 8.28 49.091 ;
     RECT  24 48.421 24.984 49.475 ;
     RECT  34.704 48.467 35.112 49.475 ;
     RECT  13.2 47.459 13.512 49.477 ;
     RECT  17.088 48.611 18.912 49.525 ;
     RECT  16.368 49.525 18.912 49.571 ;
     RECT  26.064 48.709 26.232 49.571 ;
     RECT  10.272 47.461 10.296 49.619 ;
     RECT  40.2 48.949 42.84 49.621 ;
     RECT  40.08 49.621 42.84 49.955 ;
     RECT  5.664 49.045 5.688 50.003 ;
     RECT  37.296 45.011 37.32 50.005 ;
     RECT  37.296 50.005 37.512 50.051 ;
     RECT  16.368 49.571 17.16 50.147 ;
     RECT  11.52 50.533 11.544 50.675 ;
     RECT  27.312 49.717 27.336 50.819 ;
     RECT  29.4 48.805 31.32 50.819 ;
     RECT  33.6 46.307 33.624 50.821 ;
     RECT  15.504 50.677 15.528 50.965 ;
     RECT  40.2 49.955 42.84 51.107 ;
     RECT  7.44 49.091 8.28 51.443 ;
     RECT  44.496 48.949 44.52 51.493 ;
     RECT  14.544 50.965 15.528 51.541 ;
     RECT  17.136 50.147 17.16 51.541 ;
     RECT  14.544 51.541 17.16 51.587 ;
     RECT  12.528 49.477 13.512 51.637 ;
     RECT  33.072 50.821 33.624 51.637 ;
     RECT  34.8 49.475 35.112 51.637 ;
     RECT  14.544 51.587 14.568 51.683 ;
     RECT  16.464 51.587 17.16 51.923 ;
     RECT  40.2 51.107 40.776 51.923 ;
     RECT  41.856 51.107 42.84 51.923 ;
     RECT  26.208 49.571 26.232 52.019 ;
     RECT  21.744 51.109 21.768 52.211 ;
     RECT  4.896 52.357 4.92 52.405 ;
     RECT  36.432 51.109 36.456 52.405 ;
     RECT  36.144 52.405 36.456 52.451 ;
     RECT  42.144 51.923 42.84 52.499 ;
     RECT  44.064 51.493 44.52 52.547 ;
     RECT  4.416 52.405 4.92 52.595 ;
     RECT  9.552 51.493 9.576 52.595 ;
     RECT  32.784 51.637 33.624 52.643 ;
     RECT  18.6 49.571 18.912 52.693 ;
     RECT  33.072 52.643 33.624 52.739 ;
     RECT  22.992 45.731 23.016 52.933 ;
     RECT  29.4 50.819 30.504 52.981 ;
     RECT  37.488 50.051 37.512 52.981 ;
     RECT  37.488 52.981 37.944 53.027 ;
     RECT  22.512 52.933 23.016 53.075 ;
     RECT  33.264 52.739 33.624 53.077 ;
     RECT  34.704 51.637 35.112 53.077 ;
     RECT  33.264 53.077 35.112 53.219 ;
     RECT  18.6 52.693 19.032 53.509 ;
     RECT  34.8 53.219 35.112 53.557 ;
     RECT  36.144 52.451 36.168 53.557 ;
     RECT  28.512 52.981 30.504 53.603 ;
     RECT  34.8 53.557 36.168 53.699 ;
     RECT  12.384 51.637 13.512 53.941 ;
     RECT  10.8 52.549 10.824 54.035 ;
     RECT  40.2 51.923 40.512 54.085 ;
     RECT  42.144 52.499 42.168 54.085 ;
     RECT  16.464 51.923 16.536 54.131 ;
     RECT  36.144 53.699 36.168 54.179 ;
     RECT  28.752 53.603 30.504 54.661 ;
     RECT  24 49.475 24.312 54.997 ;
     RECT  44.064 52.547 44.088 55.187 ;
     RECT  4.512 52.595 4.92 55.237 ;
     RECT  12.24 53.941 13.512 55.237 ;
     RECT  37.92 53.027 37.944 55.237 ;
     RECT  16.512 54.131 16.536 55.475 ;
     RECT  33.264 53.219 33.624 55.715 ;
     RECT  7.68 51.443 8.28 55.763 ;
     RECT  12.24 55.237 14.232 55.813 ;
     RECT  37.92 55.237 38.808 55.861 ;
     RECT  37.584 55.861 38.808 55.907 ;
     RECT  18.6 53.509 19.368 56.195 ;
     RECT  22.992 53.075 23.016 56.293 ;
     RECT  24 54.997 25.128 56.293 ;
     RECT  22.992 56.293 25.128 56.435 ;
     RECT  38.784 55.907 38.808 56.435 ;
     RECT  28.752 54.661 31.416 56.483 ;
     RECT  24 56.435 25.128 56.723 ;
     RECT  18.6 56.195 19.176 56.821 ;
     RECT  34.8 53.699 35.112 56.965 ;
     RECT  17.952 56.821 19.176 57.011 ;
     RECT  4.512 55.237 5.688 57.059 ;
     RECT  12.096 55.813 14.232 57.059 ;
     RECT  28.752 56.483 30.984 57.059 ;
     RECT  13.056 57.059 14.232 57.107 ;
     RECT  18.6 57.011 19.176 57.155 ;
     RECT  22.992 56.435 23.016 57.395 ;
     RECT  33.264 55.715 33.336 57.445 ;
     RECT  29.4 57.059 30.984 57.491 ;
     RECT  21.072 57.349 21.096 57.539 ;
     RECT  7.8 55.763 8.28 58.117 ;
     RECT  9.312 56.869 9.336 58.117 ;
     RECT  37.584 55.907 37.608 58.117 ;
     RECT  18.6 57.155 19.032 58.163 ;
     RECT  24 56.723 24.792 58.163 ;
     RECT  37.296 58.117 37.608 58.163 ;
     RECT  39.168 57.541 39.192 58.163 ;
     RECT  13.056 57.107 13.512 58.211 ;
     RECT  2.4 40.499 2.712 58.501 ;
     RECT  13.2 58.211 13.512 58.501 ;
     RECT  7.8 58.117 9.336 58.597 ;
     RECT  2.112 58.501 2.712 58.643 ;
     RECT  34.656 56.965 35.112 58.645 ;
     RECT  15.456 56.389 15.48 58.691 ;
     RECT  32.448 57.445 33.336 58.693 ;
     RECT  4.896 57.059 5.688 58.739 ;
     RECT  7.8 58.597 9.384 58.739 ;
     RECT  32.256 58.693 33.336 58.739 ;
     RECT  10.608 57.541 11.208 58.787 ;
     RECT  33.264 58.739 33.336 58.787 ;
     RECT  7.8 58.739 8.376 59.123 ;
     RECT  34.656 58.645 35.88 59.171 ;
     RECT  34.8 59.171 35.88 59.173 ;
     RECT  37.296 58.163 37.32 59.173 ;
     RECT  34.8 59.173 37.32 59.267 ;
     RECT  21.888 58.645 21.912 59.747 ;
     RECT  34.8 59.267 36.6 59.747 ;
     RECT  29.4 57.491 30.408 59.797 ;
     RECT  4.896 58.739 5.112 60.275 ;
     RECT  17.184 59.941 17.208 60.275 ;
     RECT  26.352 58.021 26.376 60.467 ;
     RECT  32.256 58.739 32.28 60.517 ;
     RECT  34.8 59.747 35.88 60.563 ;
     RECT  4.896 60.275 4.92 60.661 ;
     RECT  4.848 60.661 4.92 60.851 ;
     RECT  13.2 58.501 14.28 60.947 ;
     RECT  31.92 60.517 32.28 60.995 ;
     RECT  9.36 58.739 9.384 61.043 ;
     RECT  29.4 59.797 30.84 61.381 ;
     RECT  7.8 59.123 8.28 61.429 ;
     RECT  13.2 60.947 13.512 61.477 ;
     RECT  2.4 58.643 2.712 61.525 ;
     RECT  34.8 60.563 35.496 61.619 ;
     RECT  33.312 58.787 33.336 61.667 ;
     RECT  24 58.163 24.312 61.765 ;
     RECT  38.832 60.757 38.856 61.907 ;
     RECT  2.4 61.525 2.904 62.195 ;
     RECT  11.184 58.787 11.208 62.195 ;
     RECT  29.04 61.381 31.272 62.339 ;
     RECT  7.392 61.429 8.28 62.389 ;
     RECT  29.04 62.339 30.936 62.485 ;
     RECT  12.672 61.477 13.512 62.531 ;
     RECT  34.8 61.619 35.112 62.581 ;
     RECT  16.032 60.949 16.056 62.677 ;
     RECT  34.8 62.581 36.024 62.677 ;
     RECT  4.848 60.851 4.872 62.771 ;
     RECT  24 61.765 24.744 62.771 ;
     RECT  32.256 60.995 32.28 62.771 ;
     RECT  26.736 60.853 26.76 63.011 ;
     RECT  14.592 61.813 14.616 63.013 ;
     RECT  16.032 62.677 16.776 63.013 ;
     RECT  34.32 62.677 36.024 63.013 ;
     RECT  14.592 63.013 16.776 63.059 ;
     RECT  34.32 63.013 36.84 63.109 ;
     RECT  9.552 62.581 9.576 63.205 ;
     RECT  34.32 63.109 36.984 63.205 ;
     RECT  9.552 63.205 9.72 63.251 ;
     RECT  14.592 63.059 15.576 63.299 ;
     RECT  28.8 62.485 30.936 63.541 ;
     RECT  28.8 63.541 31.176 63.587 ;
     RECT  22.752 62.101 22.776 63.779 ;
     RECT  18.6 58.163 18.912 63.781 ;
     RECT  33.792 63.205 36.984 63.781 ;
     RECT  40.2 54.085 42.168 63.781 ;
     RECT  33.744 63.781 36.984 63.827 ;
     RECT  34.8 63.827 36.984 63.923 ;
     RECT  2.4 62.195 2.712 64.357 ;
     RECT  12.72 62.531 13.512 64.357 ;
     RECT  30.816 63.587 31.176 64.357 ;
     RECT  30.816 64.357 31.32 64.451 ;
     RECT  33.744 63.827 33.816 64.595 ;
     RECT  39.36 63.781 42.168 64.595 ;
     RECT  18.6 63.781 19.512 64.885 ;
     RECT  17.856 64.885 19.512 64.931 ;
     RECT  39.36 64.595 41.88 64.979 ;
     RECT  31.296 64.451 31.32 65.173 ;
     RECT  0.144 65.125 0.168 65.315 ;
     RECT  39.36 64.979 41.256 65.363 ;
     RECT  28.8 63.587 29.712 65.557 ;
     RECT  9.696 63.251 9.72 65.603 ;
     RECT  16.752 63.059 16.776 65.603 ;
     RECT  12 64.357 13.512 65.651 ;
     RECT  2.4 64.357 3.432 65.845 ;
     RECT  15.552 63.299 15.576 66.085 ;
     RECT  17.856 64.931 18.912 66.085 ;
     RECT  12.528 65.651 13.512 66.179 ;
     RECT  2.4 65.845 3.48 66.755 ;
     RECT  25.68 66.133 25.704 66.755 ;
     RECT  36.816 63.923 36.984 66.949 ;
     RECT  17.712 66.085 18.912 67.283 ;
     RECT  21.648 65.653 21.672 67.283 ;
     RECT  24 62.771 24.312 67.429 ;
     RECT  40.2 65.363 41.256 67.573 ;
     RECT  24 67.429 24.552 67.765 ;
     RECT  15.36 66.085 15.576 68.245 ;
     RECT  18.6 67.283 18.912 68.245 ;
     RECT  28.464 65.557 29.712 68.341 ;
     RECT  31.296 65.173 31.704 68.341 ;
     RECT  34.8 63.923 35.112 68.341 ;
     RECT  14.832 68.245 15.576 68.387 ;
     RECT  16.704 67.765 16.728 68.435 ;
     RECT  9.84 66.901 9.864 68.819 ;
     RECT  23.088 67.765 24.552 68.963 ;
     RECT  12.72 66.179 13.512 68.965 ;
     RECT  23.088 68.963 24.312 69.011 ;
     RECT  12.72 68.965 13.656 69.251 ;
     RECT  31.296 68.341 31.944 69.251 ;
     RECT  0.144 69.301 0.168 69.491 ;
     RECT  18.6 68.245 19.416 69.829 ;
     RECT  26.928 68.917 26.952 70.019 ;
     RECT  34.8 68.341 35.832 70.019 ;
     RECT  28.464 68.341 29.832 70.213 ;
     RECT  27.936 70.213 29.832 70.259 ;
     RECT  31.92 69.251 31.944 70.259 ;
     RECT  36.816 66.949 37.896 70.259 ;
     RECT  12.72 69.251 13.512 70.307 ;
     RECT  33.792 64.595 33.816 70.307 ;
     RECT  6.864 62.389 8.28 70.355 ;
     RECT  24 69.011 24.312 70.357 ;
     RECT  39.552 67.573 41.256 70.405 ;
     RECT  7.8 70.355 8.28 70.645 ;
     RECT  36.816 70.259 37.752 70.645 ;
     RECT  29.4 70.259 29.832 70.739 ;
     RECT  18.6 69.829 19.512 70.835 ;
     RECT  39.312 70.405 41.256 71.027 ;
     RECT  39.552 71.027 41.256 71.221 ;
     RECT  15.408 68.387 15.432 71.269 ;
     RECT  7.8 70.645 8.52 71.315 ;
     RECT  12 70.405 12.024 71.315 ;
     RECT  34.8 70.019 35.112 71.461 ;
     RECT  24 70.357 25.224 71.749 ;
     RECT  18.6 70.835 18.912 71.797 ;
     RECT  30.864 69.973 30.888 72.035 ;
     RECT  15.408 71.269 16.344 72.131 ;
     RECT  5.28 70.309 5.304 72.373 ;
     RECT  5.28 72.373 5.784 72.419 ;
     RECT  20.4 71.749 20.424 72.419 ;
     RECT  22.416 71.317 22.44 72.419 ;
     RECT  39.552 71.221 41.832 72.419 ;
     RECT  41.808 72.419 41.832 72.467 ;
     RECT  29.4 70.739 29.712 72.565 ;
     RECT  27.936 70.259 27.96 72.661 ;
     RECT  27.936 72.661 28.2 72.707 ;
     RECT  36.432 70.645 37.752 72.707 ;
     RECT  28.176 72.707 28.2 72.709 ;
     RECT  29.4 72.565 30.264 72.709 ;
     RECT  34.8 71.461 35.4 72.899 ;
     RECT  23.808 71.749 25.224 73.091 ;
     RECT  7.8 71.315 8.28 73.237 ;
     RECT  17.616 71.797 18.912 73.523 ;
     RECT  22.176 72.757 22.2 73.571 ;
     RECT  43.776 73.525 43.8 73.957 ;
     RECT  43.296 73.957 43.8 74.005 ;
     RECT  39.552 72.419 40.512 74.053 ;
     RECT  43.296 74.005 43.896 74.053 ;
     RECT  39.552 74.053 41.016 74.147 ;
     RECT  7.8 73.237 8.376 74.195 ;
     RECT  28.176 72.709 30.264 74.291 ;
     RECT  4.704 74.053 4.728 74.339 ;
     RECT  24 73.091 25.224 74.339 ;
     RECT  36.432 72.707 36.984 74.435 ;
     RECT  36.432 74.435 36.84 74.581 ;
     RECT  28.176 74.291 28.2 74.629 ;
     RECT  10.368 74.869 10.392 75.011 ;
     RECT  13.2 70.307 13.512 75.205 ;
     RECT  43.296 74.053 44.712 75.205 ;
     RECT  40.2 74.147 41.016 75.251 ;
     RECT  36.24 74.581 36.84 75.299 ;
     RECT  32.16 71.509 32.184 75.397 ;
     RECT  31.92 75.397 32.184 75.443 ;
     RECT  29.4 74.291 30.264 75.683 ;
     RECT  36.24 75.299 36.456 75.827 ;
     RECT  17.232 74.053 17.256 75.923 ;
     RECT  27.36 74.629 28.2 75.923 ;
     RECT  5.76 72.419 5.784 76.019 ;
     RECT  22.224 75.157 22.248 76.019 ;
     RECT  2.4 66.755 2.712 76.069 ;
     RECT  7.8 74.195 8.28 76.165 ;
     RECT  40.2 75.251 40.512 76.357 ;
     RECT  13.2 75.205 13.848 76.451 ;
     RECT  24 74.339 25.128 76.595 ;
     RECT  7.8 76.165 8.904 76.691 ;
     RECT  2.4 76.069 3.384 76.787 ;
     RECT  36.432 75.827 36.456 76.787 ;
     RECT  15.408 72.131 15.432 76.979 ;
     RECT  28.176 75.923 28.2 76.979 ;
     RECT  34.8 72.899 35.112 77.029 ;
     RECT  13.2 76.451 13.512 77.317 ;
     RECT  31.92 75.443 31.944 77.363 ;
     RECT  24 76.595 24.552 77.555 ;
     RECT  34.8 77.029 35.352 77.555 ;
     RECT  7.8 76.691 8.376 77.893 ;
     RECT  13.104 77.317 13.512 77.939 ;
     RECT  40.08 76.357 40.512 77.987 ;
     RECT  7.8 77.893 9.24 78.083 ;
     RECT  26.256 77.029 26.28 78.131 ;
     RECT  42.48 75.205 44.712 78.131 ;
     RECT  33.6 77.173 33.624 78.277 ;
     RECT  33.6 78.277 33.672 78.467 ;
     RECT  15.792 76.981 15.816 78.611 ;
     RECT  33.456 78.469 33.48 78.611 ;
     RECT  42.48 78.131 44.136 78.707 ;
     RECT  31.872 77.941 31.896 79.187 ;
     RECT  4.128 78.613 4.152 79.235 ;
     RECT  43.488 78.707 44.136 79.283 ;
     RECT  44.112 79.283 44.136 79.331 ;
     RECT  42.48 78.707 42.504 79.379 ;
     RECT  5.712 78.613 5.736 79.475 ;
     RECT  26.688 79.189 26.712 79.475 ;
     RECT  21.648 77.461 21.672 79.763 ;
     RECT  7.8 78.083 8.28 79.765 ;
     RECT  2.4 76.787 2.712 79.929 ;
     RECT  13.2 77.939 13.512 79.929 ;
     RECT  18.6 73.523 18.912 79.929 ;
     RECT  24 77.555 24.312 79.929 ;
     RECT  29.4 75.683 29.712 79.929 ;
     RECT  34.8 77.555 35.112 79.929 ;
     RECT  40.2 77.987 40.512 79.929 ;
     RECT  2.4 79.929 2.52 79.943 ;
     RECT  7.8 79.765 8.424 79.943 ;
     RECT  13.2 79.929 13.32 79.943 ;
     RECT  18.6 79.929 18.72 79.943 ;
     RECT  24 79.929 24.12 79.943 ;
     RECT  29.4 79.929 29.52 79.943 ;
     RECT  34.8 79.929 34.92 79.943 ;
     RECT  40.2 79.929 40.32 79.943 ;
     RECT  8.112 79.943 8.424 81.685 ;
     RECT  8.016 81.685 8.424 81.971 ;
     RECT  8.112 81.971 8.328 82.064 ;
     RECT  35.112 2.821 36.384 3.397 ;
     RECT  33.768 2.869 34.8 4.403 ;
     RECT  35.208 3.397 36.384 3.587 ;
     RECT  24.312 4.117 25.728 5.219 ;
     RECT  6.408 4.357 7.8 4.499 ;
     RECT  33.744 4.403 34.8 4.501 ;
     RECT  5.784 4.499 7.8 4.549 ;
     RECT  33.72 4.501 34.8 5.699 ;
     RECT  5.784 4.549 7.056 4.595 ;
     RECT  5.76 4.595 7.056 5.077 ;
     RECT  17.16 4.645 18.6 4.979 ;
     RECT  16.392 4.979 16.44 5.747 ;
     RECT  5.256 5.077 7.056 5.219 ;
     RECT  39.312 5.171 40.2 5.893 ;
     RECT  5.256 5.219 7.8 5.605 ;
     RECT  5.256 5.605 6.432 6.899 ;
     RECT  6.456 5.605 7.8 6.899 ;
     RECT  22.824 5.653 23.904 6.947 ;
     RECT  16.416 5.747 16.44 6.181 ;
     RECT  18.912 5.747 20.4 9.299 ;
     RECT  29.712 5.795 29.832 7.189 ;
     RECT  39.048 5.893 40.2 8.965 ;
     RECT  37.896 6.661 39.024 7.909 ;
     RECT  24.312 6.805 25.776 6.901 ;
     RECT  22.824 6.947 24 8.723 ;
     RECT  29.712 7.189 31.2 15.877 ;
     RECT  31.224 7.189 32.688 8.579 ;
     RECT  17.256 7.237 18.6 9.923 ;
     RECT  41.496 7.333 42.768 8.341 ;
     RECT  2.712 8.293 3.936 9.203 ;
     RECT  3.96 8.293 5.232 9.203 ;
     RECT  20.616 8.293 22.032 13.381 ;
     RECT  41.688 8.341 42.768 9.061 ;
     RECT  39.144 8.965 40.2 10.453 ;
     RECT  28.944 10.307 29.4 11.365 ;
     RECT  39.144 10.691 40.2 11.459 ;
     RECT  39.12 11.459 40.2 11.749 ;
     RECT  19.368 11.557 20.592 12.563 ;
     RECT  37.464 11.749 38.496 13.091 ;
     RECT  38.52 11.749 40.2 11.941 ;
     RECT  11.016 11.797 12.528 11.939 ;
     RECT  38.52 11.941 40.032 12.757 ;
     RECT  35.112 12.035 35.352 13.045 ;
     RECT  5.592 12.517 6.864 13.043 ;
     RECT  15.432 12.517 16.416 13.475 ;
     RECT  35.112 13.045 36.432 14.099 ;
     RECT  36.456 13.045 37.44 13.813 ;
     RECT  13.944 13.093 15.408 13.475 ;
     RECT  21.048 13.381 22.032 15.491 ;
     RECT  16.032 13.475 16.416 13.909 ;
     RECT  31.224 13.861 32.496 16.019 ;
     RECT  32.52 13.861 33.696 16.019 ;
     RECT  10.368 13.955 10.392 15.349 ;
     RECT  33.72 14.003 34.8 16.117 ;
     RECT  12.072 14.005 13.104 14.819 ;
     RECT  20.616 15.491 22.032 19.909 ;
     RECT  24.312 15.877 25.488 16.019 ;
     RECT  29.712 15.877 31.152 16.837 ;
     RECT  22.68 15.973 24 19.525 ;
     RECT  24.312 16.019 25.968 17.029 ;
     RECT  33.024 16.019 33.696 16.501 ;
     RECT  33.72 16.117 34.704 16.307 ;
     RECT  33.72 16.307 34.8 18.565 ;
     RECT  19.08 16.787 20.592 17.893 ;
     RECT  29.976 16.837 31.152 17.987 ;
     RECT  24.312 17.029 25.632 17.077 ;
     RECT  25.992 17.075 27.312 17.123 ;
     RECT  35.496 17.461 36.48 19.285 ;
     RECT  17.496 17.605 18.6 17.989 ;
     RECT  19.08 17.893 20.496 18.851 ;
     RECT  29.976 17.987 31.2 19.235 ;
     RECT  33.024 18.611 33.696 18.709 ;
     RECT  24.312 18.659 25.44 19.813 ;
     RECT  31.224 18.709 32.688 19.235 ;
     RECT  32.712 18.709 33.696 19.427 ;
     RECT  2.808 18.757 4.32 18.995 ;
     RECT  25.656 19.187 25.992 19.333 ;
     RECT  25.656 19.333 26.784 20.387 ;
     RECT  13.608 19.427 14.832 20.867 ;
     RECT  32.712 19.427 34.08 19.571 ;
     RECT  11.928 19.525 13.2 21.251 ;
     RECT  23.016 19.525 24 22.309 ;
     RECT  32.976 19.571 34.08 19.765 ;
     RECT  33 19.765 34.08 19.811 ;
     RECT  36.84 20.579 37.32 21.541 ;
     RECT  21.144 20.915 22.992 21.443 ;
     RECT  35.352 20.915 36.48 21.155 ;
     RECT  35.208 21.155 36.48 21.299 ;
     RECT  41.064 21.203 41.448 22.165 ;
     RECT  24.312 21.395 25.632 24.085 ;
     RECT  22.416 21.443 22.992 22.165 ;
     RECT  36.816 21.683 36.864 22.741 ;
     RECT  29.712 22.691 30.504 22.789 ;
     RECT  6.552 22.741 7.8 23.653 ;
     RECT  16.344 22.741 17.424 23.555 ;
     RECT  29.712 22.789 30.72 25.045 ;
     RECT  25.656 23.557 27.024 24.947 ;
     RECT  35.208 23.557 36.432 25.715 ;
     RECT  2.712 23.653 3.888 24.563 ;
     RECT  36.888 23.987 37.608 25.189 ;
     RECT  23.016 24.131 24 38.773 ;
     RECT  25.656 24.947 26.856 25.717 ;
     RECT  35.208 25.715 36.816 27.157 ;
     RECT  25.656 25.717 26.832 26.675 ;
     RECT  38.472 25.813 39.936 26.053 ;
     RECT  38.76 26.053 39.936 26.867 ;
     RECT  38.76 26.867 40.2 27.875 ;
     RECT  35.304 27.157 36.816 27.829 ;
     RECT  35.304 27.829 36.288 29.171 ;
     RECT  40.08 27.875 40.2 28.741 ;
     RECT  17.16 28.451 18.288 29.555 ;
     RECT  24.312 28.547 25.584 33.155 ;
     RECT  8.112 28.837 9.456 29.797 ;
     RECT  35.256 29.171 36.288 31.187 ;
     RECT  17.136 29.555 18.288 30.181 ;
     RECT  8.112 29.797 9.264 32.243 ;
     RECT  16.728 30.181 17.808 31.331 ;
     RECT  25.608 31.187 25.752 32.437 ;
     RECT  35.256 31.187 36.432 31.861 ;
     RECT  30.264 31.285 31.44 31.861 ;
     RECT  16.344 31.331 17.808 31.475 ;
     RECT  20.904 31.669 22.128 31.955 ;
     RECT  19.8 31.813 20.88 31.955 ;
     RECT  9.288 31.861 10.8 32.243 ;
     RECT  35.352 31.861 36.432 32.771 ;
     RECT  21.648 31.955 22.128 32.435 ;
     RECT  31.32 32.195 31.464 33.109 ;
     RECT  8.112 32.243 8.52 32.293 ;
     RECT  10.272 32.243 10.8 33.107 ;
     RECT  21.648 32.435 22.992 33.013 ;
     RECT  2.712 32.485 3.936 33.587 ;
     RECT  3.96 32.485 4.944 33.587 ;
     RECT  35.112 32.771 36.432 35.845 ;
     RECT  21.672 33.013 22.992 33.877 ;
     RECT  10.272 33.107 10.296 33.541 ;
     RECT  29.712 33.107 31.008 33.251 ;
     RECT  31.32 33.109 32.64 34.213 ;
     RECT  24.312 33.155 25.728 34.931 ;
     RECT  29.712 33.251 31.2 38.101 ;
     RECT  21.672 33.877 22.8 34.115 ;
     RECT  37.32 34.019 38.592 34.115 ;
     RECT  40.512 34.067 41.256 35.269 ;
     RECT  21.672 34.115 22.992 34.211 ;
     RECT  38.616 34.165 39.744 34.691 ;
     RECT  31.32 34.213 32.496 34.981 ;
     RECT  16.776 34.693 18.288 34.835 ;
     RECT  13.512 34.741 14.832 36.563 ;
     RECT  14.856 34.741 15.84 36.277 ;
     RECT  16.776 34.835 18.6 35.845 ;
     RECT  40.512 35.269 41.904 36.515 ;
     RECT  31.896 35.747 32.52 36.421 ;
     RECT  16.776 35.845 18.48 36.181 ;
     RECT  35.112 35.845 36.384 36.901 ;
     RECT  36.456 35.939 36.504 37.093 ;
     RECT  17.112 36.181 18.48 36.515 ;
     RECT  15.864 36.227 17.088 36.515 ;
     RECT  31.896 36.421 33.024 36.851 ;
     RECT  17.952 36.515 18.48 37.525 ;
     RECT  31.848 36.851 33.024 38.293 ;
     RECT  35.208 36.901 36.384 37.621 ;
     RECT  12.168 37.573 13.2 39.635 ;
     RECT  22.608 37.859 22.992 38.581 ;
     RECT  29.712 38.101 30.864 38.149 ;
     RECT  29.712 38.149 30.768 40.019 ;
     RECT  31.848 38.435 33.024 38.819 ;
     RECT  21.768 38.581 22.992 39.923 ;
     RECT  33.576 38.581 34.8 42.805 ;
     RECT  12.024 39.635 13.2 41.651 ;
     RECT  29.712 40.019 30.864 41.893 ;
     RECT  40.512 40.067 41.064 41.029 ;
     RECT  23.016 40.307 24 42.085 ;
     RECT  24.312 40.309 25.68 42.757 ;
     RECT  25.704 40.355 26.28 40.405 ;
     RECT  25.704 40.405 26.928 42.227 ;
     RECT  40.512 41.029 42.192 41.173 ;
     RECT  40.512 41.173 41.568 43.283 ;
     RECT  30.888 41.557 32.112 41.939 ;
     RECT  41.592 41.651 42.216 42.997 ;
     RECT  2.712 42.085 3.792 43.283 ;
     RECT  13.512 42.133 14.736 42.709 ;
     RECT  27.288 42.133 28.512 42.757 ;
     RECT  13.608 42.709 14.736 42.803 ;
     RECT  18.912 42.709 19.92 44.627 ;
     RECT  24.408 42.757 25.68 42.899 ;
     RECT  27.336 42.757 28.512 42.803 ;
     RECT  13.608 42.803 14.28 44.053 ;
     RECT  23.016 42.803 24 43.813 ;
     RECT  24.312 42.899 25.68 43.523 ;
     RECT  41.592 42.997 43.104 43.283 ;
     RECT  17.352 43.093 18.6 47.173 ;
     RECT  40.512 43.283 41.16 43.765 ;
     RECT  15.864 43.381 17.328 44.627 ;
     RECT  24.312 43.523 25.224 44.677 ;
     RECT  37.056 43.571 37.08 43.957 ;
     RECT  30.504 43.667 30.84 44.965 ;
     RECT  37.056 43.957 37.584 44.149 ;
     RECT  35.832 44.149 37.584 44.965 ;
     RECT  8.28 44.627 8.712 46.117 ;
     RECT  16.896 44.627 17.328 45.541 ;
     RECT  18.912 44.627 19.944 45.013 ;
     RECT  22.08 44.915 22.992 45.589 ;
     RECT  35.832 44.965 37.296 46.787 ;
     RECT  18.912 45.013 20.256 46.787 ;
     RECT  20.28 45.589 21.744 46.787 ;
     RECT  21.768 45.589 22.992 47.891 ;
     RECT  39.216 45.635 40.2 45.781 ;
     RECT  23.016 45.731 24 56.293 ;
     RECT  39.192 45.781 40.2 47.699 ;
     RECT  11.688 46.117 13.2 47.363 ;
     RECT  27.96 46.117 29.28 46.787 ;
     RECT  27.168 46.163 27.264 46.259 ;
     RECT  27.168 46.259 27.408 46.501 ;
     RECT  33.624 46.307 34.8 48.421 ;
     RECT  25.224 46.501 26.208 46.547 ;
     RECT  26.232 46.501 27.408 46.547 ;
     RECT  32.52 46.645 33.6 46.787 ;
     RECT  18.912 46.787 19.368 47.845 ;
     RECT  32.232 46.787 33.6 47.747 ;
     RECT  40.512 46.835 40.68 47.893 ;
     RECT  17.088 47.219 17.328 48.373 ;
     RECT  30.84 47.315 32.208 47.747 ;
     RECT  38.904 47.699 40.2 47.891 ;
     RECT  30.84 47.747 31.32 48.805 ;
     RECT  40.776 47.893 42.24 47.989 ;
     RECT  41.112 47.989 42.24 48.853 ;
     RECT  24.984 48.421 26.208 48.709 ;
     RECT  33.624 48.421 34.704 49.475 ;
     RECT  24.984 48.709 26.064 49.475 ;
     RECT  33.624 49.475 34.8 51.637 ;
     RECT  17.16 49.571 18.6 51.923 ;
     RECT  26.232 49.717 27.312 50.819 ;
     RECT  37.296 50.051 37.488 51.109 ;
     RECT  16.368 50.147 17.136 50.677 ;
     RECT  11.544 50.533 12.528 50.675 ;
     RECT  12.384 50.675 12.528 51.637 ;
     RECT  15.528 50.677 17.136 51.541 ;
     RECT  13.512 50.965 14.544 51.683 ;
     RECT  40.776 51.107 41.856 51.923 ;
     RECT  21.768 51.109 22.992 52.211 ;
     RECT  35.112 51.109 36.432 52.405 ;
     RECT  36.456 51.109 37.488 52.451 ;
     RECT  8.28 51.493 9.552 52.595 ;
     RECT  42.84 51.493 44.064 52.499 ;
     RECT  33.624 51.637 34.704 53.077 ;
     RECT  22.512 52.211 22.992 52.933 ;
     RECT  35.112 52.405 36.144 53.557 ;
     RECT  36.168 52.451 37.488 53.027 ;
     RECT  9.576 52.549 10.8 52.595 ;
     RECT  33.624 53.219 34.8 55.715 ;
     RECT  35.112 53.699 36.144 54.179 ;
     RECT  10.824 53.941 12.24 54.035 ;
     RECT  38.808 55.237 40.2 56.435 ;
     RECT  33.336 55.715 34.8 56.965 ;
     RECT  37.608 55.907 38.784 56.435 ;
     RECT  14.232 56.389 15.456 57.107 ;
     RECT  23.016 56.435 24 57.395 ;
     RECT  39.168 56.435 40.2 57.541 ;
     RECT  30.984 56.483 31.416 57.445 ;
     RECT  8.28 56.869 9.312 58.117 ;
     RECT  33.336 56.965 34.656 59.171 ;
     RECT  13.512 57.107 15.456 58.501 ;
     RECT  30.984 57.445 32.448 57.491 ;
     RECT  32.256 57.491 32.448 58.693 ;
     RECT  9.336 57.541 10.608 58.597 ;
     RECT  39.192 57.541 40.2 58.163 ;
     RECT  14.28 58.501 15.456 58.691 ;
     RECT  9.384 58.597 10.608 58.787 ;
     RECT  35.88 58.645 37.296 59.173 ;
     RECT  8.376 58.739 9.36 59.123 ;
     RECT  32.28 58.739 33.264 58.787 ;
     RECT  32.28 58.787 33.312 61.667 ;
     RECT  8.28 59.123 9.36 61.043 ;
     RECT  33.336 59.171 34.8 61.667 ;
     RECT  30.84 59.797 32.256 60.517 ;
     RECT  17.208 59.941 18.6 60.275 ;
     RECT  30.84 60.517 31.92 60.995 ;
     RECT  38.856 60.757 40.2 61.907 ;
     RECT  13.512 60.947 14.28 61.813 ;
     RECT  30.84 60.995 32.256 61.381 ;
     RECT  31.272 61.381 32.256 62.339 ;
     RECT  11.208 61.477 12.672 62.195 ;
     RECT  35.112 61.619 35.496 62.581 ;
     RECT  34.32 61.667 34.8 62.677 ;
     RECT  13.512 61.813 14.592 63.299 ;
     RECT  14.616 61.813 16.032 63.013 ;
     RECT  22.776 62.101 24 63.779 ;
     RECT  30.936 62.339 32.256 62.771 ;
     RECT  8.28 62.581 9.552 63.251 ;
     RECT  30.936 62.771 31.176 63.541 ;
     RECT  15.576 63.059 16.752 65.603 ;
     RECT  8.28 63.251 9.696 65.603 ;
     RECT  29.712 63.587 30.816 64.451 ;
     RECT  33.816 63.827 34.8 70.307 ;
     RECT  16.776 64.885 17.856 65.603 ;
     RECT  17.712 65.603 17.856 66.085 ;
     RECT  24.312 66.133 25.68 66.755 ;
     RECT  24.312 66.755 24.552 67.429 ;
     RECT  15.576 67.765 16.704 68.387 ;
     RECT  13.512 68.245 14.832 68.387 ;
     RECT  29.832 68.341 31.296 69.251 ;
     RECT  35.832 68.341 36.816 70.019 ;
     RECT  13.512 68.387 13.656 68.965 ;
     RECT  15.432 68.387 16.704 68.435 ;
     RECT  26.952 68.917 28.464 70.019 ;
     RECT  24.312 68.963 24.552 70.357 ;
     RECT  29.832 69.251 31.92 69.973 ;
     RECT  29.832 69.973 30.864 70.739 ;
     RECT  30.888 69.973 31.92 70.259 ;
     RECT  27.936 70.019 28.464 70.213 ;
     RECT  35.112 70.019 36.816 70.645 ;
     RECT  27.96 70.259 29.4 72.661 ;
     RECT  30.888 70.259 31.944 71.509 ;
     RECT  12.72 70.307 13.2 70.405 ;
     RECT  12.024 70.405 13.2 71.315 ;
     RECT  35.112 70.645 36.432 71.461 ;
     RECT  29.712 70.739 30.864 72.035 ;
     RECT  18.912 70.835 19.512 71.749 ;
     RECT  35.4 71.461 36.432 72.899 ;
     RECT  30.888 71.509 32.16 72.035 ;
     RECT  18.912 71.749 20.4 72.419 ;
     RECT  22.44 71.749 23.808 72.419 ;
     RECT  16.344 71.797 17.616 72.131 ;
     RECT  29.712 72.035 30.264 72.565 ;
     RECT  40.512 72.419 41.808 72.467 ;
     RECT  28.2 72.661 29.4 72.709 ;
     RECT  35.112 72.899 36.432 74.581 ;
     RECT  17.616 73.523 18.6 74.053 ;
     RECT  4.728 74.053 5.76 74.339 ;
     RECT  17.256 74.053 18.6 75.923 ;
     RECT  28.2 74.291 29.4 76.979 ;
     RECT  35.112 74.581 36.24 75.827 ;
     RECT  41.016 75.205 42.48 75.251 ;
     RECT  35.112 75.827 36.432 76.787 ;
     RECT  8.376 76.691 8.904 77.893 ;
     RECT  35.112 76.787 35.352 77.029 ;
     RECT  33.624 77.173 34.8 78.277 ;
     RECT  33.672 78.277 34.8 78.467 ;
     RECT  33.6 78.467 34.8 78.469 ;
     RECT  33.48 78.469 34.8 78.611 ;
     RECT  2.712 78.613 4.128 79.235 ;
     RECT  42.504 78.707 43.488 79.283 ;
  END
END dsfd_coll_cesx
END LIBRARY
